VERSION 5.7 ;
  NOWIREEXTENSIONATPIN ON ;
  DIVIDERCHAR "/" ;
  BUSBITCHARS "[]" ;
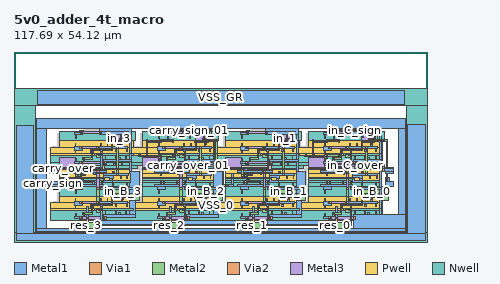
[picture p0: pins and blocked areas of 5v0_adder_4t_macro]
MACRO 5v0_adder_4t_macro
  CLASS BLOCK ;
  FOREIGN 5v0_adder_4t_macro ;
  ORIGIN 97.720 28.280 ;
  SIZE 117.690 BY 54.120 ;
  PIN VDD_1V65
    DIRECTION INOUT ;
    USE SIGNAL ;
    ANTENNADIFFAREA 2.102100 ;
    PORT
      LAYER Metal1 ;
        RECT -73.025 -18.050 -72.490 -17.485 ;
        RECT -49.350 -18.050 -48.815 -17.485 ;
        RECT -25.675 -18.050 -25.140 -17.485 ;
        RECT -2.000 -18.050 -1.465 -17.485 ;
        RECT -72.950 -18.850 -72.565 -18.050 ;
        RECT -49.275 -18.850 -48.890 -18.050 ;
        RECT -25.600 -18.850 -25.215 -18.050 ;
        RECT -1.925 -18.850 -1.540 -18.050 ;
        RECT -73.515 -19.340 -72.565 -18.850 ;
        RECT -49.840 -19.340 -48.890 -18.850 ;
        RECT -26.165 -19.340 -25.215 -18.850 ;
        RECT -2.490 -19.340 -1.540 -18.850 ;
        RECT -72.950 -22.125 -72.565 -19.340 ;
        RECT -49.275 -22.125 -48.890 -19.340 ;
        RECT -25.600 -22.125 -25.215 -19.340 ;
        RECT -72.950 -23.240 -57.735 -22.125 ;
        RECT -49.275 -23.240 -34.060 -22.125 ;
        RECT -25.600 -23.240 -10.385 -22.125 ;
        RECT -1.925 -23.240 -1.540 -19.340 ;
        RECT -77.040 -23.660 -1.535 -23.240 ;
      LAYER Via1 ;
        RECT -73.360 -19.300 -72.695 -18.925 ;
        RECT -49.685 -19.300 -49.020 -18.925 ;
        RECT -26.010 -19.300 -25.345 -18.925 ;
        RECT -2.335 -19.300 -1.670 -18.925 ;
      LAYER Metal2 ;
        RECT -74.225 -19.935 -72.635 -18.900 ;
        RECT -50.550 -19.935 -48.960 -18.900 ;
        RECT -26.875 -19.935 -25.285 -18.900 ;
        RECT -3.200 -19.935 -1.610 -18.900 ;
    END
  END VDD_1V65
  PIN res_0
    DIRECTION INOUT ;
    USE SIGNAL ;
    ANTENNADIFFAREA 1.060800 ;
    PORT
      LAYER Metal1 ;
        RECT -6.015 -22.680 -5.585 -18.035 ;
      LAYER Via1 ;
        RECT -6.015 -22.620 -5.585 -21.490 ;
      LAYER Metal2 ;
        RECT -6.025 -22.680 -5.575 -21.430 ;
        RECT -9.800 -24.360 -2.520 -22.680 ;
    END
  END res_0
  PIN res_1
    DIRECTION INOUT ;
    USE SIGNAL ;
    ANTENNADIFFAREA 1.060800 ;
    PORT
      LAYER Metal1 ;
        RECT -29.690 -22.680 -29.260 -18.035 ;
      LAYER Via1 ;
        RECT -29.690 -22.620 -29.260 -21.490 ;
      LAYER Metal2 ;
        RECT -29.700 -22.680 -29.250 -21.430 ;
        RECT -33.475 -24.360 -26.195 -22.680 ;
    END
  END res_1
  PIN res_2
    DIRECTION INOUT ;
    USE SIGNAL ;
    ANTENNADIFFAREA 1.060800 ;
    PORT
      LAYER Metal1 ;
        RECT -53.365 -22.680 -52.935 -18.035 ;
      LAYER Via1 ;
        RECT -53.365 -22.620 -52.935 -21.490 ;
      LAYER Metal2 ;
        RECT -53.375 -22.680 -52.925 -21.430 ;
        RECT -57.150 -24.360 -49.870 -22.680 ;
    END
  END res_2
  PIN res_3
    DIRECTION INOUT ;
    USE SIGNAL ;
    ANTENNADIFFAREA 1.060800 ;
    PORT
      LAYER Metal1 ;
        RECT -77.040 -22.680 -76.610 -18.035 ;
      LAYER Via1 ;
        RECT -77.040 -22.620 -76.610 -21.490 ;
      LAYER Metal2 ;
        RECT -77.050 -22.680 -76.600 -21.430 ;
        RECT -80.825 -24.360 -73.545 -22.680 ;
    END
  END res_3
  PIN carry_over
    DIRECTION OUTPUT ;
    USE SIGNAL ;
    ANTENNADIFFAREA 1.456350 ;
    PORT
      LAYER Metal1 ;
        RECT -87.640 -7.005 -85.395 -7.000 ;
        RECT -87.640 -7.560 -79.835 -7.005 ;
        RECT -87.640 -8.680 -85.395 -7.560 ;
        RECT -78.815 -9.410 -77.215 -9.180 ;
        RECT -78.815 -10.170 -78.525 -9.410 ;
        RECT -78.815 -10.405 -77.980 -10.170 ;
        RECT -78.255 -11.135 -77.980 -10.405 ;
        RECT -78.255 -11.405 -75.540 -11.135 ;
      LAYER Via1 ;
        RECT -80.385 -7.525 -79.900 -7.235 ;
        RECT -78.815 -9.760 -78.525 -9.275 ;
      LAYER Metal2 ;
        RECT -80.445 -7.540 -79.835 -7.215 ;
        RECT -80.210 -9.180 -79.835 -7.540 ;
        RECT -78.815 -9.180 -78.525 -9.175 ;
        RECT -80.210 -9.510 -78.515 -9.180 ;
        RECT -78.825 -9.820 -78.515 -9.510 ;
    END
  END carry_over
  PIN carry_sign
    DIRECTION OUTPUT ;
    USE SIGNAL ;
    ANTENNADIFFAREA 1.060800 ;
    PORT
      LAYER Metal1 ;
        RECT -87.640 -12.030 -85.395 -10.920 ;
        RECT -83.040 -12.030 -82.610 -8.810 ;
        RECT -87.640 -12.525 -82.610 -12.030 ;
        RECT -87.640 -12.600 -85.395 -12.525 ;
    END
  END carry_sign
  PIN in_C_sign
    DIRECTION INPUT ;
    USE SIGNAL ;
    ANTENNAGATEAREA 4.408000 ;
    PORT
      LAYER Metal1 ;
        RECT -12.600 -4.025 -12.275 0.935 ;
        RECT -8.800 -0.065 -8.475 0.935 ;
        RECT -5.355 -0.065 -5.030 0.935 ;
        RECT 8.120 -10.920 9.240 -10.025 ;
        RECT 8.120 -12.600 10.360 -10.920 ;
      LAYER Via1 ;
        RECT -12.600 0.040 -12.275 0.695 ;
        RECT -8.775 0.015 -8.505 0.860 ;
        RECT -5.320 0.330 -5.055 0.870 ;
        RECT -12.600 -3.785 -12.275 -3.130 ;
        RECT 8.265 -10.825 8.685 -10.085 ;
      LAYER Metal2 ;
        RECT -6.780 3.375 5.760 3.795 ;
        RECT -6.780 0.935 -6.360 3.375 ;
        RECT -12.610 0.350 -12.265 0.755 ;
        RECT -8.800 0.430 -5.025 0.935 ;
        RECT -8.800 0.350 -8.475 0.430 ;
        RECT -12.610 0.015 -8.475 0.350 ;
        RECT -5.360 0.265 -5.025 0.430 ;
        RECT 5.340 0.845 5.760 3.375 ;
        RECT 5.340 0.425 8.685 0.845 ;
        RECT -12.610 -0.020 -12.265 0.015 ;
        RECT -8.800 -0.065 -8.475 0.015 ;
        RECT -12.610 -3.845 -12.265 -3.070 ;
        RECT 8.265 -10.075 8.685 0.425 ;
        RECT 8.180 -10.840 8.770 -10.075 ;
    END
  END in_C_sign
  PIN in_C_over
    DIRECTION INPUT ;
    USE SIGNAL ;
    ANTENNAGATEAREA 2.814000 ;
    PORT
      LAYER Metal1 ;
        RECT -8.800 -3.225 -8.475 -3.025 ;
        RECT -14.775 -4.010 -14.475 -3.485 ;
        RECT -9.175 -4.025 -8.475 -3.225 ;
        RECT -5.355 -4.025 -5.030 -3.025 ;
        RECT 7.365 -7.380 7.785 -7.320 ;
        RECT 8.120 -7.380 10.360 -7.000 ;
        RECT 7.365 -8.120 10.360 -7.380 ;
        RECT 7.365 -8.180 7.785 -8.120 ;
        RECT 8.120 -8.680 10.360 -8.120 ;
      LAYER Via1 ;
        RECT -14.775 -3.935 -14.475 -3.565 ;
        RECT -8.760 -3.955 -8.490 -3.150 ;
        RECT -5.320 -3.960 -5.055 -3.420 ;
      LAYER Metal2 ;
        RECT -8.800 -3.360 -8.470 -3.090 ;
        RECT -7.635 -3.360 -6.540 -3.025 ;
        RECT -5.360 -3.360 -5.025 -3.355 ;
        RECT -14.785 -4.010 -14.465 -3.505 ;
        RECT -8.800 -4.025 -5.025 -3.360 ;
        RECT 7.355 -8.180 7.795 -7.320 ;
      LAYER Via2 ;
        RECT -14.775 -3.935 -14.475 -3.565 ;
        RECT -8.760 -3.955 -8.475 -3.150 ;
        RECT 7.365 -8.120 7.785 -7.380 ;
      LAYER Metal3 ;
        RECT -14.825 -3.630 -14.425 -3.565 ;
        RECT -8.810 -3.630 -8.425 -3.150 ;
        RECT -14.975 -3.955 -8.425 -3.630 ;
        RECT -8.725 -6.330 -8.425 -3.955 ;
        RECT -8.725 -6.655 7.785 -6.330 ;
        RECT 7.365 -8.180 7.785 -6.655 ;
    END
  END in_C_over
  PIN VSS_0
    DIRECTION INOUT ;
    USE GROUND ;
    PORT
      LAYER Pwell ;
        RECT -84.765 0.490 -74.915 0.495 ;
        RECT -61.090 0.490 -51.240 0.495 ;
        RECT -37.415 0.490 -27.565 0.495 ;
        RECT -13.740 0.490 -3.890 0.495 ;
        RECT -84.765 -1.395 -63.715 0.490 ;
        RECT -61.090 -1.395 -40.040 0.490 ;
        RECT -37.415 -1.395 -16.365 0.490 ;
        RECT -13.740 -1.395 7.310 0.490 ;
        RECT -87.450 -3.030 7.310 -1.395 ;
        RECT -87.450 -3.585 -74.915 -3.030 ;
        RECT -63.775 -3.585 -51.240 -3.030 ;
        RECT -40.100 -3.585 -27.565 -3.030 ;
        RECT -16.425 -3.585 -3.890 -3.030 ;
        RECT -71.805 -7.760 -64.660 -7.350 ;
        RECT -48.130 -7.760 -40.985 -7.350 ;
        RECT -24.455 -7.760 -17.310 -7.350 ;
        RECT -0.780 -7.760 6.365 -7.350 ;
        RECT -84.735 -8.680 -64.660 -7.760 ;
        RECT -61.060 -8.680 -40.985 -7.760 ;
        RECT -37.385 -8.680 -17.310 -7.760 ;
        RECT -13.710 -8.680 6.365 -7.760 ;
        RECT -84.735 -8.810 -64.655 -8.680 ;
        RECT -84.735 -9.950 -70.435 -8.810 ;
        RECT -77.965 -10.075 -76.865 -9.950 ;
        RECT -71.805 -10.785 -70.435 -9.950 ;
        RECT -70.370 -10.785 -64.655 -8.810 ;
        RECT -61.060 -8.810 -40.980 -8.680 ;
        RECT -61.060 -9.950 -46.760 -8.810 ;
        RECT -54.290 -10.075 -53.190 -9.950 ;
        RECT -71.805 -10.870 -64.655 -10.785 ;
        RECT -48.130 -10.785 -46.760 -9.950 ;
        RECT -46.695 -10.785 -40.980 -8.810 ;
        RECT -37.385 -8.810 -17.305 -8.680 ;
        RECT -37.385 -9.950 -23.085 -8.810 ;
        RECT -30.615 -10.075 -29.515 -9.950 ;
        RECT -48.130 -10.870 -40.980 -10.785 ;
        RECT -24.455 -10.785 -23.085 -9.950 ;
        RECT -23.020 -10.785 -17.305 -8.810 ;
        RECT -13.710 -8.810 6.370 -8.680 ;
        RECT -13.710 -9.950 0.590 -8.810 ;
        RECT -6.940 -10.075 -5.840 -9.950 ;
        RECT -24.455 -10.870 -17.305 -10.785 ;
        RECT -0.780 -10.785 0.590 -9.950 ;
        RECT 0.655 -10.785 6.370 -8.810 ;
        RECT -0.780 -10.870 6.370 -10.785 ;
        RECT -84.765 -15.190 -74.915 -15.185 ;
        RECT -61.090 -15.190 -51.240 -15.185 ;
        RECT -37.415 -15.190 -27.565 -15.185 ;
        RECT -13.740 -15.190 -3.890 -15.185 ;
        RECT -84.765 -17.075 -63.715 -15.190 ;
        RECT -61.090 -17.075 -40.040 -15.190 ;
        RECT -37.415 -17.075 -16.365 -15.190 ;
        RECT -13.740 -17.075 7.310 -15.190 ;
        RECT -87.450 -18.710 7.310 -17.075 ;
        RECT -87.450 -19.265 -74.915 -18.710 ;
        RECT -63.775 -19.265 -51.240 -18.710 ;
        RECT -40.100 -19.265 -27.565 -18.710 ;
        RECT -16.425 -19.265 -3.890 -18.710 ;
      LAYER Metal1 ;
        RECT -80.290 -0.965 -80.060 -0.105 ;
        RECT -80.535 -2.125 -78.295 -0.965 ;
        RECT -73.040 -0.970 -72.810 -0.215 ;
        RECT -71.200 -0.970 -70.970 -0.110 ;
        RECT -67.125 -0.540 -66.665 -0.310 ;
        RECT -67.070 -0.970 -66.720 -0.540 ;
        RECT -56.615 -0.965 -56.385 -0.105 ;
        RECT -66.410 -0.970 -65.835 -0.965 ;
        RECT -74.225 -1.570 -65.265 -0.970 ;
        RECT -68.790 -1.800 -68.495 -1.570 ;
        RECT -68.065 -1.645 -67.505 -1.570 ;
        RECT -80.290 -2.985 -80.060 -2.125 ;
        RECT -68.845 -2.370 -68.440 -1.800 ;
        RECT -65.740 -2.430 -65.510 -1.570 ;
        RECT -56.860 -2.125 -54.620 -0.965 ;
        RECT -49.365 -0.970 -49.135 -0.215 ;
        RECT -47.525 -0.970 -47.295 -0.110 ;
        RECT -43.450 -0.540 -42.990 -0.310 ;
        RECT -43.395 -0.970 -43.045 -0.540 ;
        RECT -32.940 -0.965 -32.710 -0.105 ;
        RECT -42.735 -0.970 -42.160 -0.965 ;
        RECT -50.550 -1.570 -41.590 -0.970 ;
        RECT -45.115 -1.800 -44.820 -1.570 ;
        RECT -44.390 -1.645 -43.830 -1.570 ;
        RECT -56.615 -2.985 -56.385 -2.125 ;
        RECT -45.170 -2.370 -44.765 -1.800 ;
        RECT -42.065 -2.430 -41.835 -1.570 ;
        RECT -33.185 -2.125 -30.945 -0.965 ;
        RECT -25.690 -0.970 -25.460 -0.215 ;
        RECT -23.850 -0.970 -23.620 -0.110 ;
        RECT -19.775 -0.540 -19.315 -0.310 ;
        RECT -19.720 -0.970 -19.370 -0.540 ;
        RECT -9.265 -0.965 -9.035 -0.105 ;
        RECT -19.060 -0.970 -18.485 -0.965 ;
        RECT -26.875 -1.570 -17.915 -0.970 ;
        RECT -21.440 -1.800 -21.145 -1.570 ;
        RECT -20.715 -1.645 -20.155 -1.570 ;
        RECT -32.940 -2.985 -32.710 -2.125 ;
        RECT -21.495 -2.370 -21.090 -1.800 ;
        RECT -18.390 -2.430 -18.160 -1.570 ;
        RECT -9.510 -2.125 -7.270 -0.965 ;
        RECT -2.015 -0.970 -1.785 -0.215 ;
        RECT -0.175 -0.970 0.055 -0.110 ;
        RECT 3.900 -0.540 4.360 -0.310 ;
        RECT 3.955 -0.970 4.305 -0.540 ;
        RECT 4.615 -0.970 5.190 -0.965 ;
        RECT -3.200 -1.570 5.760 -0.970 ;
        RECT 2.235 -1.800 2.530 -1.570 ;
        RECT 2.960 -1.645 3.520 -1.570 ;
        RECT -9.265 -2.985 -9.035 -2.125 ;
        RECT 2.180 -2.370 2.585 -1.800 ;
        RECT 5.285 -2.430 5.515 -1.570 ;
        RECT -79.545 -7.890 -78.655 -7.400 ;
        RECT -55.870 -7.890 -54.980 -7.400 ;
        RECT -32.195 -7.890 -31.305 -7.400 ;
        RECT -8.520 -7.890 -7.630 -7.400 ;
        RECT -81.355 -8.490 -71.425 -7.890 ;
        RECT -69.645 -8.380 -69.185 -8.150 ;
        RECT -79.590 -9.350 -79.360 -8.490 ;
        RECT -74.945 -8.950 -74.605 -8.490 ;
        RECT -72.330 -8.805 -71.425 -8.490 ;
        RECT -69.590 -8.805 -69.240 -8.380 ;
        RECT -57.680 -8.490 -47.750 -7.890 ;
        RECT -45.970 -8.380 -45.510 -8.150 ;
        RECT -72.330 -8.810 -69.240 -8.805 ;
        RECT -72.330 -9.410 -65.085 -8.810 ;
        RECT -55.915 -9.350 -55.685 -8.490 ;
        RECT -51.270 -8.950 -50.930 -8.490 ;
        RECT -48.655 -8.805 -47.750 -8.490 ;
        RECT -45.915 -8.805 -45.565 -8.380 ;
        RECT -34.005 -8.490 -24.075 -7.890 ;
        RECT -22.295 -8.380 -21.835 -8.150 ;
        RECT -48.655 -8.810 -45.565 -8.805 ;
        RECT -48.655 -9.410 -41.410 -8.810 ;
        RECT -32.240 -9.350 -32.010 -8.490 ;
        RECT -27.595 -8.950 -27.255 -8.490 ;
        RECT -24.980 -8.805 -24.075 -8.490 ;
        RECT -22.240 -8.805 -21.890 -8.380 ;
        RECT -10.330 -8.490 -0.400 -7.890 ;
        RECT 1.380 -8.380 1.840 -8.150 ;
        RECT -24.980 -8.810 -21.890 -8.805 ;
        RECT -24.980 -9.410 -17.735 -8.810 ;
        RECT -8.565 -9.350 -8.335 -8.490 ;
        RECT -3.920 -8.950 -3.580 -8.490 ;
        RECT -0.960 -8.805 -0.400 -8.490 ;
        RECT 1.435 -8.805 1.785 -8.380 ;
        RECT -1.305 -8.810 1.785 -8.805 ;
        RECT -1.305 -9.410 5.940 -8.810 ;
        RECT -72.330 -10.055 -69.465 -9.410 ;
        RECT -72.330 -11.385 -69.600 -10.055 ;
        RECT -67.455 -10.200 -67.225 -9.410 ;
        RECT -65.560 -10.270 -65.330 -9.410 ;
        RECT -48.655 -10.055 -45.790 -9.410 ;
        RECT -48.655 -11.385 -45.925 -10.055 ;
        RECT -43.780 -10.200 -43.550 -9.410 ;
        RECT -41.885 -10.270 -41.655 -9.410 ;
        RECT -24.980 -10.055 -22.115 -9.410 ;
        RECT -24.980 -11.385 -22.250 -10.055 ;
        RECT -20.105 -10.200 -19.875 -9.410 ;
        RECT -18.210 -10.270 -17.980 -9.410 ;
        RECT -1.305 -10.055 1.560 -9.410 ;
        RECT -1.305 -11.385 1.425 -10.055 ;
        RECT 3.570 -10.200 3.800 -9.410 ;
        RECT 5.465 -10.270 5.695 -9.410 ;
        RECT -80.290 -16.645 -80.060 -15.785 ;
        RECT -80.535 -17.805 -78.295 -16.645 ;
        RECT -73.040 -16.650 -72.810 -15.895 ;
        RECT -71.200 -16.650 -70.970 -15.790 ;
        RECT -67.125 -16.220 -66.665 -15.990 ;
        RECT -67.070 -16.650 -66.720 -16.220 ;
        RECT -56.615 -16.645 -56.385 -15.785 ;
        RECT -66.410 -16.650 -65.835 -16.645 ;
        RECT -74.225 -17.250 -65.265 -16.650 ;
        RECT -68.790 -17.480 -68.495 -17.250 ;
        RECT -68.065 -17.325 -67.505 -17.250 ;
        RECT -80.290 -18.665 -80.060 -17.805 ;
        RECT -68.845 -18.050 -68.440 -17.480 ;
        RECT -65.740 -18.110 -65.510 -17.250 ;
        RECT -56.860 -17.805 -54.620 -16.645 ;
        RECT -49.365 -16.650 -49.135 -15.895 ;
        RECT -47.525 -16.650 -47.295 -15.790 ;
        RECT -43.450 -16.220 -42.990 -15.990 ;
        RECT -43.395 -16.650 -43.045 -16.220 ;
        RECT -32.940 -16.645 -32.710 -15.785 ;
        RECT -42.735 -16.650 -42.160 -16.645 ;
        RECT -50.550 -17.250 -41.590 -16.650 ;
        RECT -45.115 -17.480 -44.820 -17.250 ;
        RECT -44.390 -17.325 -43.830 -17.250 ;
        RECT -56.615 -18.665 -56.385 -17.805 ;
        RECT -45.170 -18.050 -44.765 -17.480 ;
        RECT -42.065 -18.110 -41.835 -17.250 ;
        RECT -33.185 -17.805 -30.945 -16.645 ;
        RECT -25.690 -16.650 -25.460 -15.895 ;
        RECT -23.850 -16.650 -23.620 -15.790 ;
        RECT -19.775 -16.220 -19.315 -15.990 ;
        RECT -19.720 -16.650 -19.370 -16.220 ;
        RECT -9.265 -16.645 -9.035 -15.785 ;
        RECT -19.060 -16.650 -18.485 -16.645 ;
        RECT -26.875 -17.250 -17.915 -16.650 ;
        RECT -21.440 -17.480 -21.145 -17.250 ;
        RECT -20.715 -17.325 -20.155 -17.250 ;
        RECT -32.940 -18.665 -32.710 -17.805 ;
        RECT -21.495 -18.050 -21.090 -17.480 ;
        RECT -18.390 -18.110 -18.160 -17.250 ;
        RECT -9.510 -17.805 -7.270 -16.645 ;
        RECT -2.015 -16.650 -1.785 -15.895 ;
        RECT -0.175 -16.650 0.055 -15.790 ;
        RECT 3.900 -16.220 4.360 -15.990 ;
        RECT 3.955 -16.650 4.305 -16.220 ;
        RECT 4.615 -16.650 5.190 -16.645 ;
        RECT -3.200 -17.250 5.760 -16.650 ;
        RECT 2.235 -17.480 2.530 -17.250 ;
        RECT 2.960 -17.325 3.520 -17.250 ;
        RECT -9.265 -18.665 -9.035 -17.805 ;
        RECT 2.180 -18.050 2.585 -17.480 ;
        RECT 5.285 -18.110 5.515 -17.250 ;
      LAYER Via1 ;
        RECT -78.985 -1.570 -78.425 -0.970 ;
        RECT -74.140 -1.570 -73.580 -0.970 ;
        RECT -68.540 -1.570 -68.015 -1.095 ;
        RECT -55.310 -1.570 -54.750 -0.970 ;
        RECT -50.465 -1.570 -49.905 -0.970 ;
        RECT -44.865 -1.570 -44.340 -1.095 ;
        RECT -31.635 -1.570 -31.075 -0.970 ;
        RECT -26.790 -1.570 -26.230 -0.970 ;
        RECT -21.190 -1.570 -20.665 -1.095 ;
        RECT -7.960 -1.570 -7.400 -0.970 ;
        RECT -3.115 -1.570 -2.555 -0.970 ;
        RECT 2.485 -1.570 3.010 -1.095 ;
        RECT -74.140 -8.435 -73.500 -7.940 ;
        RECT -50.465 -8.435 -49.825 -7.940 ;
        RECT -68.540 -9.345 -68.015 -8.870 ;
        RECT -26.790 -8.435 -26.150 -7.940 ;
        RECT -44.865 -9.345 -44.340 -8.870 ;
        RECT -3.115 -8.435 -2.475 -7.940 ;
        RECT -21.190 -9.345 -20.665 -8.870 ;
        RECT 2.485 -9.345 3.010 -8.870 ;
        RECT -78.985 -17.250 -78.425 -16.650 ;
        RECT -74.140 -17.250 -73.580 -16.650 ;
        RECT -55.310 -17.250 -54.750 -16.650 ;
        RECT -50.465 -17.250 -49.905 -16.650 ;
        RECT -31.635 -17.250 -31.075 -16.650 ;
        RECT -26.790 -17.250 -26.230 -16.650 ;
        RECT -7.960 -17.250 -7.400 -16.650 ;
        RECT -3.115 -17.250 -2.555 -16.650 ;
      LAYER Metal2 ;
        RECT -79.045 -1.580 -78.365 -0.960 ;
        RECT -74.225 -1.585 -73.500 -0.960 ;
        RECT -68.560 -1.570 -67.995 -1.030 ;
        RECT -74.190 -8.490 -73.450 -7.890 ;
        RECT -68.555 -9.410 -67.995 -1.570 ;
        RECT -55.370 -1.580 -54.690 -0.960 ;
        RECT -50.550 -1.585 -49.825 -0.960 ;
        RECT -44.885 -1.570 -44.320 -1.030 ;
        RECT -50.515 -8.490 -49.775 -7.890 ;
        RECT -44.880 -9.410 -44.320 -1.570 ;
        RECT -31.695 -1.580 -31.015 -0.960 ;
        RECT -26.875 -1.585 -26.150 -0.960 ;
        RECT -21.210 -1.570 -20.645 -1.030 ;
        RECT -26.840 -8.490 -26.100 -7.890 ;
        RECT -21.205 -9.410 -20.645 -1.570 ;
        RECT -8.020 -1.580 -7.340 -0.960 ;
        RECT -3.200 -1.585 -2.475 -0.960 ;
        RECT 2.465 -1.570 3.030 -1.030 ;
        RECT -3.165 -8.490 -2.425 -7.890 ;
        RECT 2.470 -9.410 3.030 -1.570 ;
        RECT -74.140 -16.640 -73.500 -12.745 ;
        RECT -50.465 -16.640 -49.825 -12.745 ;
        RECT -26.790 -16.640 -26.150 -12.745 ;
        RECT -3.115 -16.640 -2.475 -12.745 ;
        RECT -79.045 -17.260 -78.365 -16.640 ;
        RECT -74.225 -17.265 -73.500 -16.640 ;
        RECT -55.370 -17.260 -54.690 -16.640 ;
        RECT -50.550 -17.265 -49.825 -16.640 ;
        RECT -31.695 -17.260 -31.015 -16.640 ;
        RECT -26.875 -17.265 -26.150 -16.640 ;
        RECT -8.020 -17.260 -7.340 -16.640 ;
        RECT -3.200 -17.265 -2.475 -16.640 ;
      LAYER Via2 ;
        RECT -78.985 -1.570 -78.425 -0.970 ;
        RECT -74.140 -1.570 -73.580 -0.970 ;
        RECT -74.140 -8.435 -73.500 -7.940 ;
        RECT -55.310 -1.570 -54.750 -0.970 ;
        RECT -50.465 -1.570 -49.905 -0.970 ;
        RECT -50.465 -8.435 -49.825 -7.940 ;
        RECT -31.635 -1.570 -31.075 -0.970 ;
        RECT -26.790 -1.570 -26.230 -0.970 ;
        RECT -26.790 -8.435 -26.150 -7.940 ;
        RECT -7.960 -1.570 -7.400 -0.970 ;
        RECT -3.115 -1.570 -2.555 -0.970 ;
        RECT -3.115 -8.435 -2.475 -7.940 ;
        RECT -74.140 -13.290 -73.500 -12.810 ;
        RECT -50.465 -13.290 -49.825 -12.810 ;
        RECT -26.790 -13.290 -26.150 -12.810 ;
        RECT -3.115 -13.290 -2.475 -12.810 ;
        RECT -78.985 -17.250 -78.425 -16.650 ;
        RECT -74.140 -17.250 -73.580 -16.650 ;
        RECT -55.310 -17.250 -54.750 -16.650 ;
        RECT -50.465 -17.250 -49.905 -16.650 ;
        RECT -31.635 -17.250 -31.075 -16.650 ;
        RECT -26.790 -17.250 -26.230 -16.650 ;
        RECT -7.960 -17.250 -7.400 -16.650 ;
        RECT -3.115 -17.250 -2.555 -16.650 ;
      LAYER Metal3 ;
        RECT -79.035 -1.570 -73.500 -0.970 ;
        RECT -55.360 -1.570 -49.825 -0.970 ;
        RECT -31.685 -1.570 -26.150 -0.970 ;
        RECT -8.010 -1.570 -2.475 -0.970 ;
        RECT -74.140 -13.340 -73.500 -7.890 ;
        RECT -50.465 -13.340 -49.825 -7.890 ;
        RECT -26.790 -13.340 -26.150 -7.890 ;
        RECT -3.115 -13.340 -2.475 -7.890 ;
        RECT -79.035 -17.250 -73.500 -16.650 ;
        RECT -55.360 -17.250 -49.825 -16.650 ;
        RECT -31.685 -17.250 -26.150 -16.650 ;
        RECT -8.010 -17.250 -2.475 -16.650 ;
    END
  END VSS_0
  PIN VDD_1V65_4
    DIRECTION INOUT ;
    USE SIGNAL ;
    ANTENNADIFFAREA 0.525525 ;
    PORT
      LAYER Metal1 ;
        RECT -73.025 -2.370 -72.490 -1.805 ;
        RECT -72.950 -3.170 -72.565 -2.370 ;
        RECT -73.515 -3.660 -72.565 -3.170 ;
        RECT -72.950 -7.035 -72.565 -3.660 ;
        RECT -78.275 -7.435 -72.565 -7.035 ;
      LAYER Via1 ;
        RECT -73.360 -3.620 -72.695 -3.245 ;
        RECT -78.215 -7.435 -77.625 -7.035 ;
      LAYER Metal2 ;
        RECT -74.225 -4.255 -72.635 -3.220 ;
        RECT -78.290 -7.445 -77.565 -7.020 ;
      LAYER Via2 ;
        RECT -78.215 -7.435 -77.625 -7.035 ;
      LAYER Metal3 ;
        RECT -84.770 -6.940 -80.275 -4.250 ;
        RECT -84.770 -7.435 -77.565 -6.940 ;
    END
  END VDD_1V65_4
  PIN VDD_1V65_3
    DIRECTION INOUT ;
    USE SIGNAL ;
    ANTENNADIFFAREA 0.525525 ;
    PORT
      LAYER Metal1 ;
        RECT -49.350 -2.370 -48.815 -1.805 ;
        RECT -49.275 -3.170 -48.890 -2.370 ;
        RECT -49.840 -3.660 -48.890 -3.170 ;
        RECT -49.275 -7.035 -48.890 -3.660 ;
        RECT -54.600 -7.435 -48.890 -7.035 ;
      LAYER Via1 ;
        RECT -49.685 -3.620 -49.020 -3.245 ;
        RECT -54.540 -7.435 -53.950 -7.035 ;
      LAYER Metal2 ;
        RECT -50.550 -4.255 -48.960 -3.220 ;
        RECT -54.615 -7.445 -53.890 -7.020 ;
      LAYER Via2 ;
        RECT -54.540 -7.435 -53.950 -7.035 ;
      LAYER Metal3 ;
        RECT -61.095 -6.940 -56.600 -4.250 ;
        RECT -61.095 -7.435 -53.890 -6.940 ;
    END
  END VDD_1V65_3
  PIN VDD_1V65_2
    DIRECTION INOUT ;
    USE SIGNAL ;
    ANTENNADIFFAREA 0.525525 ;
    PORT
      LAYER Metal1 ;
        RECT -25.675 -2.370 -25.140 -1.805 ;
        RECT -25.600 -3.170 -25.215 -2.370 ;
        RECT -26.165 -3.660 -25.215 -3.170 ;
        RECT -25.600 -7.035 -25.215 -3.660 ;
        RECT -30.925 -7.435 -25.215 -7.035 ;
      LAYER Via1 ;
        RECT -26.010 -3.620 -25.345 -3.245 ;
        RECT -30.865 -7.435 -30.275 -7.035 ;
      LAYER Metal2 ;
        RECT -26.875 -4.255 -25.285 -3.220 ;
        RECT -30.940 -7.445 -30.215 -7.020 ;
      LAYER Via2 ;
        RECT -30.865 -7.435 -30.275 -7.035 ;
      LAYER Metal3 ;
        RECT -37.420 -6.940 -32.925 -4.250 ;
        RECT -37.420 -7.435 -30.215 -6.940 ;
    END
  END VDD_1V65_2
  PIN VDD_1V65_1
    DIRECTION INOUT ;
    USE SIGNAL ;
    ANTENNADIFFAREA 0.525525 ;
    PORT
      LAYER Metal1 ;
        RECT -2.000 -2.370 -1.465 -1.805 ;
        RECT -1.925 -3.170 -1.540 -2.370 ;
        RECT -2.490 -3.660 -1.540 -3.170 ;
        RECT -1.925 -7.035 -1.540 -3.660 ;
        RECT -7.250 -7.435 -1.540 -7.035 ;
      LAYER Via1 ;
        RECT -2.335 -3.620 -1.670 -3.245 ;
        RECT -7.190 -7.435 -6.600 -7.035 ;
      LAYER Metal2 ;
        RECT -3.200 -4.255 -1.610 -3.220 ;
        RECT -7.265 -7.445 -6.540 -7.020 ;
      LAYER Via2 ;
        RECT -7.190 -7.435 -6.600 -7.035 ;
      LAYER Metal3 ;
        RECT -13.745 -6.940 -9.250 -4.250 ;
        RECT -13.745 -7.435 -6.540 -6.940 ;
    END
  END VDD_1V65_1
  PIN in_3
    DIRECTION INOUT ;
    USE SIGNAL ;
    ANTENNAGATEAREA 3.611400 ;
    ANTENNADIFFAREA 0.897600 ;
    PORT
      LAYER Metal1 ;
        RECT -66.575 1.090 -66.065 1.240 ;
        RECT -67.785 0.390 -66.065 1.090 ;
        RECT -69.855 0.190 -66.065 0.390 ;
        RECT -69.855 -0.070 -67.455 0.190 ;
        RECT -75.760 -2.125 -75.495 -2.015 ;
        RECT -75.820 -2.985 -75.495 -2.125 ;
        RECT -75.760 -3.075 -75.495 -2.985 ;
        RECT -78.065 -5.445 -77.585 -4.310 ;
      LAYER Via1 ;
        RECT -67.380 0.435 -66.140 0.980 ;
        RECT -68.590 -0.060 -67.755 0.380 ;
        RECT -75.760 -3.015 -75.495 -2.075 ;
        RECT -78.030 -5.330 -77.625 -4.395 ;
      LAYER Metal2 ;
        RECT -68.650 -0.070 -67.695 0.390 ;
        RECT -67.390 0.375 -66.130 1.040 ;
        RECT -75.770 -3.075 -75.160 -2.015 ;
        RECT -75.770 -4.310 -75.435 -3.075 ;
        RECT -78.070 -4.770 -75.435 -4.310 ;
        RECT -78.065 -5.445 -77.585 -4.770 ;
      LAYER Via2 ;
        RECT -67.380 0.435 -66.140 0.980 ;
        RECT -68.590 -0.070 -67.760 0.390 ;
        RECT -75.770 -2.905 -75.160 -2.125 ;
      LAYER Metal3 ;
        RECT -69.835 -0.070 -65.975 2.355 ;
        RECT -69.835 -2.015 -69.530 -0.070 ;
        RECT -75.820 -2.320 -69.530 -2.015 ;
        RECT -75.820 -2.905 -75.110 -2.320 ;
    END
  END in_3
  PIN in_2
    DIRECTION INOUT ;
    USE SIGNAL ;
    ANTENNAGATEAREA 3.611400 ;
    ANTENNADIFFAREA 0.897600 ;
    PORT
      LAYER Metal1 ;
        RECT -42.900 1.090 -42.390 1.240 ;
        RECT -44.110 0.390 -42.390 1.090 ;
        RECT -46.180 0.190 -42.390 0.390 ;
        RECT -46.180 -0.070 -43.780 0.190 ;
        RECT -52.085 -2.125 -51.820 -2.015 ;
        RECT -52.145 -2.985 -51.820 -2.125 ;
        RECT -52.085 -3.075 -51.820 -2.985 ;
        RECT -54.390 -5.445 -53.910 -4.310 ;
      LAYER Via1 ;
        RECT -43.705 0.435 -42.465 0.980 ;
        RECT -44.915 -0.060 -44.080 0.380 ;
        RECT -52.085 -3.015 -51.820 -2.075 ;
        RECT -54.355 -5.330 -53.950 -4.395 ;
      LAYER Metal2 ;
        RECT -44.975 -0.070 -44.020 0.390 ;
        RECT -43.715 0.375 -42.455 1.040 ;
        RECT -52.095 -3.075 -51.485 -2.015 ;
        RECT -52.095 -4.310 -51.760 -3.075 ;
        RECT -54.395 -4.770 -51.760 -4.310 ;
        RECT -54.390 -5.445 -53.910 -4.770 ;
      LAYER Via2 ;
        RECT -43.705 0.435 -42.465 0.980 ;
        RECT -44.915 -0.070 -44.085 0.390 ;
        RECT -52.095 -2.905 -51.485 -2.125 ;
      LAYER Metal3 ;
        RECT -46.160 -0.070 -42.300 2.350 ;
        RECT -46.160 -2.015 -45.855 -0.070 ;
        RECT -52.145 -2.320 -45.855 -2.015 ;
        RECT -52.145 -2.905 -51.435 -2.320 ;
    END
  END in_2
  PIN in_1
    DIRECTION INOUT ;
    USE SIGNAL ;
    ANTENNAGATEAREA 3.611400 ;
    ANTENNADIFFAREA 0.897600 ;
    PORT
      LAYER Metal1 ;
        RECT -19.225 1.090 -18.715 1.240 ;
        RECT -20.435 0.390 -18.715 1.090 ;
        RECT -22.505 0.190 -18.715 0.390 ;
        RECT -22.505 -0.070 -20.105 0.190 ;
        RECT -28.410 -2.125 -28.145 -2.015 ;
        RECT -28.470 -2.985 -28.145 -2.125 ;
        RECT -28.410 -3.075 -28.145 -2.985 ;
        RECT -30.715 -5.445 -30.235 -4.310 ;
      LAYER Via1 ;
        RECT -20.030 0.435 -18.790 0.980 ;
        RECT -21.240 -0.060 -20.405 0.380 ;
        RECT -28.410 -3.015 -28.145 -2.075 ;
        RECT -30.680 -5.330 -30.275 -4.395 ;
      LAYER Metal2 ;
        RECT -21.300 -0.070 -20.345 0.390 ;
        RECT -20.040 0.375 -18.780 1.040 ;
        RECT -28.420 -3.075 -27.810 -2.015 ;
        RECT -28.420 -4.310 -28.085 -3.075 ;
        RECT -30.720 -4.770 -28.085 -4.310 ;
        RECT -30.715 -5.445 -30.235 -4.770 ;
      LAYER Via2 ;
        RECT -20.030 0.435 -18.790 0.980 ;
        RECT -21.240 -0.070 -20.410 0.390 ;
        RECT -28.420 -2.905 -27.810 -2.125 ;
      LAYER Metal3 ;
        RECT -22.485 -0.070 -18.625 2.350 ;
        RECT -22.485 -2.015 -22.180 -0.070 ;
        RECT -28.470 -2.320 -22.180 -2.015 ;
        RECT -28.470 -2.905 -27.760 -2.320 ;
    END
  END in_1
  PIN in_0
    DIRECTION INOUT ;
    USE SIGNAL ;
    ANTENNAGATEAREA 3.611400 ;
    ANTENNADIFFAREA 0.897600 ;
    PORT
      LAYER Metal1 ;
        RECT 4.450 1.090 4.960 1.240 ;
        RECT 3.240 0.390 4.960 1.090 ;
        RECT 1.170 0.190 4.960 0.390 ;
        RECT 1.170 -0.070 3.570 0.190 ;
        RECT -4.735 -2.125 -4.470 -2.015 ;
        RECT -4.795 -2.985 -4.470 -2.125 ;
        RECT -4.735 -3.075 -4.470 -2.985 ;
        RECT -7.040 -5.445 -6.560 -4.310 ;
      LAYER Via1 ;
        RECT 3.645 0.435 4.885 0.980 ;
        RECT 2.435 -0.060 3.270 0.380 ;
        RECT -4.735 -3.015 -4.470 -2.075 ;
        RECT -7.005 -5.330 -6.600 -4.395 ;
      LAYER Metal2 ;
        RECT 2.375 -0.070 3.330 0.390 ;
        RECT 3.635 0.375 4.895 1.040 ;
        RECT -4.745 -3.075 -4.135 -2.015 ;
        RECT -4.745 -4.310 -4.410 -3.075 ;
        RECT -7.045 -4.770 -4.410 -4.310 ;
        RECT -7.040 -5.445 -6.560 -4.770 ;
      LAYER Via2 ;
        RECT 3.645 0.435 4.885 0.980 ;
        RECT 2.435 -0.070 3.265 0.390 ;
        RECT -4.745 -2.905 -4.135 -2.125 ;
      LAYER Metal3 ;
        RECT 1.190 -0.070 5.050 2.350 ;
        RECT 1.190 -2.015 1.495 -0.070 ;
        RECT -4.795 -2.320 1.495 -2.015 ;
        RECT -4.795 -2.905 -4.085 -2.320 ;
    END
  END in_0
  PIN in_B_0
    DIRECTION INOUT ;
    USE SIGNAL ;
    ANTENNAGATEAREA 3.611400 ;
    ANTENNADIFFAREA 0.897600 ;
    PORT
      LAYER Metal1 ;
        RECT 4.450 -14.590 4.960 -14.440 ;
        RECT 3.240 -15.290 4.960 -14.590 ;
        RECT 1.170 -15.490 4.960 -15.290 ;
        RECT 1.170 -15.750 3.570 -15.490 ;
        RECT -4.735 -17.805 -4.470 -17.695 ;
        RECT -4.795 -18.665 -4.470 -17.805 ;
        RECT -4.735 -18.755 -4.470 -18.665 ;
        RECT -7.040 -21.125 -6.560 -19.990 ;
      LAYER Via1 ;
        RECT 2.435 -15.740 3.270 -15.300 ;
        RECT -4.735 -18.695 -4.470 -17.755 ;
        RECT -7.005 -21.010 -6.600 -20.075 ;
      LAYER Metal2 ;
        RECT -0.425 -14.595 8.930 -13.160 ;
        RECT 2.435 -15.290 3.340 -14.595 ;
        RECT 2.375 -15.750 3.340 -15.290 ;
        RECT 6.320 -16.520 8.930 -14.595 ;
        RECT -4.745 -18.755 -4.135 -17.695 ;
        RECT -4.745 -19.990 -4.410 -18.755 ;
        RECT -7.045 -20.450 -4.410 -19.990 ;
        RECT -7.040 -21.125 -6.560 -20.450 ;
      LAYER Via2 ;
        RECT 2.435 -15.750 3.265 -15.290 ;
        RECT -4.745 -18.585 -4.135 -17.805 ;
      LAYER Metal3 ;
        RECT 2.385 -15.445 3.315 -15.290 ;
        RECT 1.190 -15.750 3.315 -15.445 ;
        RECT 1.190 -17.695 1.495 -15.750 ;
        RECT -4.795 -18.000 1.495 -17.695 ;
        RECT -4.795 -18.585 -4.085 -18.000 ;
    END
  END in_B_0
  PIN in_B_1
    DIRECTION INOUT ;
    USE SIGNAL ;
    ANTENNAGATEAREA 3.611400 ;
    ANTENNADIFFAREA 0.897600 ;
    PORT
      LAYER Metal1 ;
        RECT -19.225 -14.590 -18.715 -14.440 ;
        RECT -20.435 -15.290 -18.715 -14.590 ;
        RECT -22.505 -15.490 -18.715 -15.290 ;
        RECT -22.505 -15.750 -20.105 -15.490 ;
        RECT -28.410 -17.805 -28.145 -17.695 ;
        RECT -28.470 -18.665 -28.145 -17.805 ;
        RECT -28.410 -18.755 -28.145 -18.665 ;
        RECT -30.715 -21.125 -30.235 -19.990 ;
      LAYER Via1 ;
        RECT -21.240 -15.740 -20.405 -15.300 ;
        RECT -28.410 -18.695 -28.145 -17.755 ;
        RECT -30.680 -21.010 -30.275 -20.075 ;
      LAYER Metal2 ;
        RECT -24.100 -14.595 -14.745 -13.160 ;
        RECT -21.240 -15.290 -20.335 -14.595 ;
        RECT -21.300 -15.750 -20.335 -15.290 ;
        RECT -17.355 -16.520 -14.745 -14.595 ;
        RECT -28.420 -18.755 -27.810 -17.695 ;
        RECT -28.420 -19.990 -28.085 -18.755 ;
        RECT -30.720 -20.450 -28.085 -19.990 ;
        RECT -30.715 -21.125 -30.235 -20.450 ;
      LAYER Via2 ;
        RECT -21.240 -15.750 -20.410 -15.290 ;
        RECT -28.420 -18.585 -27.810 -17.805 ;
      LAYER Metal3 ;
        RECT -21.290 -15.445 -20.360 -15.290 ;
        RECT -22.485 -15.750 -20.360 -15.445 ;
        RECT -22.485 -17.695 -22.180 -15.750 ;
        RECT -28.470 -18.000 -22.180 -17.695 ;
        RECT -28.470 -18.585 -27.760 -18.000 ;
    END
  END in_B_1
  PIN in_B_2
    DIRECTION INOUT ;
    USE SIGNAL ;
    ANTENNAGATEAREA 3.611400 ;
    ANTENNADIFFAREA 0.897600 ;
    PORT
      LAYER Metal1 ;
        RECT -42.900 -14.590 -42.390 -14.440 ;
        RECT -44.110 -15.290 -42.390 -14.590 ;
        RECT -46.180 -15.490 -42.390 -15.290 ;
        RECT -46.180 -15.750 -43.780 -15.490 ;
        RECT -52.085 -17.805 -51.820 -17.695 ;
        RECT -52.145 -18.665 -51.820 -17.805 ;
        RECT -52.085 -18.755 -51.820 -18.665 ;
        RECT -54.390 -21.125 -53.910 -19.990 ;
      LAYER Via1 ;
        RECT -44.915 -15.740 -44.080 -15.300 ;
        RECT -52.085 -18.695 -51.820 -17.755 ;
        RECT -54.355 -21.010 -53.950 -20.075 ;
      LAYER Metal2 ;
        RECT -47.775 -14.595 -38.420 -13.160 ;
        RECT -44.915 -15.290 -44.010 -14.595 ;
        RECT -44.975 -15.750 -44.010 -15.290 ;
        RECT -41.030 -16.520 -38.420 -14.595 ;
        RECT -52.095 -18.755 -51.485 -17.695 ;
        RECT -52.095 -19.990 -51.760 -18.755 ;
        RECT -54.395 -20.450 -51.760 -19.990 ;
        RECT -54.390 -21.125 -53.910 -20.450 ;
      LAYER Via2 ;
        RECT -44.915 -15.750 -44.085 -15.290 ;
        RECT -52.095 -18.585 -51.485 -17.805 ;
      LAYER Metal3 ;
        RECT -44.965 -15.445 -44.035 -15.290 ;
        RECT -46.160 -15.750 -44.035 -15.445 ;
        RECT -46.160 -17.695 -45.855 -15.750 ;
        RECT -52.145 -18.000 -45.855 -17.695 ;
        RECT -52.145 -18.585 -51.435 -18.000 ;
    END
  END in_B_2
  PIN in_B_3
    DIRECTION INOUT ;
    USE SIGNAL ;
    ANTENNAGATEAREA 3.611400 ;
    ANTENNADIFFAREA 0.897600 ;
    PORT
      LAYER Metal1 ;
        RECT -66.575 -14.590 -66.065 -14.440 ;
        RECT -67.785 -15.290 -66.065 -14.590 ;
        RECT -69.855 -15.490 -66.065 -15.290 ;
        RECT -69.855 -15.750 -67.455 -15.490 ;
        RECT -75.760 -17.805 -75.495 -17.695 ;
        RECT -75.820 -18.665 -75.495 -17.805 ;
        RECT -75.760 -18.755 -75.495 -18.665 ;
        RECT -78.065 -21.125 -77.585 -19.990 ;
      LAYER Via1 ;
        RECT -68.590 -15.740 -67.755 -15.300 ;
        RECT -75.760 -18.695 -75.495 -17.755 ;
        RECT -78.030 -21.010 -77.625 -20.075 ;
      LAYER Metal2 ;
        RECT -71.450 -14.595 -62.095 -13.160 ;
        RECT -68.590 -15.290 -67.685 -14.595 ;
        RECT -68.650 -15.750 -67.685 -15.290 ;
        RECT -64.705 -16.520 -62.095 -14.595 ;
        RECT -75.770 -18.755 -75.160 -17.695 ;
        RECT -75.770 -19.990 -75.435 -18.755 ;
        RECT -78.070 -20.450 -75.435 -19.990 ;
        RECT -78.065 -21.125 -77.585 -20.450 ;
      LAYER Via2 ;
        RECT -68.590 -15.750 -67.760 -15.290 ;
        RECT -75.770 -18.585 -75.160 -17.805 ;
      LAYER Metal3 ;
        RECT -68.640 -15.445 -67.710 -15.290 ;
        RECT -69.835 -15.750 -67.710 -15.445 ;
        RECT -69.835 -17.695 -69.530 -15.750 ;
        RECT -75.820 -18.000 -69.530 -17.695 ;
        RECT -75.820 -18.585 -75.110 -18.000 ;
    END
  END in_B_3
  PIN VDD_3V3_3
    DIRECTION INOUT ;
    USE POWER ;
    PORT
      LAYER Nwell ;
        RECT -78.955 3.495 -78.015 3.500 ;
        RECT -55.280 3.495 -54.340 3.500 ;
        RECT -31.605 3.495 -30.665 3.500 ;
        RECT -7.930 3.495 -6.990 3.500 ;
        RECT -78.955 3.085 -77.995 3.495 ;
        RECT -55.280 3.085 -54.320 3.495 ;
        RECT -31.605 3.085 -30.645 3.495 ;
        RECT -7.930 3.085 -6.970 3.495 ;
        RECT -84.765 3.080 -64.970 3.085 ;
        RECT -61.090 3.080 -41.295 3.085 ;
        RECT -37.415 3.080 -17.620 3.085 ;
        RECT -13.740 3.080 6.055 3.085 ;
        RECT -84.765 0.495 -63.215 3.080 ;
        RECT -61.090 0.495 -39.540 3.080 ;
        RECT -37.415 0.495 -15.865 3.080 ;
        RECT -13.740 0.495 7.810 3.080 ;
        RECT -74.915 0.490 -63.215 0.495 ;
        RECT -51.240 0.490 -39.540 0.495 ;
        RECT -27.565 0.490 -15.865 0.495 ;
        RECT -3.890 0.490 7.810 0.495 ;
        RECT -67.935 -3.035 -63.775 -3.030 ;
        RECT -44.260 -3.035 -40.100 -3.030 ;
        RECT -20.585 -3.035 -16.425 -3.030 ;
        RECT 3.090 -3.035 7.250 -3.030 ;
        RECT -74.915 -3.585 -63.775 -3.035 ;
        RECT -51.240 -3.585 -40.100 -3.035 ;
        RECT -27.565 -3.585 -16.425 -3.035 ;
        RECT -3.890 -3.585 7.250 -3.035 ;
        RECT -87.450 -5.620 7.250 -3.585 ;
        RECT -87.450 -6.605 6.365 -5.620 ;
        RECT -71.805 -7.350 -62.635 -6.605 ;
        RECT -48.130 -7.350 -38.960 -6.605 ;
        RECT -24.455 -7.350 -15.285 -6.605 ;
        RECT -0.780 -7.350 6.365 -6.605 ;
        RECT -84.735 -10.075 -77.965 -9.950 ;
        RECT -76.865 -10.075 -71.805 -9.950 ;
        RECT -84.735 -10.870 -71.805 -10.075 ;
        RECT -61.060 -10.075 -54.290 -9.950 ;
        RECT -53.190 -10.075 -48.130 -9.950 ;
        RECT -61.060 -10.870 -48.130 -10.075 ;
        RECT -37.385 -10.075 -30.615 -9.950 ;
        RECT -29.515 -10.075 -24.455 -9.950 ;
        RECT -37.385 -10.870 -24.455 -10.075 ;
        RECT -13.710 -10.075 -6.940 -9.950 ;
        RECT -5.840 -10.075 -0.780 -9.950 ;
        RECT -13.710 -10.870 -0.780 -10.075 ;
        RECT -84.735 -11.320 -64.655 -10.870 ;
        RECT -61.060 -11.320 -40.980 -10.870 ;
        RECT -37.385 -11.320 -17.305 -10.870 ;
        RECT -13.710 -11.320 6.370 -10.870 ;
        RECT -84.765 -12.600 -64.655 -11.320 ;
        RECT -61.090 -12.600 -40.980 -11.320 ;
        RECT -37.415 -12.600 -17.305 -11.320 ;
        RECT -13.740 -12.600 6.370 -11.320 ;
        RECT -84.765 -15.185 -63.215 -12.600 ;
        RECT -61.090 -15.185 -39.540 -12.600 ;
        RECT -37.415 -15.185 -15.865 -12.600 ;
        RECT -13.740 -15.185 7.810 -12.600 ;
        RECT -74.915 -15.190 -63.215 -15.185 ;
        RECT -51.240 -15.190 -39.540 -15.185 ;
        RECT -27.565 -15.190 -15.865 -15.185 ;
        RECT -3.890 -15.190 7.810 -15.185 ;
        RECT -67.935 -18.715 -63.775 -18.710 ;
        RECT -44.260 -18.715 -40.100 -18.710 ;
        RECT -20.585 -18.715 -16.425 -18.710 ;
        RECT 3.090 -18.715 7.250 -18.710 ;
        RECT -74.915 -19.265 -63.775 -18.715 ;
        RECT -51.240 -19.265 -40.100 -18.715 ;
        RECT -27.565 -19.265 -16.425 -18.715 ;
        RECT -3.890 -19.265 7.250 -18.715 ;
        RECT -87.450 -22.270 7.250 -19.265 ;
      LAYER Metal1 ;
        RECT -91.360 3.980 13.790 6.770 ;
        RECT -91.360 -24.340 -88.520 3.980 ;
        RECT -78.750 2.975 -78.295 3.215 ;
        RECT -79.135 2.955 -78.295 2.975 ;
        RECT -80.535 2.355 -78.295 2.955 ;
        RECT -80.190 1.265 -79.960 2.355 ;
        RECT -73.440 2.350 -64.145 3.980 ;
        RECT -55.075 2.975 -54.620 3.215 ;
        RECT -55.460 2.955 -54.620 2.975 ;
        RECT -56.860 2.355 -54.620 2.955 ;
        RECT -71.300 1.260 -71.070 2.350 ;
        RECT -69.365 1.925 -69.135 2.350 ;
        RECT -67.320 2.055 -67.090 2.350 ;
        RECT -69.420 1.355 -69.080 1.925 ;
        RECT -67.375 1.355 -67.035 2.055 ;
        RECT -80.190 -5.445 -79.960 -4.355 ;
        RECT -71.755 -4.890 -71.525 -3.810 ;
        RECT -68.790 -4.890 -68.560 -3.810 ;
        RECT -68.015 -4.890 -67.455 -4.330 ;
        RECT -65.840 -4.890 -65.610 -3.800 ;
        RECT -64.705 -4.890 -64.145 2.350 ;
        RECT -56.515 1.265 -56.285 2.355 ;
        RECT -49.765 2.350 -40.470 3.980 ;
        RECT -31.400 2.975 -30.945 3.215 ;
        RECT -31.785 2.955 -30.945 2.975 ;
        RECT -33.185 2.355 -30.945 2.955 ;
        RECT -47.625 1.260 -47.395 2.350 ;
        RECT -45.690 1.925 -45.460 2.350 ;
        RECT -43.645 2.055 -43.415 2.350 ;
        RECT -45.745 1.355 -45.405 1.925 ;
        RECT -43.700 1.355 -43.360 2.055 ;
        RECT -80.535 -6.045 -78.295 -5.445 ;
        RECT -79.135 -6.065 -78.295 -6.045 ;
        RECT -72.155 -5.490 -64.145 -4.890 ;
        RECT -56.515 -5.445 -56.285 -4.355 ;
        RECT -48.080 -4.890 -47.850 -3.810 ;
        RECT -45.115 -4.890 -44.885 -3.810 ;
        RECT -44.340 -4.890 -43.780 -4.330 ;
        RECT -42.165 -4.890 -41.935 -3.800 ;
        RECT -41.030 -4.890 -40.470 2.350 ;
        RECT -32.840 1.265 -32.610 2.355 ;
        RECT -26.090 2.350 -16.795 3.980 ;
        RECT -7.725 2.975 -7.270 3.215 ;
        RECT -8.110 2.955 -7.270 2.975 ;
        RECT -9.510 2.355 -7.270 2.955 ;
        RECT -23.950 1.260 -23.720 2.350 ;
        RECT -22.015 1.925 -21.785 2.350 ;
        RECT -19.970 2.055 -19.740 2.350 ;
        RECT -22.070 1.355 -21.730 1.925 ;
        RECT -20.025 1.355 -19.685 2.055 ;
        RECT -72.155 -6.065 -71.425 -5.490 ;
        RECT -69.220 -5.785 -68.990 -5.490 ;
        RECT -78.725 -6.305 -78.295 -6.065 ;
        RECT -69.275 -6.485 -68.935 -5.785 ;
        RECT -67.175 -5.915 -66.945 -5.490 ;
        RECT -67.230 -6.485 -66.890 -5.915 ;
        RECT -64.705 -8.120 -64.145 -5.490 ;
        RECT -56.860 -6.045 -54.620 -5.445 ;
        RECT -55.460 -6.065 -54.620 -6.045 ;
        RECT -48.480 -5.490 -40.470 -4.890 ;
        RECT -32.840 -5.445 -32.610 -4.355 ;
        RECT -24.405 -4.890 -24.175 -3.810 ;
        RECT -21.440 -4.890 -21.210 -3.810 ;
        RECT -20.665 -4.890 -20.105 -4.330 ;
        RECT -18.490 -4.890 -18.260 -3.800 ;
        RECT -17.355 -4.890 -16.795 2.350 ;
        RECT -9.165 1.265 -8.935 2.355 ;
        RECT -2.415 2.350 6.880 3.980 ;
        RECT -0.275 1.260 -0.045 2.350 ;
        RECT 1.660 1.925 1.890 2.350 ;
        RECT 3.705 2.055 3.935 2.350 ;
        RECT 1.605 1.355 1.945 1.925 ;
        RECT 3.650 1.355 3.990 2.055 ;
        RECT -48.480 -6.065 -47.750 -5.490 ;
        RECT -45.545 -5.785 -45.315 -5.490 ;
        RECT -55.050 -6.305 -54.620 -6.065 ;
        RECT -45.600 -6.485 -45.260 -5.785 ;
        RECT -43.500 -5.915 -43.270 -5.490 ;
        RECT -43.555 -6.485 -43.215 -5.915 ;
        RECT -41.030 -8.120 -40.470 -5.490 ;
        RECT -33.185 -6.045 -30.945 -5.445 ;
        RECT -31.785 -6.065 -30.945 -6.045 ;
        RECT -24.805 -5.490 -16.795 -4.890 ;
        RECT -9.165 -5.445 -8.935 -4.355 ;
        RECT -0.730 -4.890 -0.500 -3.810 ;
        RECT 2.235 -4.890 2.465 -3.810 ;
        RECT 3.010 -4.890 3.570 -4.330 ;
        RECT 5.185 -4.890 5.415 -3.800 ;
        RECT 6.320 -4.890 6.880 2.350 ;
        RECT -24.805 -6.065 -24.075 -5.490 ;
        RECT -21.870 -5.785 -21.640 -5.490 ;
        RECT -31.375 -6.305 -30.945 -6.065 ;
        RECT -21.925 -6.485 -21.585 -5.785 ;
        RECT -19.825 -5.915 -19.595 -5.490 ;
        RECT -19.880 -6.485 -19.540 -5.915 ;
        RECT -17.355 -8.120 -16.795 -5.490 ;
        RECT -9.510 -6.045 -7.270 -5.445 ;
        RECT -8.110 -6.065 -7.270 -6.045 ;
        RECT -1.130 -5.490 6.880 -4.890 ;
        RECT -1.130 -6.065 -0.400 -5.490 ;
        RECT 1.805 -5.785 2.035 -5.490 ;
        RECT -7.700 -6.305 -7.270 -6.065 ;
        RECT 1.750 -6.485 2.090 -5.785 ;
        RECT 3.850 -5.915 4.080 -5.490 ;
        RECT 3.795 -6.485 4.135 -5.915 ;
        RECT -79.690 -11.810 -79.460 -10.720 ;
        RECT -78.770 -11.810 -78.540 -10.880 ;
        RECT -75.225 -11.810 -74.885 -11.120 ;
        RECT -72.850 -11.810 -72.620 -10.910 ;
        RECT -81.355 -12.410 -72.235 -11.810 ;
        RECT -80.535 -13.325 -78.295 -12.410 ;
        RECT -72.965 -12.730 -72.235 -12.410 ;
        RECT -69.695 -12.730 -69.465 -11.640 ;
        RECT -65.660 -12.730 -65.430 -11.640 ;
        RECT -64.705 -12.730 -62.095 -8.120 ;
        RECT -56.015 -11.810 -55.785 -10.720 ;
        RECT -55.095 -11.810 -54.865 -10.880 ;
        RECT -51.550 -11.810 -51.210 -11.120 ;
        RECT -49.175 -11.810 -48.945 -10.910 ;
        RECT -57.680 -12.410 -48.560 -11.810 ;
        RECT -80.190 -14.415 -79.960 -13.325 ;
        RECT -72.965 -13.330 -62.095 -12.730 ;
        RECT -56.860 -13.325 -54.620 -12.410 ;
        RECT -49.290 -12.730 -48.560 -12.410 ;
        RECT -46.020 -12.730 -45.790 -11.640 ;
        RECT -41.985 -12.730 -41.755 -11.640 ;
        RECT -41.030 -12.730 -38.420 -8.120 ;
        RECT -32.340 -11.810 -32.110 -10.720 ;
        RECT -31.420 -11.810 -31.190 -10.880 ;
        RECT -27.875 -11.810 -27.535 -11.120 ;
        RECT -25.500 -11.810 -25.270 -10.910 ;
        RECT -34.005 -12.410 -24.885 -11.810 ;
        RECT -71.300 -14.420 -71.070 -13.330 ;
        RECT -69.365 -13.755 -69.135 -13.330 ;
        RECT -67.320 -13.625 -67.090 -13.330 ;
        RECT -69.420 -14.325 -69.080 -13.755 ;
        RECT -67.375 -14.325 -67.035 -13.625 ;
        RECT -64.705 -16.520 -62.095 -13.330 ;
        RECT -56.515 -14.415 -56.285 -13.325 ;
        RECT -49.290 -13.330 -38.420 -12.730 ;
        RECT -33.185 -13.325 -30.945 -12.410 ;
        RECT -25.615 -12.730 -24.885 -12.410 ;
        RECT -22.345 -12.730 -22.115 -11.640 ;
        RECT -18.310 -12.730 -18.080 -11.640 ;
        RECT -17.355 -12.730 -14.745 -8.120 ;
        RECT -8.665 -11.810 -8.435 -10.720 ;
        RECT -7.745 -11.810 -7.515 -10.880 ;
        RECT -4.200 -11.810 -3.860 -11.120 ;
        RECT -1.825 -11.810 -1.595 -10.910 ;
        RECT -10.330 -12.410 -1.210 -11.810 ;
        RECT -47.625 -14.420 -47.395 -13.330 ;
        RECT -45.690 -13.755 -45.460 -13.330 ;
        RECT -43.645 -13.625 -43.415 -13.330 ;
        RECT -45.745 -14.325 -45.405 -13.755 ;
        RECT -43.700 -14.325 -43.360 -13.625 ;
        RECT -41.030 -16.520 -38.420 -13.330 ;
        RECT -32.840 -14.415 -32.610 -13.325 ;
        RECT -25.615 -13.330 -14.745 -12.730 ;
        RECT -9.510 -13.325 -7.270 -12.410 ;
        RECT -1.940 -12.730 -1.210 -12.410 ;
        RECT 1.330 -12.730 1.560 -11.640 ;
        RECT 5.365 -12.730 5.595 -11.640 ;
        RECT 6.320 -12.730 6.880 -5.490 ;
        RECT -23.950 -14.420 -23.720 -13.330 ;
        RECT -22.015 -13.755 -21.785 -13.330 ;
        RECT -19.970 -13.625 -19.740 -13.330 ;
        RECT -22.070 -14.325 -21.730 -13.755 ;
        RECT -20.025 -14.325 -19.685 -13.625 ;
        RECT -17.355 -16.520 -14.745 -13.330 ;
        RECT -9.165 -14.415 -8.935 -13.325 ;
        RECT -1.940 -13.330 6.880 -12.730 ;
        RECT -0.275 -14.420 -0.045 -13.330 ;
        RECT 1.660 -13.755 1.890 -13.330 ;
        RECT 3.705 -13.625 3.935 -13.330 ;
        RECT 1.605 -14.325 1.945 -13.755 ;
        RECT 3.650 -14.325 3.990 -13.625 ;
        RECT -80.190 -21.125 -79.960 -20.035 ;
        RECT -71.755 -20.570 -71.525 -19.490 ;
        RECT -68.790 -20.570 -68.560 -19.490 ;
        RECT -68.015 -20.570 -67.455 -20.010 ;
        RECT -65.840 -20.570 -65.610 -19.480 ;
        RECT -64.705 -20.570 -63.155 -16.520 ;
        RECT -80.535 -21.725 -78.295 -21.125 ;
        RECT -79.135 -21.745 -78.295 -21.725 ;
        RECT -72.155 -21.170 -63.155 -20.570 ;
        RECT -56.515 -21.125 -56.285 -20.035 ;
        RECT -48.080 -20.570 -47.850 -19.490 ;
        RECT -45.115 -20.570 -44.885 -19.490 ;
        RECT -44.340 -20.570 -43.780 -20.010 ;
        RECT -42.165 -20.570 -41.935 -19.480 ;
        RECT -41.030 -20.570 -39.480 -16.520 ;
        RECT -72.155 -21.745 -71.425 -21.170 ;
        RECT -56.860 -21.725 -54.620 -21.125 ;
        RECT -55.460 -21.745 -54.620 -21.725 ;
        RECT -48.480 -21.170 -39.480 -20.570 ;
        RECT -32.840 -21.125 -32.610 -20.035 ;
        RECT -24.405 -20.570 -24.175 -19.490 ;
        RECT -21.440 -20.570 -21.210 -19.490 ;
        RECT -20.665 -20.570 -20.105 -20.010 ;
        RECT -18.490 -20.570 -18.260 -19.480 ;
        RECT -17.355 -20.570 -15.805 -16.520 ;
        RECT -48.480 -21.745 -47.750 -21.170 ;
        RECT -33.185 -21.725 -30.945 -21.125 ;
        RECT -31.785 -21.745 -30.945 -21.725 ;
        RECT -24.805 -21.170 -15.805 -20.570 ;
        RECT -9.165 -21.125 -8.935 -20.035 ;
        RECT -0.730 -20.570 -0.500 -19.490 ;
        RECT 2.235 -20.570 2.465 -19.490 ;
        RECT 3.010 -20.570 3.570 -20.010 ;
        RECT 5.185 -20.570 5.415 -19.480 ;
        RECT 6.320 -20.570 6.880 -13.330 ;
        RECT 11.850 -20.570 13.790 3.980 ;
        RECT -24.805 -21.745 -24.075 -21.170 ;
        RECT -9.510 -21.725 -7.270 -21.125 ;
        RECT -8.110 -21.745 -7.270 -21.725 ;
        RECT -78.725 -21.985 -78.295 -21.745 ;
        RECT -55.050 -21.985 -54.620 -21.745 ;
        RECT -31.375 -21.985 -30.945 -21.745 ;
        RECT -7.700 -21.985 -7.270 -21.745 ;
        RECT -1.130 -24.340 13.790 -20.570 ;
        RECT -91.360 -25.150 13.790 -24.340 ;
      LAYER Via1 ;
        RECT -78.750 2.460 -78.295 3.060 ;
        RECT -73.375 2.350 -72.920 2.950 ;
        RECT -55.075 2.460 -54.620 3.060 ;
        RECT -49.700 2.350 -49.245 2.950 ;
        RECT -31.400 2.460 -30.945 3.060 ;
        RECT -79.050 -6.050 -78.490 -5.450 ;
        RECT -26.025 2.350 -25.570 2.950 ;
        RECT -7.725 2.460 -7.270 3.060 ;
        RECT -72.070 -6.050 -71.510 -5.450 ;
        RECT -55.375 -6.050 -54.815 -5.450 ;
        RECT -2.350 2.350 -1.895 2.950 ;
        RECT -48.395 -6.050 -47.835 -5.450 ;
        RECT -31.700 -6.050 -31.140 -5.450 ;
        RECT -24.720 -6.050 -24.160 -5.450 ;
        RECT -8.025 -6.050 -7.465 -5.450 ;
        RECT -1.045 -6.050 -0.485 -5.450 ;
        RECT -79.050 -21.730 -78.490 -21.130 ;
        RECT -72.070 -21.730 -71.510 -21.130 ;
        RECT -55.375 -21.730 -54.815 -21.130 ;
        RECT -48.395 -21.730 -47.835 -21.130 ;
        RECT -31.700 -21.730 -31.140 -21.130 ;
        RECT -24.720 -21.730 -24.160 -21.130 ;
        RECT -8.025 -21.730 -7.465 -21.130 ;
        RECT -1.045 -21.730 -0.485 -21.130 ;
      LAYER Metal2 ;
        RECT -78.825 2.450 -78.215 3.075 ;
        RECT -73.440 2.340 -72.845 3.075 ;
        RECT -55.150 2.450 -54.540 3.075 ;
        RECT -49.765 2.340 -49.170 3.075 ;
        RECT -31.475 2.450 -30.865 3.075 ;
        RECT -26.090 2.340 -25.495 3.075 ;
        RECT -7.800 2.450 -7.190 3.075 ;
        RECT -2.415 2.340 -1.820 3.075 ;
        RECT -79.130 -6.065 -78.405 -5.440 ;
        RECT -72.155 -6.065 -71.430 -5.440 ;
        RECT -55.455 -6.065 -54.730 -5.440 ;
        RECT -48.480 -6.065 -47.755 -5.440 ;
        RECT -31.780 -6.065 -31.055 -5.440 ;
        RECT -24.805 -6.065 -24.080 -5.440 ;
        RECT -8.105 -6.065 -7.380 -5.440 ;
        RECT -1.130 -6.065 -0.405 -5.440 ;
        RECT -79.130 -21.745 -78.405 -21.120 ;
        RECT -72.155 -21.745 -71.430 -21.120 ;
        RECT -55.455 -21.745 -54.730 -21.120 ;
        RECT -48.480 -21.745 -47.755 -21.120 ;
        RECT -31.780 -21.745 -31.055 -21.120 ;
        RECT -24.805 -21.745 -24.080 -21.120 ;
        RECT -8.105 -21.745 -7.380 -21.120 ;
        RECT -1.130 -21.745 -0.405 -21.120 ;
      LAYER Via2 ;
        RECT -78.750 2.460 -78.295 3.060 ;
        RECT -73.375 2.350 -72.920 2.950 ;
        RECT -55.075 2.460 -54.620 3.060 ;
        RECT -49.700 2.350 -49.245 2.950 ;
        RECT -31.400 2.460 -30.945 3.060 ;
        RECT -26.025 2.350 -25.570 2.950 ;
        RECT -7.725 2.460 -7.270 3.060 ;
        RECT -2.350 2.350 -1.895 2.950 ;
        RECT -79.050 -6.050 -78.490 -5.450 ;
        RECT -72.070 -6.050 -71.510 -5.450 ;
        RECT -55.375 -6.050 -54.815 -5.450 ;
        RECT -48.395 -6.050 -47.835 -5.450 ;
        RECT -31.700 -6.050 -31.140 -5.450 ;
        RECT -24.720 -6.050 -24.160 -5.450 ;
        RECT -8.025 -6.050 -7.465 -5.450 ;
        RECT -1.045 -6.050 -0.485 -5.450 ;
        RECT -79.050 -21.730 -78.490 -21.130 ;
        RECT -72.070 -21.730 -71.510 -21.130 ;
        RECT -55.375 -21.730 -54.815 -21.130 ;
        RECT -48.395 -21.730 -47.835 -21.130 ;
        RECT -31.700 -21.730 -31.140 -21.130 ;
        RECT -24.720 -21.730 -24.160 -21.130 ;
        RECT -8.025 -21.730 -7.465 -21.130 ;
        RECT -1.045 -21.730 -0.485 -21.130 ;
      LAYER Metal3 ;
        RECT -78.295 3.060 -72.870 3.075 ;
        RECT -54.620 3.060 -49.195 3.075 ;
        RECT -30.945 3.060 -25.520 3.075 ;
        RECT -7.270 3.060 -1.845 3.075 ;
        RECT -78.800 2.640 -72.870 3.060 ;
        RECT -78.800 2.460 -78.245 2.640 ;
        RECT -73.440 2.350 -72.870 2.640 ;
        RECT -55.125 2.640 -49.195 3.060 ;
        RECT -55.125 2.460 -54.570 2.640 ;
        RECT -49.765 2.350 -49.195 2.640 ;
        RECT -31.450 2.640 -25.520 3.060 ;
        RECT -31.450 2.460 -30.895 2.640 ;
        RECT -26.090 2.350 -25.520 2.640 ;
        RECT -7.775 2.640 -1.845 3.060 ;
        RECT -7.775 2.460 -7.220 2.640 ;
        RECT -2.415 2.350 -1.845 2.640 ;
        RECT -79.130 -6.050 -71.430 -5.450 ;
        RECT -55.455 -6.050 -47.755 -5.450 ;
        RECT -31.780 -6.050 -24.080 -5.450 ;
        RECT -8.105 -6.050 -0.405 -5.450 ;
        RECT -79.130 -21.730 -71.430 -21.130 ;
        RECT -55.455 -21.730 -47.755 -21.130 ;
        RECT -31.780 -21.730 -24.080 -21.130 ;
        RECT -8.105 -21.730 -0.405 -21.130 ;
    END
  END VDD_3V3_3
  PIN carry_sign_01
    DIRECTION INOUT ;
    USE SIGNAL ;
    ANTENNAGATEAREA 4.408000 ;
    ANTENNADIFFAREA 1.060800 ;
    PORT
      LAYER Metal1 ;
        RECT -59.950 -4.025 -59.625 0.935 ;
        RECT -56.150 -0.065 -55.825 0.935 ;
        RECT -52.705 -0.065 -52.380 0.935 ;
        RECT -35.690 -12.030 -35.260 -8.810 ;
        RECT -37.475 -12.525 -35.260 -12.030 ;
      LAYER Via1 ;
        RECT -59.950 0.040 -59.625 0.695 ;
        RECT -56.125 0.015 -55.855 0.860 ;
        RECT -52.670 0.330 -52.405 0.870 ;
        RECT -59.950 -3.785 -59.625 -3.130 ;
        RECT -37.415 -12.505 -36.810 -12.050 ;
      LAYER Metal2 ;
        RECT -54.130 3.375 -41.590 3.795 ;
        RECT -54.130 0.935 -53.710 3.375 ;
        RECT -59.960 0.350 -59.615 0.755 ;
        RECT -56.150 0.430 -52.375 0.935 ;
        RECT -56.150 0.350 -55.825 0.430 ;
        RECT -59.960 0.015 -55.825 0.350 ;
        RECT -52.710 0.265 -52.375 0.430 ;
        RECT -42.010 0.845 -41.590 3.375 ;
        RECT -42.010 0.425 -39.790 0.845 ;
        RECT -59.960 -0.020 -59.615 0.015 ;
        RECT -56.150 -0.065 -55.825 0.015 ;
        RECT -59.960 -3.845 -59.615 -3.070 ;
        RECT -40.230 -6.325 -39.790 0.425 ;
        RECT -40.230 -6.655 -37.960 -6.325 ;
        RECT -38.240 -12.030 -37.960 -6.655 ;
        RECT -38.240 -12.525 -36.750 -12.030 ;
    END
  END carry_sign_01
  PIN carry_over_01
    DIRECTION INOUT ;
    USE SIGNAL ;
    ANTENNAGATEAREA 2.814000 ;
    ANTENNADIFFAREA 1.456350 ;
    PORT
      LAYER Metal1 ;
        RECT -56.150 -3.225 -55.825 -3.025 ;
        RECT -62.125 -4.010 -61.825 -3.485 ;
        RECT -56.525 -4.025 -55.825 -3.225 ;
        RECT -52.705 -4.025 -52.380 -3.025 ;
        RECT -39.835 -7.525 -32.485 -7.235 ;
        RECT -31.465 -9.410 -29.865 -9.180 ;
        RECT -31.465 -10.170 -31.175 -9.410 ;
        RECT -31.465 -10.405 -30.630 -10.170 ;
        RECT -30.905 -11.135 -30.630 -10.405 ;
        RECT -30.905 -11.405 -28.190 -11.135 ;
      LAYER Via1 ;
        RECT -62.125 -3.935 -61.825 -3.565 ;
        RECT -56.110 -3.955 -55.840 -3.150 ;
        RECT -52.670 -3.960 -52.405 -3.420 ;
        RECT -39.775 -7.525 -39.265 -7.235 ;
        RECT -33.035 -7.525 -32.550 -7.235 ;
        RECT -31.465 -9.760 -31.175 -9.275 ;
      LAYER Metal2 ;
        RECT -56.150 -3.360 -55.820 -3.090 ;
        RECT -54.985 -3.360 -53.890 -3.025 ;
        RECT -52.710 -3.360 -52.375 -3.355 ;
        RECT -62.135 -4.010 -61.815 -3.505 ;
        RECT -56.150 -4.025 -52.375 -3.360 ;
        RECT -39.835 -7.535 -39.205 -7.225 ;
        RECT -33.095 -7.540 -32.485 -7.215 ;
        RECT -32.860 -9.180 -32.485 -7.540 ;
        RECT -31.465 -9.180 -31.175 -9.175 ;
        RECT -32.860 -9.510 -31.165 -9.180 ;
        RECT -31.475 -9.820 -31.165 -9.510 ;
      LAYER Via2 ;
        RECT -62.125 -3.935 -61.825 -3.565 ;
        RECT -56.110 -3.955 -55.825 -3.150 ;
        RECT -39.775 -7.525 -39.265 -7.235 ;
      LAYER Metal3 ;
        RECT -62.175 -3.630 -61.775 -3.565 ;
        RECT -56.160 -3.630 -55.775 -3.150 ;
        RECT -62.325 -3.955 -55.775 -3.630 ;
        RECT -56.075 -6.330 -55.775 -3.955 ;
        RECT -56.075 -6.655 -40.230 -6.330 ;
        RECT -40.550 -7.235 -40.230 -6.655 ;
        RECT -40.550 -7.525 -39.215 -7.235 ;
    END
  END carry_over_01
  PIN VSS_GR
    DIRECTION INOUT ;
    USE GROUND ;
    PORT
      LAYER Nwell ;
        RECT -97.720 10.495 19.970 15.415 ;
        RECT -97.720 -25.440 -91.575 10.495 ;
        RECT 14.005 -25.440 19.970 10.495 ;
        RECT -97.720 -28.280 19.970 -25.440 ;
      LAYER Metal1 ;
        RECT -90.935 10.965 13.545 14.945 ;
        RECT -97.065 -25.905 -92.045 4.950 ;
        RECT 14.475 -25.905 19.495 5.060 ;
        RECT -97.065 -27.810 19.500 -25.905 ;
    END
  END VSS_GR
  OBS
      LAYER Metal1 ;
        RECT -77.960 2.640 -74.935 3.030 ;
        RECT -85.340 2.610 -85.100 2.615 ;
        RECT -83.070 2.610 -82.740 2.615 ;
        RECT -85.340 2.380 -82.740 2.610 ;
        RECT -85.340 -1.170 -85.100 2.380 ;
        RECT -83.990 1.615 -83.760 2.145 ;
        RECT -86.870 -1.405 -85.100 -1.170 ;
        RECT -84.755 1.265 -83.760 1.615 ;
        RECT -83.070 2.125 -82.740 2.380 ;
        RECT -86.870 -6.165 -86.610 -1.405 ;
        RECT -85.980 -1.945 -85.420 -1.675 ;
        RECT -86.375 -5.215 -86.045 -2.355 ;
        RECT -85.255 -2.780 -85.025 -2.125 ;
        RECT -85.255 -2.985 -84.985 -2.780 ;
        RECT -85.800 -4.010 -85.500 -3.485 ;
        RECT -85.220 -4.355 -84.985 -2.985 ;
        RECT -85.355 -4.590 -84.985 -4.355 ;
        RECT -84.755 -4.355 -84.495 1.265 ;
        RECT -84.260 -0.590 -83.860 -0.105 ;
        RECT -84.260 -2.985 -83.860 -2.500 ;
        RECT -83.625 -4.025 -83.300 0.935 ;
        RECT -83.070 -0.535 -82.640 2.125 ;
        RECT -82.055 1.255 -81.720 2.180 ;
        RECT -79.270 1.820 -78.940 2.125 ;
        RECT -79.595 1.300 -78.940 1.820 ;
        RECT -81.115 0.935 -80.400 1.160 ;
        RECT -82.410 0.640 -80.400 0.935 ;
        RECT -85.355 -5.580 -85.125 -4.590 ;
        RECT -84.755 -4.705 -83.760 -4.355 ;
        RECT -83.990 -5.235 -83.760 -4.705 ;
        RECT -83.070 -5.580 -82.640 -2.555 ;
        RECT -82.410 -4.025 -82.085 0.640 ;
        RECT -79.825 -0.065 -79.500 0.935 ;
        RECT -79.270 0.640 -78.940 1.300 ;
        RECT -77.960 1.265 -77.730 2.640 ;
        RECT -77.595 0.640 -77.270 0.935 ;
        RECT -79.270 0.190 -77.270 0.640 ;
        RECT -81.850 -2.840 -81.510 -0.250 ;
        RECT -79.270 -0.735 -78.940 0.190 ;
        RECT -77.595 -0.065 -77.270 0.190 ;
        RECT -78.060 -0.305 -77.830 -0.105 ;
        RECT -78.060 -0.965 -77.675 -0.305 ;
        RECT -78.025 -1.100 -77.675 -0.965 ;
        RECT -77.040 -0.735 -76.610 2.125 ;
        RECT -75.920 1.160 -75.495 2.360 ;
        RECT -76.380 -0.065 -76.055 0.935 ;
        RECT -75.240 0.340 -74.935 2.640 ;
        RECT -54.285 2.640 -51.260 3.030 ;
        RECT -61.665 2.610 -61.425 2.615 ;
        RECT -59.395 2.610 -59.065 2.615 ;
        RECT -61.665 2.380 -59.065 2.610 ;
        RECT -72.545 1.205 -71.990 2.120 ;
        RECT -72.320 0.585 -71.990 1.205 ;
        RECT -70.405 1.095 -70.160 2.120 ;
        RECT -68.340 1.095 -68.015 2.120 ;
        RECT -65.870 1.575 -65.540 1.945 ;
        RECT -65.870 1.470 -65.370 1.575 ;
        RECT -75.245 -0.105 -74.935 0.340 ;
        RECT -73.765 0.055 -71.990 0.585 ;
        RECT -75.820 -0.185 -74.935 -0.105 ;
        RECT -77.040 -1.470 -76.615 -0.735 ;
        RECT -75.820 -0.740 -73.830 -0.185 ;
        RECT -72.320 -0.740 -71.990 0.055 ;
        RECT -71.760 0.445 -71.435 0.930 ;
        RECT -70.405 0.640 -68.015 1.095 ;
        RECT -70.405 0.445 -70.150 0.640 ;
        RECT -71.760 0.130 -70.150 0.445 ;
        RECT -71.760 -0.070 -71.435 0.130 ;
        RECT -70.480 -0.740 -70.150 0.130 ;
        RECT -65.835 -0.735 -65.370 1.470 ;
        RECT -75.820 -0.965 -74.935 -0.740 ;
        RECT -78.060 -1.785 -74.935 -1.470 ;
        RECT -78.060 -2.165 -77.825 -1.785 ;
        RECT -79.825 -3.225 -79.500 -3.025 ;
        RECT -80.765 -4.105 -80.475 -3.360 ;
        RECT -80.200 -4.025 -79.500 -3.225 ;
        RECT -79.270 -3.240 -78.940 -2.355 ;
        RECT -78.060 -2.985 -77.830 -2.165 ;
        RECT -77.595 -3.240 -77.270 -3.025 ;
        RECT -79.270 -3.940 -77.270 -3.240 ;
        RECT -82.055 -5.270 -81.720 -4.345 ;
        RECT -81.265 -5.215 -80.880 -4.450 ;
        RECT -79.270 -4.650 -78.940 -3.940 ;
        RECT -77.595 -4.025 -77.270 -3.940 ;
        RECT -79.685 -5.080 -78.940 -4.650 ;
        RECT -79.270 -5.215 -78.940 -5.080 ;
        RECT -85.355 -5.870 -82.640 -5.580 ;
        RECT -81.485 -5.870 -81.020 -5.215 ;
        RECT -86.870 -6.405 -84.290 -6.165 ;
        RECT -77.040 -6.180 -76.610 -2.355 ;
        RECT -76.380 -4.025 -76.055 -3.025 ;
        RECT -75.240 -4.350 -74.935 -1.785 ;
        RECT -74.705 -1.815 -74.455 -0.740 ;
        RECT -61.665 -1.170 -61.425 2.380 ;
        RECT -60.315 1.615 -60.085 2.145 ;
        RECT -63.195 -1.405 -61.425 -1.170 ;
        RECT -61.080 1.265 -60.085 1.615 ;
        RECT -59.395 2.125 -59.065 2.380 ;
        RECT -74.705 -2.045 -73.805 -1.815 ;
        RECT -74.230 -2.370 -73.805 -2.045 ;
        RECT -71.095 -2.370 -70.465 -1.800 ;
        RECT -74.230 -3.895 -73.880 -2.370 ;
        RECT -73.650 -2.935 -73.180 -2.540 ;
        RECT -72.335 -3.530 -71.970 -2.780 ;
        RECT -71.550 -2.835 -70.990 -2.600 ;
        RECT -71.495 -3.245 -71.045 -2.835 ;
        RECT -70.290 -2.935 -69.840 -2.540 ;
        RECT -69.435 -3.245 -68.935 -2.830 ;
        RECT -66.860 -3.245 -66.530 -1.800 ;
        RECT -71.495 -3.575 -66.530 -3.245 ;
        RECT -66.300 -3.470 -65.975 -2.465 ;
        RECT -74.230 -4.320 -73.230 -3.895 ;
        RECT -75.920 -5.465 -74.935 -4.350 ;
        RECT -73.570 -4.595 -73.230 -4.320 ;
        RECT -69.865 -4.660 -69.480 -3.830 ;
        RECT -66.860 -4.660 -66.530 -3.575 ;
        RECT -77.040 -6.400 -76.615 -6.180 ;
        RECT -70.770 -6.265 -70.440 -5.895 ;
        RECT -70.900 -6.370 -70.440 -6.265 ;
        RECT -85.005 -6.430 -84.290 -6.405 ;
        RECT -84.530 -6.440 -84.290 -6.430 ;
        RECT -70.900 -7.750 -70.475 -6.370 ;
        RECT -70.245 -6.750 -69.735 -6.600 ;
        RECT -68.295 -6.745 -67.970 -5.720 ;
        RECT -66.150 -6.745 -65.905 -5.720 ;
        RECT -63.195 -6.165 -62.935 -1.405 ;
        RECT -62.305 -1.945 -61.745 -1.675 ;
        RECT -62.700 -5.215 -62.370 -2.355 ;
        RECT -61.580 -2.780 -61.350 -2.125 ;
        RECT -61.580 -2.985 -61.310 -2.780 ;
        RECT -61.545 -4.355 -61.310 -2.985 ;
        RECT -61.680 -4.590 -61.310 -4.355 ;
        RECT -61.080 -4.355 -60.820 1.265 ;
        RECT -60.585 -0.590 -60.185 -0.105 ;
        RECT -59.395 -0.535 -58.965 2.125 ;
        RECT -58.380 1.255 -58.045 2.180 ;
        RECT -55.595 1.820 -55.265 2.125 ;
        RECT -55.920 1.300 -55.265 1.820 ;
        RECT -57.440 0.935 -56.725 1.160 ;
        RECT -58.735 0.640 -56.725 0.935 ;
        RECT -55.595 0.640 -55.265 1.300 ;
        RECT -54.285 1.265 -54.055 2.640 ;
        RECT -53.920 0.640 -53.595 0.935 ;
        RECT -60.585 -2.985 -60.185 -2.500 ;
        RECT -61.680 -5.580 -61.450 -4.590 ;
        RECT -61.080 -4.705 -60.085 -4.355 ;
        RECT -60.315 -5.235 -60.085 -4.705 ;
        RECT -59.395 -5.580 -58.965 -2.555 ;
        RECT -58.735 -4.025 -58.410 0.640 ;
        RECT -55.595 0.190 -53.595 0.640 ;
        RECT -58.175 -2.840 -57.835 -0.250 ;
        RECT -55.595 -0.735 -55.265 0.190 ;
        RECT -53.920 -0.065 -53.595 0.190 ;
        RECT -54.385 -0.305 -54.155 -0.105 ;
        RECT -54.385 -0.965 -54.000 -0.305 ;
        RECT -54.350 -1.100 -54.000 -0.965 ;
        RECT -53.365 -0.735 -52.935 2.125 ;
        RECT -52.245 1.160 -51.820 2.360 ;
        RECT -51.565 0.340 -51.260 2.640 ;
        RECT -30.610 2.640 -27.585 3.030 ;
        RECT -37.990 2.610 -37.750 2.615 ;
        RECT -35.720 2.610 -35.390 2.615 ;
        RECT -37.990 2.380 -35.390 2.610 ;
        RECT -48.870 1.205 -48.315 2.120 ;
        RECT -48.645 0.585 -48.315 1.205 ;
        RECT -46.730 1.095 -46.485 2.120 ;
        RECT -44.665 1.095 -44.340 2.120 ;
        RECT -42.195 1.575 -41.865 1.945 ;
        RECT -42.195 1.470 -41.695 1.575 ;
        RECT -51.570 -0.105 -51.260 0.340 ;
        RECT -50.090 0.055 -48.315 0.585 ;
        RECT -52.145 -0.185 -51.260 -0.105 ;
        RECT -53.365 -1.470 -52.940 -0.735 ;
        RECT -52.145 -0.740 -50.155 -0.185 ;
        RECT -48.645 -0.740 -48.315 0.055 ;
        RECT -48.085 0.445 -47.760 0.930 ;
        RECT -46.730 0.640 -44.340 1.095 ;
        RECT -46.730 0.445 -46.475 0.640 ;
        RECT -48.085 0.130 -46.475 0.445 ;
        RECT -48.085 -0.070 -47.760 0.130 ;
        RECT -46.805 -0.740 -46.475 0.130 ;
        RECT -42.160 -0.735 -41.695 1.470 ;
        RECT -52.145 -0.965 -51.260 -0.740 ;
        RECT -54.385 -1.785 -51.260 -1.470 ;
        RECT -54.385 -2.165 -54.150 -1.785 ;
        RECT -55.595 -3.240 -55.265 -2.355 ;
        RECT -54.385 -2.985 -54.155 -2.165 ;
        RECT -53.920 -3.240 -53.595 -3.025 ;
        RECT -57.090 -4.105 -56.800 -3.360 ;
        RECT -55.595 -3.940 -53.595 -3.240 ;
        RECT -58.380 -5.270 -58.045 -4.345 ;
        RECT -57.590 -5.215 -57.205 -4.450 ;
        RECT -55.595 -4.650 -55.265 -3.940 ;
        RECT -53.920 -4.025 -53.595 -3.940 ;
        RECT -56.010 -5.080 -55.265 -4.650 ;
        RECT -55.595 -5.215 -55.265 -5.080 ;
        RECT -61.680 -5.870 -58.965 -5.580 ;
        RECT -57.810 -5.870 -57.345 -5.215 ;
        RECT -63.195 -6.405 -60.615 -6.165 ;
        RECT -53.365 -6.180 -52.935 -2.355 ;
        RECT -51.565 -4.350 -51.260 -1.785 ;
        RECT -51.030 -1.815 -50.780 -0.740 ;
        RECT -37.990 -1.170 -37.750 2.380 ;
        RECT -36.640 1.615 -36.410 2.145 ;
        RECT -39.520 -1.405 -37.750 -1.170 ;
        RECT -37.405 1.265 -36.410 1.615 ;
        RECT -35.720 2.125 -35.390 2.380 ;
        RECT -51.030 -2.045 -50.130 -1.815 ;
        RECT -50.555 -2.370 -50.130 -2.045 ;
        RECT -47.420 -2.370 -46.790 -1.800 ;
        RECT -50.555 -3.895 -50.205 -2.370 ;
        RECT -49.975 -2.935 -49.505 -2.540 ;
        RECT -48.660 -3.530 -48.295 -2.780 ;
        RECT -47.875 -2.835 -47.315 -2.600 ;
        RECT -47.820 -3.245 -47.370 -2.835 ;
        RECT -46.615 -2.935 -46.165 -2.540 ;
        RECT -45.760 -3.245 -45.260 -2.830 ;
        RECT -43.185 -3.245 -42.855 -1.800 ;
        RECT -47.820 -3.575 -42.855 -3.245 ;
        RECT -42.625 -3.470 -42.300 -2.465 ;
        RECT -50.555 -4.320 -49.555 -3.895 ;
        RECT -52.245 -5.465 -51.260 -4.350 ;
        RECT -49.895 -4.595 -49.555 -4.320 ;
        RECT -46.190 -4.660 -45.805 -3.830 ;
        RECT -43.185 -4.660 -42.855 -3.575 ;
        RECT -53.365 -6.400 -52.940 -6.180 ;
        RECT -47.095 -6.265 -46.765 -5.895 ;
        RECT -47.225 -6.370 -46.765 -6.265 ;
        RECT -61.330 -6.430 -60.615 -6.405 ;
        RECT -60.855 -6.440 -60.615 -6.430 ;
        RECT -70.245 -7.450 -68.525 -6.750 ;
        RECT -68.295 -7.200 -65.905 -6.745 ;
        RECT -70.245 -7.650 -66.455 -7.450 ;
        RECT -70.900 -7.825 -70.455 -7.750 ;
        RECT -84.530 -8.300 -83.945 -8.195 ;
        RECT -84.530 -8.575 -81.590 -8.300 ;
        RECT -70.715 -8.570 -70.455 -7.825 ;
        RECT -68.855 -7.910 -66.455 -7.650 ;
        RECT -66.160 -7.710 -65.905 -7.200 ;
        RECT -63.510 -7.525 -56.160 -7.235 ;
        RECT -84.530 -10.720 -84.290 -8.575 ;
        RECT -84.060 -9.350 -83.760 -8.810 ;
        RECT -81.930 -9.150 -81.590 -8.575 ;
        RECT -66.160 -8.580 -65.830 -7.710 ;
        RECT -47.225 -7.750 -46.800 -6.370 ;
        RECT -46.570 -6.750 -46.060 -6.600 ;
        RECT -44.620 -6.745 -44.295 -5.720 ;
        RECT -42.475 -6.745 -42.230 -5.720 ;
        RECT -39.520 -6.165 -39.260 -1.405 ;
        RECT -38.630 -1.945 -38.070 -1.675 ;
        RECT -39.025 -5.215 -38.695 -2.355 ;
        RECT -37.905 -2.780 -37.675 -2.125 ;
        RECT -37.905 -2.985 -37.635 -2.780 ;
        RECT -38.450 -4.010 -38.150 -3.485 ;
        RECT -37.870 -4.355 -37.635 -2.985 ;
        RECT -38.005 -4.590 -37.635 -4.355 ;
        RECT -37.405 -4.355 -37.145 1.265 ;
        RECT -36.910 -0.590 -36.510 -0.105 ;
        RECT -36.910 -2.985 -36.510 -2.500 ;
        RECT -36.275 -4.025 -35.950 0.935 ;
        RECT -35.720 -0.535 -35.290 2.125 ;
        RECT -34.705 1.255 -34.370 2.180 ;
        RECT -31.920 1.820 -31.590 2.125 ;
        RECT -32.245 1.300 -31.590 1.820 ;
        RECT -33.765 0.935 -33.050 1.160 ;
        RECT -35.060 0.640 -33.050 0.935 ;
        RECT -38.005 -5.580 -37.775 -4.590 ;
        RECT -37.405 -4.705 -36.410 -4.355 ;
        RECT -36.640 -5.235 -36.410 -4.705 ;
        RECT -35.720 -5.580 -35.290 -2.555 ;
        RECT -35.060 -4.025 -34.735 0.640 ;
        RECT -32.475 -0.065 -32.150 0.935 ;
        RECT -31.920 0.640 -31.590 1.300 ;
        RECT -30.610 1.265 -30.380 2.640 ;
        RECT -30.245 0.640 -29.920 0.935 ;
        RECT -31.920 0.190 -29.920 0.640 ;
        RECT -34.500 -2.840 -34.160 -0.250 ;
        RECT -31.920 -0.735 -31.590 0.190 ;
        RECT -30.245 -0.065 -29.920 0.190 ;
        RECT -30.710 -0.305 -30.480 -0.105 ;
        RECT -30.710 -0.965 -30.325 -0.305 ;
        RECT -30.675 -1.100 -30.325 -0.965 ;
        RECT -29.690 -0.735 -29.260 2.125 ;
        RECT -28.570 1.160 -28.145 2.360 ;
        RECT -29.030 -0.065 -28.705 0.935 ;
        RECT -27.890 0.340 -27.585 2.640 ;
        RECT -6.935 2.640 -3.910 3.030 ;
        RECT -14.315 2.610 -14.075 2.615 ;
        RECT -12.045 2.610 -11.715 2.615 ;
        RECT -14.315 2.380 -11.715 2.610 ;
        RECT -25.195 1.205 -24.640 2.120 ;
        RECT -24.970 0.585 -24.640 1.205 ;
        RECT -23.055 1.095 -22.810 2.120 ;
        RECT -20.990 1.095 -20.665 2.120 ;
        RECT -18.520 1.575 -18.190 1.945 ;
        RECT -18.520 1.470 -18.020 1.575 ;
        RECT -27.895 -0.105 -27.585 0.340 ;
        RECT -26.415 0.055 -24.640 0.585 ;
        RECT -28.470 -0.185 -27.585 -0.105 ;
        RECT -29.690 -1.470 -29.265 -0.735 ;
        RECT -28.470 -0.740 -26.480 -0.185 ;
        RECT -24.970 -0.740 -24.640 0.055 ;
        RECT -24.410 0.445 -24.085 0.930 ;
        RECT -23.055 0.640 -20.665 1.095 ;
        RECT -23.055 0.445 -22.800 0.640 ;
        RECT -24.410 0.130 -22.800 0.445 ;
        RECT -24.410 -0.070 -24.085 0.130 ;
        RECT -23.130 -0.740 -22.800 0.130 ;
        RECT -18.485 -0.735 -18.020 1.470 ;
        RECT -28.470 -0.965 -27.585 -0.740 ;
        RECT -30.710 -1.785 -27.585 -1.470 ;
        RECT -30.710 -2.165 -30.475 -1.785 ;
        RECT -32.475 -3.225 -32.150 -3.025 ;
        RECT -33.415 -4.105 -33.125 -3.360 ;
        RECT -32.850 -4.025 -32.150 -3.225 ;
        RECT -31.920 -3.240 -31.590 -2.355 ;
        RECT -30.710 -2.985 -30.480 -2.165 ;
        RECT -30.245 -3.240 -29.920 -3.025 ;
        RECT -31.920 -3.940 -29.920 -3.240 ;
        RECT -34.705 -5.270 -34.370 -4.345 ;
        RECT -33.915 -5.215 -33.530 -4.450 ;
        RECT -31.920 -4.650 -31.590 -3.940 ;
        RECT -30.245 -4.025 -29.920 -3.940 ;
        RECT -32.335 -5.080 -31.590 -4.650 ;
        RECT -31.920 -5.215 -31.590 -5.080 ;
        RECT -38.005 -5.870 -35.290 -5.580 ;
        RECT -34.135 -5.870 -33.670 -5.215 ;
        RECT -39.520 -6.405 -36.940 -6.165 ;
        RECT -29.690 -6.180 -29.260 -2.355 ;
        RECT -29.030 -4.025 -28.705 -3.025 ;
        RECT -27.890 -4.350 -27.585 -1.785 ;
        RECT -27.355 -1.815 -27.105 -0.740 ;
        RECT -14.315 -1.170 -14.075 2.380 ;
        RECT -12.965 1.615 -12.735 2.145 ;
        RECT -15.845 -1.405 -14.075 -1.170 ;
        RECT -13.730 1.265 -12.735 1.615 ;
        RECT -12.045 2.125 -11.715 2.380 ;
        RECT -27.355 -2.045 -26.455 -1.815 ;
        RECT -26.880 -2.370 -26.455 -2.045 ;
        RECT -23.745 -2.370 -23.115 -1.800 ;
        RECT -26.880 -3.895 -26.530 -2.370 ;
        RECT -26.300 -2.935 -25.830 -2.540 ;
        RECT -24.985 -3.530 -24.620 -2.780 ;
        RECT -24.200 -2.835 -23.640 -2.600 ;
        RECT -24.145 -3.245 -23.695 -2.835 ;
        RECT -22.940 -2.935 -22.490 -2.540 ;
        RECT -22.085 -3.245 -21.585 -2.830 ;
        RECT -19.510 -3.245 -19.180 -1.800 ;
        RECT -24.145 -3.575 -19.180 -3.245 ;
        RECT -18.950 -3.470 -18.625 -2.465 ;
        RECT -26.880 -4.320 -25.880 -3.895 ;
        RECT -28.570 -5.465 -27.585 -4.350 ;
        RECT -26.220 -4.595 -25.880 -4.320 ;
        RECT -22.515 -4.660 -22.130 -3.830 ;
        RECT -19.510 -4.660 -19.180 -3.575 ;
        RECT -29.690 -6.400 -29.265 -6.180 ;
        RECT -23.420 -6.265 -23.090 -5.895 ;
        RECT -23.550 -6.370 -23.090 -6.265 ;
        RECT -37.655 -6.430 -36.940 -6.405 ;
        RECT -37.180 -6.440 -36.940 -6.430 ;
        RECT -46.570 -7.450 -44.850 -6.750 ;
        RECT -44.620 -7.200 -42.230 -6.745 ;
        RECT -46.570 -7.650 -42.780 -7.450 ;
        RECT -47.225 -7.825 -46.780 -7.750 ;
        RECT -60.855 -8.300 -60.270 -8.195 ;
        RECT -60.855 -8.575 -57.915 -8.300 ;
        RECT -47.040 -8.570 -46.780 -7.825 ;
        RECT -45.180 -7.910 -42.780 -7.650 ;
        RECT -42.485 -7.710 -42.230 -7.200 ;
        RECT -81.820 -9.350 -81.590 -9.150 ;
        RECT -83.520 -9.605 -83.270 -9.390 ;
        RECT -83.595 -10.390 -83.270 -9.605 ;
        RECT -82.380 -9.950 -82.055 -9.390 ;
        RECT -80.710 -9.950 -80.380 -8.720 ;
        RECT -78.925 -8.950 -75.865 -8.720 ;
        RECT -72.905 -9.180 -72.565 -8.720 ;
        RECT -82.380 -10.390 -80.380 -9.950 ;
        RECT -84.530 -10.970 -83.675 -10.720 ;
        RECT -84.015 -11.515 -83.675 -10.970 ;
        RECT -81.920 -11.335 -81.620 -10.720 ;
        RECT -81.920 -12.900 -81.690 -11.335 ;
        RECT -80.710 -11.580 -80.380 -10.390 ;
        RECT -80.150 -10.405 -79.825 -9.390 ;
        RECT -75.680 -9.410 -72.565 -9.180 ;
        RECT -78.245 -9.930 -77.420 -9.700 ;
        RECT -75.680 -9.755 -75.340 -9.410 ;
        RECT -77.690 -10.575 -77.420 -9.930 ;
        RECT -74.455 -10.015 -74.050 -9.640 ;
        RECT -76.805 -10.285 -74.050 -10.015 ;
        RECT -73.770 -10.045 -73.145 -9.815 ;
        RECT -73.770 -10.575 -73.540 -10.045 ;
        RECT -72.850 -10.370 -72.565 -9.410 ;
        RECT -77.690 -10.845 -73.540 -10.575 ;
        RECT -73.310 -10.605 -72.565 -10.370 ;
        RECT -73.310 -11.135 -73.080 -10.605 ;
        RECT -69.330 -10.720 -68.930 -10.290 ;
        RECT -74.015 -11.405 -73.080 -11.135 ;
        RECT -69.235 -12.430 -68.930 -10.720 ;
        RECT -68.700 -11.470 -68.345 -9.710 ;
        RECT -68.115 -10.900 -67.810 -9.710 ;
        RECT -66.680 -10.900 -66.350 -9.640 ;
        RECT -68.115 -11.240 -66.350 -10.900 ;
        RECT -68.700 -11.790 -67.275 -11.470 ;
        RECT -67.555 -12.490 -67.275 -11.790 ;
        RECT -66.680 -12.500 -66.350 -11.240 ;
        RECT -66.120 -11.310 -65.795 -10.310 ;
        RECT -60.855 -10.720 -60.615 -8.575 ;
        RECT -60.385 -9.350 -60.085 -8.810 ;
        RECT -59.845 -9.605 -59.595 -9.390 ;
        RECT -59.920 -10.390 -59.595 -9.605 ;
        RECT -60.855 -10.970 -60.000 -10.720 ;
        RECT -60.340 -11.515 -60.000 -10.970 ;
        RECT -59.365 -12.030 -58.935 -8.810 ;
        RECT -58.255 -9.150 -57.915 -8.575 ;
        RECT -42.485 -8.580 -42.155 -7.710 ;
        RECT -23.550 -7.750 -23.125 -6.370 ;
        RECT -22.895 -6.750 -22.385 -6.600 ;
        RECT -20.945 -6.745 -20.620 -5.720 ;
        RECT -18.800 -6.745 -18.555 -5.720 ;
        RECT -15.845 -6.165 -15.585 -1.405 ;
        RECT -14.955 -1.945 -14.395 -1.675 ;
        RECT -15.350 -5.215 -15.020 -2.355 ;
        RECT -14.230 -2.780 -14.000 -2.125 ;
        RECT -14.230 -2.985 -13.960 -2.780 ;
        RECT -14.195 -4.355 -13.960 -2.985 ;
        RECT -14.330 -4.590 -13.960 -4.355 ;
        RECT -13.730 -4.355 -13.470 1.265 ;
        RECT -13.235 -0.590 -12.835 -0.105 ;
        RECT -12.045 -0.535 -11.615 2.125 ;
        RECT -11.030 1.255 -10.695 2.180 ;
        RECT -8.245 1.820 -7.915 2.125 ;
        RECT -8.570 1.300 -7.915 1.820 ;
        RECT -10.090 0.935 -9.375 1.160 ;
        RECT -11.385 0.640 -9.375 0.935 ;
        RECT -8.245 0.640 -7.915 1.300 ;
        RECT -6.935 1.265 -6.705 2.640 ;
        RECT -6.570 0.640 -6.245 0.935 ;
        RECT -13.235 -2.985 -12.835 -2.500 ;
        RECT -14.330 -5.580 -14.100 -4.590 ;
        RECT -13.730 -4.705 -12.735 -4.355 ;
        RECT -12.965 -5.235 -12.735 -4.705 ;
        RECT -12.045 -5.580 -11.615 -2.555 ;
        RECT -11.385 -4.025 -11.060 0.640 ;
        RECT -8.245 0.190 -6.245 0.640 ;
        RECT -10.825 -2.840 -10.485 -0.250 ;
        RECT -8.245 -0.735 -7.915 0.190 ;
        RECT -6.570 -0.065 -6.245 0.190 ;
        RECT -7.035 -0.305 -6.805 -0.105 ;
        RECT -7.035 -0.965 -6.650 -0.305 ;
        RECT -7.000 -1.100 -6.650 -0.965 ;
        RECT -6.015 -0.735 -5.585 2.125 ;
        RECT -4.895 1.160 -4.470 2.360 ;
        RECT -4.215 0.340 -3.910 2.640 ;
        RECT -1.520 1.205 -0.965 2.120 ;
        RECT -1.295 0.585 -0.965 1.205 ;
        RECT 0.620 1.095 0.865 2.120 ;
        RECT 2.685 1.095 3.010 2.120 ;
        RECT 5.155 1.575 5.485 1.945 ;
        RECT 5.155 1.470 5.655 1.575 ;
        RECT -4.220 -0.105 -3.910 0.340 ;
        RECT -2.740 0.055 -0.965 0.585 ;
        RECT -4.795 -0.185 -3.910 -0.105 ;
        RECT -6.015 -1.470 -5.590 -0.735 ;
        RECT -4.795 -0.740 -2.805 -0.185 ;
        RECT -1.295 -0.740 -0.965 0.055 ;
        RECT -0.735 0.445 -0.410 0.930 ;
        RECT 0.620 0.640 3.010 1.095 ;
        RECT 0.620 0.445 0.875 0.640 ;
        RECT -0.735 0.130 0.875 0.445 ;
        RECT -0.735 -0.070 -0.410 0.130 ;
        RECT 0.545 -0.740 0.875 0.130 ;
        RECT 5.190 -0.735 5.655 1.470 ;
        RECT -4.795 -0.965 -3.910 -0.740 ;
        RECT -7.035 -1.785 -3.910 -1.470 ;
        RECT -7.035 -2.165 -6.800 -1.785 ;
        RECT -8.245 -3.240 -7.915 -2.355 ;
        RECT -7.035 -2.985 -6.805 -2.165 ;
        RECT -6.570 -3.240 -6.245 -3.025 ;
        RECT -9.740 -4.105 -9.450 -3.360 ;
        RECT -8.245 -3.940 -6.245 -3.240 ;
        RECT -11.030 -5.270 -10.695 -4.345 ;
        RECT -10.240 -5.215 -9.855 -4.450 ;
        RECT -8.245 -4.650 -7.915 -3.940 ;
        RECT -6.570 -4.025 -6.245 -3.940 ;
        RECT -8.660 -5.080 -7.915 -4.650 ;
        RECT -8.245 -5.215 -7.915 -5.080 ;
        RECT -14.330 -5.870 -11.615 -5.580 ;
        RECT -10.460 -5.870 -9.995 -5.215 ;
        RECT -15.845 -6.405 -13.265 -6.165 ;
        RECT -6.015 -6.180 -5.585 -2.355 ;
        RECT -4.215 -4.350 -3.910 -1.785 ;
        RECT -3.680 -1.815 -3.430 -0.740 ;
        RECT -3.680 -2.045 -2.780 -1.815 ;
        RECT -3.205 -2.370 -2.780 -2.045 ;
        RECT -0.070 -2.370 0.560 -1.800 ;
        RECT -3.205 -3.895 -2.855 -2.370 ;
        RECT -2.625 -2.935 -2.155 -2.540 ;
        RECT -1.310 -3.530 -0.945 -2.780 ;
        RECT -0.525 -2.835 0.035 -2.600 ;
        RECT -0.470 -3.245 -0.020 -2.835 ;
        RECT 0.735 -2.935 1.185 -2.540 ;
        RECT 1.590 -3.245 2.090 -2.830 ;
        RECT 4.165 -3.245 4.495 -1.800 ;
        RECT -0.470 -3.575 4.495 -3.245 ;
        RECT 4.725 -3.470 5.050 -2.465 ;
        RECT -3.205 -4.320 -2.205 -3.895 ;
        RECT -4.895 -5.465 -3.910 -4.350 ;
        RECT -2.545 -4.595 -2.205 -4.320 ;
        RECT 1.160 -4.660 1.545 -3.830 ;
        RECT 4.165 -4.660 4.495 -3.575 ;
        RECT -6.015 -6.400 -5.590 -6.180 ;
        RECT 0.255 -6.265 0.585 -5.895 ;
        RECT 0.125 -6.370 0.585 -6.265 ;
        RECT -13.980 -6.430 -13.265 -6.405 ;
        RECT -13.505 -6.440 -13.265 -6.430 ;
        RECT -22.895 -7.450 -21.175 -6.750 ;
        RECT -20.945 -7.200 -18.555 -6.745 ;
        RECT -22.895 -7.650 -19.105 -7.450 ;
        RECT -23.550 -7.825 -23.105 -7.750 ;
        RECT -37.180 -8.300 -36.595 -8.195 ;
        RECT -37.180 -8.575 -34.240 -8.300 ;
        RECT -23.365 -8.570 -23.105 -7.825 ;
        RECT -21.505 -7.910 -19.105 -7.650 ;
        RECT -18.810 -7.710 -18.555 -7.200 ;
        RECT -16.160 -7.525 -8.810 -7.235 ;
        RECT -58.145 -9.350 -57.915 -9.150 ;
        RECT -58.705 -9.950 -58.380 -9.390 ;
        RECT -57.035 -9.950 -56.705 -8.720 ;
        RECT -55.250 -8.950 -52.190 -8.720 ;
        RECT -49.230 -9.180 -48.890 -8.720 ;
        RECT -58.705 -10.390 -56.705 -9.950 ;
        RECT -61.150 -12.525 -58.935 -12.030 ;
        RECT -58.245 -11.335 -57.945 -10.720 ;
        RECT -85.250 -13.290 -84.640 -12.910 ;
        RECT -82.870 -13.130 -81.690 -12.900 ;
        RECT -77.960 -13.040 -74.935 -12.650 ;
        RECT -58.245 -12.900 -58.015 -11.335 ;
        RECT -57.035 -11.580 -56.705 -10.390 ;
        RECT -56.475 -10.405 -56.150 -9.390 ;
        RECT -55.140 -9.410 -53.540 -9.180 ;
        RECT -52.005 -9.410 -48.890 -9.180 ;
        RECT -55.140 -10.170 -54.850 -9.410 ;
        RECT -54.570 -9.930 -53.745 -9.700 ;
        RECT -52.005 -9.755 -51.665 -9.410 ;
        RECT -55.140 -10.405 -54.305 -10.170 ;
        RECT -54.580 -11.135 -54.305 -10.405 ;
        RECT -54.015 -10.575 -53.745 -9.930 ;
        RECT -50.780 -10.015 -50.375 -9.640 ;
        RECT -53.130 -10.285 -50.375 -10.015 ;
        RECT -50.095 -10.045 -49.470 -9.815 ;
        RECT -50.095 -10.575 -49.865 -10.045 ;
        RECT -49.175 -10.370 -48.890 -9.410 ;
        RECT -54.015 -10.845 -49.865 -10.575 ;
        RECT -49.635 -10.605 -48.890 -10.370 ;
        RECT -49.635 -11.135 -49.405 -10.605 ;
        RECT -45.655 -10.720 -45.255 -10.290 ;
        RECT -54.580 -11.405 -51.865 -11.135 ;
        RECT -50.340 -11.405 -49.405 -11.135 ;
        RECT -45.560 -12.430 -45.255 -10.720 ;
        RECT -45.025 -11.470 -44.670 -9.710 ;
        RECT -44.440 -10.900 -44.135 -9.710 ;
        RECT -43.005 -10.900 -42.675 -9.640 ;
        RECT -44.440 -11.240 -42.675 -10.900 ;
        RECT -45.025 -11.790 -43.600 -11.470 ;
        RECT -43.880 -12.490 -43.600 -11.790 ;
        RECT -43.005 -12.500 -42.675 -11.240 ;
        RECT -42.445 -11.310 -42.120 -10.310 ;
        RECT -37.180 -10.720 -36.940 -8.575 ;
        RECT -36.710 -9.350 -36.410 -8.810 ;
        RECT -34.580 -9.150 -34.240 -8.575 ;
        RECT -18.810 -8.580 -18.480 -7.710 ;
        RECT 0.125 -7.750 0.550 -6.370 ;
        RECT 0.780 -6.750 1.290 -6.600 ;
        RECT 2.730 -6.745 3.055 -5.720 ;
        RECT 4.875 -6.745 5.120 -5.720 ;
        RECT 0.780 -7.450 2.500 -6.750 ;
        RECT 2.730 -7.200 5.120 -6.745 ;
        RECT 0.780 -7.650 4.570 -7.450 ;
        RECT 0.125 -7.825 0.570 -7.750 ;
        RECT -13.505 -8.300 -12.920 -8.195 ;
        RECT -13.505 -8.575 -10.565 -8.300 ;
        RECT 0.310 -8.570 0.570 -7.825 ;
        RECT 2.170 -7.910 4.570 -7.650 ;
        RECT 4.865 -7.710 5.120 -7.200 ;
        RECT -34.470 -9.350 -34.240 -9.150 ;
        RECT -36.170 -9.605 -35.920 -9.390 ;
        RECT -36.245 -10.390 -35.920 -9.605 ;
        RECT -35.030 -9.950 -34.705 -9.390 ;
        RECT -33.360 -9.950 -33.030 -8.720 ;
        RECT -31.575 -8.950 -28.515 -8.720 ;
        RECT -25.555 -9.180 -25.215 -8.720 ;
        RECT -35.030 -10.390 -33.030 -9.950 ;
        RECT -37.180 -10.970 -36.325 -10.720 ;
        RECT -36.665 -11.515 -36.325 -10.970 ;
        RECT -34.570 -11.335 -34.270 -10.720 ;
        RECT -85.250 -16.865 -84.990 -13.290 ;
        RECT -83.990 -14.065 -83.760 -13.535 ;
        RECT -82.870 -13.555 -82.640 -13.130 ;
        RECT -86.445 -17.105 -84.990 -16.865 ;
        RECT -84.755 -14.415 -83.760 -14.065 ;
        RECT -86.445 -18.035 -86.215 -17.105 ;
        RECT -85.980 -17.625 -85.420 -17.355 ;
        RECT -86.445 -18.235 -86.045 -18.035 ;
        RECT -86.375 -20.895 -86.045 -18.235 ;
        RECT -85.255 -18.460 -85.025 -17.805 ;
        RECT -85.255 -18.665 -84.985 -18.460 ;
        RECT -85.800 -19.690 -85.500 -19.165 ;
        RECT -85.220 -20.035 -84.985 -18.665 ;
        RECT -85.355 -20.270 -84.985 -20.035 ;
        RECT -84.755 -20.035 -84.495 -14.415 ;
        RECT -84.260 -16.270 -83.860 -15.785 ;
        RECT -84.260 -18.665 -83.860 -18.180 ;
        RECT -83.625 -19.705 -83.300 -14.745 ;
        RECT -83.070 -16.215 -82.640 -13.555 ;
        RECT -82.055 -14.425 -81.720 -13.500 ;
        RECT -79.270 -13.860 -78.940 -13.555 ;
        RECT -79.595 -14.380 -78.940 -13.860 ;
        RECT -81.115 -14.745 -80.400 -14.520 ;
        RECT -82.410 -15.040 -80.400 -14.745 ;
        RECT -85.355 -21.260 -85.125 -20.270 ;
        RECT -84.755 -20.385 -83.760 -20.035 ;
        RECT -83.990 -20.915 -83.760 -20.385 ;
        RECT -83.070 -21.260 -82.640 -18.235 ;
        RECT -82.410 -19.705 -82.085 -15.040 ;
        RECT -79.825 -15.745 -79.500 -14.745 ;
        RECT -79.270 -15.040 -78.940 -14.380 ;
        RECT -77.960 -14.415 -77.730 -13.040 ;
        RECT -77.595 -15.040 -77.270 -14.745 ;
        RECT -79.270 -15.490 -77.270 -15.040 ;
        RECT -81.850 -18.520 -81.510 -15.930 ;
        RECT -79.270 -16.415 -78.940 -15.490 ;
        RECT -77.595 -15.745 -77.270 -15.490 ;
        RECT -78.060 -15.985 -77.830 -15.785 ;
        RECT -78.060 -16.645 -77.675 -15.985 ;
        RECT -78.025 -16.780 -77.675 -16.645 ;
        RECT -77.040 -16.415 -76.610 -13.555 ;
        RECT -75.920 -14.520 -75.495 -13.320 ;
        RECT -76.380 -15.745 -76.055 -14.745 ;
        RECT -75.240 -15.340 -74.935 -13.040 ;
        RECT -61.575 -13.290 -60.965 -12.910 ;
        RECT -59.195 -13.130 -58.015 -12.900 ;
        RECT -54.285 -13.040 -51.260 -12.650 ;
        RECT -34.570 -12.900 -34.340 -11.335 ;
        RECT -33.360 -11.580 -33.030 -10.390 ;
        RECT -32.800 -10.405 -32.475 -9.390 ;
        RECT -28.330 -9.410 -25.215 -9.180 ;
        RECT -30.895 -9.930 -30.070 -9.700 ;
        RECT -28.330 -9.755 -27.990 -9.410 ;
        RECT -30.340 -10.575 -30.070 -9.930 ;
        RECT -27.105 -10.015 -26.700 -9.640 ;
        RECT -29.455 -10.285 -26.700 -10.015 ;
        RECT -26.420 -10.045 -25.795 -9.815 ;
        RECT -26.420 -10.575 -26.190 -10.045 ;
        RECT -25.500 -10.370 -25.215 -9.410 ;
        RECT -30.340 -10.845 -26.190 -10.575 ;
        RECT -25.960 -10.605 -25.215 -10.370 ;
        RECT -25.960 -11.135 -25.730 -10.605 ;
        RECT -21.980 -10.720 -21.580 -10.290 ;
        RECT -26.665 -11.405 -25.730 -11.135 ;
        RECT -21.885 -12.430 -21.580 -10.720 ;
        RECT -21.350 -11.470 -20.995 -9.710 ;
        RECT -20.765 -10.900 -20.460 -9.710 ;
        RECT -19.330 -10.900 -19.000 -9.640 ;
        RECT -20.765 -11.240 -19.000 -10.900 ;
        RECT -21.350 -11.790 -19.925 -11.470 ;
        RECT -20.205 -12.490 -19.925 -11.790 ;
        RECT -19.330 -12.500 -19.000 -11.240 ;
        RECT -18.770 -11.310 -18.445 -10.310 ;
        RECT -13.505 -10.720 -13.265 -8.575 ;
        RECT -13.035 -9.350 -12.735 -8.810 ;
        RECT -12.495 -9.605 -12.245 -9.390 ;
        RECT -12.570 -10.390 -12.245 -9.605 ;
        RECT -13.505 -10.970 -12.650 -10.720 ;
        RECT -12.990 -11.515 -12.650 -10.970 ;
        RECT -12.015 -12.030 -11.585 -8.810 ;
        RECT -10.905 -9.150 -10.565 -8.575 ;
        RECT 4.865 -8.580 5.195 -7.710 ;
        RECT -10.795 -9.350 -10.565 -9.150 ;
        RECT -11.355 -9.950 -11.030 -9.390 ;
        RECT -9.685 -9.950 -9.355 -8.720 ;
        RECT -7.900 -8.950 -4.840 -8.720 ;
        RECT -1.880 -9.180 -1.540 -8.720 ;
        RECT -11.355 -10.390 -9.355 -9.950 ;
        RECT -13.800 -12.525 -11.585 -12.030 ;
        RECT -10.895 -11.335 -10.595 -10.720 ;
        RECT -72.545 -14.475 -71.990 -13.560 ;
        RECT -72.320 -15.095 -71.990 -14.475 ;
        RECT -70.405 -14.585 -70.160 -13.560 ;
        RECT -68.340 -14.585 -68.015 -13.560 ;
        RECT -65.870 -14.105 -65.540 -13.735 ;
        RECT -65.870 -14.210 -65.370 -14.105 ;
        RECT -75.245 -15.785 -74.935 -15.340 ;
        RECT -73.765 -15.625 -71.990 -15.095 ;
        RECT -75.820 -15.865 -74.935 -15.785 ;
        RECT -77.040 -17.150 -76.615 -16.415 ;
        RECT -75.820 -16.420 -73.830 -15.865 ;
        RECT -72.320 -16.420 -71.990 -15.625 ;
        RECT -71.760 -15.235 -71.435 -14.750 ;
        RECT -70.405 -15.040 -68.015 -14.585 ;
        RECT -70.405 -15.235 -70.150 -15.040 ;
        RECT -71.760 -15.550 -70.150 -15.235 ;
        RECT -71.760 -15.750 -71.435 -15.550 ;
        RECT -70.480 -16.420 -70.150 -15.550 ;
        RECT -65.835 -16.415 -65.370 -14.210 ;
        RECT -75.820 -16.645 -74.935 -16.420 ;
        RECT -78.060 -17.465 -74.935 -17.150 ;
        RECT -78.060 -17.845 -77.825 -17.465 ;
        RECT -79.825 -18.905 -79.500 -18.705 ;
        RECT -80.765 -19.785 -80.475 -19.040 ;
        RECT -80.200 -19.705 -79.500 -18.905 ;
        RECT -79.270 -18.920 -78.940 -18.035 ;
        RECT -78.060 -18.665 -77.830 -17.845 ;
        RECT -77.595 -18.920 -77.270 -18.705 ;
        RECT -79.270 -19.620 -77.270 -18.920 ;
        RECT -82.055 -20.950 -81.720 -20.025 ;
        RECT -81.265 -20.895 -80.880 -20.130 ;
        RECT -79.270 -20.330 -78.940 -19.620 ;
        RECT -77.595 -19.705 -77.270 -19.620 ;
        RECT -76.380 -19.705 -76.055 -18.705 ;
        RECT -75.240 -20.030 -74.935 -17.465 ;
        RECT -74.705 -17.495 -74.455 -16.420 ;
        RECT -61.575 -16.865 -61.315 -13.290 ;
        RECT -60.315 -14.065 -60.085 -13.535 ;
        RECT -59.195 -13.555 -58.965 -13.130 ;
        RECT -62.770 -17.105 -61.315 -16.865 ;
        RECT -61.080 -14.415 -60.085 -14.065 ;
        RECT -74.705 -17.725 -73.805 -17.495 ;
        RECT -74.230 -18.050 -73.805 -17.725 ;
        RECT -71.095 -18.050 -70.465 -17.480 ;
        RECT -74.230 -19.575 -73.880 -18.050 ;
        RECT -73.650 -18.615 -73.180 -18.220 ;
        RECT -72.335 -19.210 -71.970 -18.460 ;
        RECT -71.550 -18.515 -70.990 -18.280 ;
        RECT -71.495 -18.925 -71.045 -18.515 ;
        RECT -70.290 -18.615 -69.840 -18.220 ;
        RECT -69.435 -18.925 -68.935 -18.510 ;
        RECT -66.860 -18.925 -66.530 -17.480 ;
        RECT -62.770 -18.035 -62.540 -17.105 ;
        RECT -62.305 -17.625 -61.745 -17.355 ;
        RECT -71.495 -19.255 -66.530 -18.925 ;
        RECT -66.300 -19.150 -65.975 -18.145 ;
        RECT -62.770 -18.235 -62.370 -18.035 ;
        RECT -74.230 -20.000 -73.230 -19.575 ;
        RECT -79.685 -20.760 -78.940 -20.330 ;
        RECT -79.270 -20.895 -78.940 -20.760 ;
        RECT -85.355 -21.550 -82.640 -21.260 ;
        RECT -81.485 -21.550 -81.020 -20.895 ;
        RECT -75.920 -21.145 -74.935 -20.030 ;
        RECT -73.570 -20.275 -73.230 -20.000 ;
        RECT -69.865 -20.340 -69.480 -19.510 ;
        RECT -66.860 -20.340 -66.530 -19.255 ;
        RECT -62.700 -20.895 -62.370 -18.235 ;
        RECT -61.580 -18.460 -61.350 -17.805 ;
        RECT -61.580 -18.665 -61.310 -18.460 ;
        RECT -62.125 -19.690 -61.825 -19.165 ;
        RECT -61.545 -20.035 -61.310 -18.665 ;
        RECT -61.680 -20.270 -61.310 -20.035 ;
        RECT -61.080 -20.035 -60.820 -14.415 ;
        RECT -60.585 -16.270 -60.185 -15.785 ;
        RECT -60.585 -18.665 -60.185 -18.180 ;
        RECT -59.950 -19.705 -59.625 -14.745 ;
        RECT -59.395 -16.215 -58.965 -13.555 ;
        RECT -58.380 -14.425 -58.045 -13.500 ;
        RECT -55.595 -13.860 -55.265 -13.555 ;
        RECT -55.920 -14.380 -55.265 -13.860 ;
        RECT -57.440 -14.745 -56.725 -14.520 ;
        RECT -58.735 -15.040 -56.725 -14.745 ;
        RECT -61.680 -21.260 -61.450 -20.270 ;
        RECT -61.080 -20.385 -60.085 -20.035 ;
        RECT -60.315 -20.915 -60.085 -20.385 ;
        RECT -59.395 -21.260 -58.965 -18.235 ;
        RECT -58.735 -19.705 -58.410 -15.040 ;
        RECT -56.150 -15.745 -55.825 -14.745 ;
        RECT -55.595 -15.040 -55.265 -14.380 ;
        RECT -54.285 -14.415 -54.055 -13.040 ;
        RECT -53.920 -15.040 -53.595 -14.745 ;
        RECT -55.595 -15.490 -53.595 -15.040 ;
        RECT -58.175 -18.520 -57.835 -15.930 ;
        RECT -55.595 -16.415 -55.265 -15.490 ;
        RECT -53.920 -15.745 -53.595 -15.490 ;
        RECT -54.385 -15.985 -54.155 -15.785 ;
        RECT -54.385 -16.645 -54.000 -15.985 ;
        RECT -54.350 -16.780 -54.000 -16.645 ;
        RECT -53.365 -16.415 -52.935 -13.555 ;
        RECT -52.245 -14.520 -51.820 -13.320 ;
        RECT -52.705 -15.745 -52.380 -14.745 ;
        RECT -51.565 -15.340 -51.260 -13.040 ;
        RECT -37.900 -13.290 -37.290 -12.910 ;
        RECT -35.520 -13.130 -34.340 -12.900 ;
        RECT -30.610 -13.040 -27.585 -12.650 ;
        RECT -10.895 -12.900 -10.665 -11.335 ;
        RECT -9.685 -11.580 -9.355 -10.390 ;
        RECT -9.125 -10.405 -8.800 -9.390 ;
        RECT -7.790 -9.410 -6.190 -9.180 ;
        RECT -4.655 -9.410 -1.540 -9.180 ;
        RECT -7.790 -10.170 -7.500 -9.410 ;
        RECT -7.220 -9.930 -6.395 -9.700 ;
        RECT -4.655 -9.755 -4.315 -9.410 ;
        RECT -7.790 -10.405 -6.955 -10.170 ;
        RECT -7.230 -11.135 -6.955 -10.405 ;
        RECT -6.665 -10.575 -6.395 -9.930 ;
        RECT -3.430 -10.015 -3.025 -9.640 ;
        RECT -5.780 -10.285 -3.025 -10.015 ;
        RECT -2.745 -10.045 -2.120 -9.815 ;
        RECT -2.745 -10.575 -2.515 -10.045 ;
        RECT -1.825 -10.370 -1.540 -9.410 ;
        RECT -6.665 -10.845 -2.515 -10.575 ;
        RECT -2.285 -10.605 -1.540 -10.370 ;
        RECT -2.285 -11.135 -2.055 -10.605 ;
        RECT 1.695 -10.720 2.095 -10.290 ;
        RECT -7.230 -11.405 -4.515 -11.135 ;
        RECT -2.990 -11.405 -2.055 -11.135 ;
        RECT 1.790 -12.430 2.095 -10.720 ;
        RECT 2.325 -11.470 2.680 -9.710 ;
        RECT 2.910 -10.900 3.215 -9.710 ;
        RECT 4.345 -10.900 4.675 -9.640 ;
        RECT 2.910 -11.240 4.675 -10.900 ;
        RECT 2.325 -11.790 3.750 -11.470 ;
        RECT 3.470 -12.490 3.750 -11.790 ;
        RECT 4.345 -12.500 4.675 -11.240 ;
        RECT 4.905 -11.310 5.230 -10.310 ;
        RECT -48.870 -14.475 -48.315 -13.560 ;
        RECT -48.645 -15.095 -48.315 -14.475 ;
        RECT -46.730 -14.585 -46.485 -13.560 ;
        RECT -44.665 -14.585 -44.340 -13.560 ;
        RECT -42.195 -14.105 -41.865 -13.735 ;
        RECT -42.195 -14.210 -41.695 -14.105 ;
        RECT -51.570 -15.785 -51.260 -15.340 ;
        RECT -50.090 -15.625 -48.315 -15.095 ;
        RECT -52.145 -15.865 -51.260 -15.785 ;
        RECT -53.365 -17.150 -52.940 -16.415 ;
        RECT -52.145 -16.420 -50.155 -15.865 ;
        RECT -48.645 -16.420 -48.315 -15.625 ;
        RECT -48.085 -15.235 -47.760 -14.750 ;
        RECT -46.730 -15.040 -44.340 -14.585 ;
        RECT -46.730 -15.235 -46.475 -15.040 ;
        RECT -48.085 -15.550 -46.475 -15.235 ;
        RECT -48.085 -15.750 -47.760 -15.550 ;
        RECT -46.805 -16.420 -46.475 -15.550 ;
        RECT -42.160 -16.415 -41.695 -14.210 ;
        RECT -52.145 -16.645 -51.260 -16.420 ;
        RECT -54.385 -17.465 -51.260 -17.150 ;
        RECT -54.385 -17.845 -54.150 -17.465 ;
        RECT -56.150 -18.905 -55.825 -18.705 ;
        RECT -57.090 -19.785 -56.800 -19.040 ;
        RECT -56.525 -19.705 -55.825 -18.905 ;
        RECT -55.595 -18.920 -55.265 -18.035 ;
        RECT -54.385 -18.665 -54.155 -17.845 ;
        RECT -53.920 -18.920 -53.595 -18.705 ;
        RECT -55.595 -19.620 -53.595 -18.920 ;
        RECT -58.380 -20.950 -58.045 -20.025 ;
        RECT -57.590 -20.895 -57.205 -20.130 ;
        RECT -55.595 -20.330 -55.265 -19.620 ;
        RECT -53.920 -19.705 -53.595 -19.620 ;
        RECT -52.705 -19.705 -52.380 -18.705 ;
        RECT -51.565 -20.030 -51.260 -17.465 ;
        RECT -51.030 -17.495 -50.780 -16.420 ;
        RECT -37.900 -16.865 -37.640 -13.290 ;
        RECT -36.640 -14.065 -36.410 -13.535 ;
        RECT -35.520 -13.555 -35.290 -13.130 ;
        RECT -39.095 -17.105 -37.640 -16.865 ;
        RECT -37.405 -14.415 -36.410 -14.065 ;
        RECT -51.030 -17.725 -50.130 -17.495 ;
        RECT -50.555 -18.050 -50.130 -17.725 ;
        RECT -47.420 -18.050 -46.790 -17.480 ;
        RECT -50.555 -19.575 -50.205 -18.050 ;
        RECT -49.975 -18.615 -49.505 -18.220 ;
        RECT -48.660 -19.210 -48.295 -18.460 ;
        RECT -47.875 -18.515 -47.315 -18.280 ;
        RECT -47.820 -18.925 -47.370 -18.515 ;
        RECT -46.615 -18.615 -46.165 -18.220 ;
        RECT -45.760 -18.925 -45.260 -18.510 ;
        RECT -43.185 -18.925 -42.855 -17.480 ;
        RECT -39.095 -18.035 -38.865 -17.105 ;
        RECT -38.630 -17.625 -38.070 -17.355 ;
        RECT -47.820 -19.255 -42.855 -18.925 ;
        RECT -42.625 -19.150 -42.300 -18.145 ;
        RECT -39.095 -18.235 -38.695 -18.035 ;
        RECT -50.555 -20.000 -49.555 -19.575 ;
        RECT -56.010 -20.760 -55.265 -20.330 ;
        RECT -55.595 -20.895 -55.265 -20.760 ;
        RECT -61.680 -21.550 -58.965 -21.260 ;
        RECT -57.810 -21.550 -57.345 -20.895 ;
        RECT -52.245 -21.145 -51.260 -20.030 ;
        RECT -49.895 -20.275 -49.555 -20.000 ;
        RECT -46.190 -20.340 -45.805 -19.510 ;
        RECT -43.185 -20.340 -42.855 -19.255 ;
        RECT -39.025 -20.895 -38.695 -18.235 ;
        RECT -37.905 -18.460 -37.675 -17.805 ;
        RECT -37.905 -18.665 -37.635 -18.460 ;
        RECT -38.450 -19.690 -38.150 -19.165 ;
        RECT -37.870 -20.035 -37.635 -18.665 ;
        RECT -38.005 -20.270 -37.635 -20.035 ;
        RECT -37.405 -20.035 -37.145 -14.415 ;
        RECT -36.910 -16.270 -36.510 -15.785 ;
        RECT -36.910 -18.665 -36.510 -18.180 ;
        RECT -36.275 -19.705 -35.950 -14.745 ;
        RECT -35.720 -16.215 -35.290 -13.555 ;
        RECT -34.705 -14.425 -34.370 -13.500 ;
        RECT -31.920 -13.860 -31.590 -13.555 ;
        RECT -32.245 -14.380 -31.590 -13.860 ;
        RECT -33.765 -14.745 -33.050 -14.520 ;
        RECT -35.060 -15.040 -33.050 -14.745 ;
        RECT -38.005 -21.260 -37.775 -20.270 ;
        RECT -37.405 -20.385 -36.410 -20.035 ;
        RECT -36.640 -20.915 -36.410 -20.385 ;
        RECT -35.720 -21.260 -35.290 -18.235 ;
        RECT -35.060 -19.705 -34.735 -15.040 ;
        RECT -32.475 -15.745 -32.150 -14.745 ;
        RECT -31.920 -15.040 -31.590 -14.380 ;
        RECT -30.610 -14.415 -30.380 -13.040 ;
        RECT -30.245 -15.040 -29.920 -14.745 ;
        RECT -31.920 -15.490 -29.920 -15.040 ;
        RECT -34.500 -18.520 -34.160 -15.930 ;
        RECT -31.920 -16.415 -31.590 -15.490 ;
        RECT -30.245 -15.745 -29.920 -15.490 ;
        RECT -30.710 -15.985 -30.480 -15.785 ;
        RECT -30.710 -16.645 -30.325 -15.985 ;
        RECT -30.675 -16.780 -30.325 -16.645 ;
        RECT -29.690 -16.415 -29.260 -13.555 ;
        RECT -28.570 -14.520 -28.145 -13.320 ;
        RECT -29.030 -15.745 -28.705 -14.745 ;
        RECT -27.890 -15.340 -27.585 -13.040 ;
        RECT -14.225 -13.290 -13.615 -12.910 ;
        RECT -11.845 -13.130 -10.665 -12.900 ;
        RECT -6.935 -13.040 -3.910 -12.650 ;
        RECT -25.195 -14.475 -24.640 -13.560 ;
        RECT -24.970 -15.095 -24.640 -14.475 ;
        RECT -23.055 -14.585 -22.810 -13.560 ;
        RECT -20.990 -14.585 -20.665 -13.560 ;
        RECT -18.520 -14.105 -18.190 -13.735 ;
        RECT -18.520 -14.210 -18.020 -14.105 ;
        RECT -27.895 -15.785 -27.585 -15.340 ;
        RECT -26.415 -15.625 -24.640 -15.095 ;
        RECT -28.470 -15.865 -27.585 -15.785 ;
        RECT -29.690 -17.150 -29.265 -16.415 ;
        RECT -28.470 -16.420 -26.480 -15.865 ;
        RECT -24.970 -16.420 -24.640 -15.625 ;
        RECT -24.410 -15.235 -24.085 -14.750 ;
        RECT -23.055 -15.040 -20.665 -14.585 ;
        RECT -23.055 -15.235 -22.800 -15.040 ;
        RECT -24.410 -15.550 -22.800 -15.235 ;
        RECT -24.410 -15.750 -24.085 -15.550 ;
        RECT -23.130 -16.420 -22.800 -15.550 ;
        RECT -18.485 -16.415 -18.020 -14.210 ;
        RECT -28.470 -16.645 -27.585 -16.420 ;
        RECT -30.710 -17.465 -27.585 -17.150 ;
        RECT -30.710 -17.845 -30.475 -17.465 ;
        RECT -32.475 -18.905 -32.150 -18.705 ;
        RECT -33.415 -19.785 -33.125 -19.040 ;
        RECT -32.850 -19.705 -32.150 -18.905 ;
        RECT -31.920 -18.920 -31.590 -18.035 ;
        RECT -30.710 -18.665 -30.480 -17.845 ;
        RECT -30.245 -18.920 -29.920 -18.705 ;
        RECT -31.920 -19.620 -29.920 -18.920 ;
        RECT -34.705 -20.950 -34.370 -20.025 ;
        RECT -33.915 -20.895 -33.530 -20.130 ;
        RECT -31.920 -20.330 -31.590 -19.620 ;
        RECT -30.245 -19.705 -29.920 -19.620 ;
        RECT -29.030 -19.705 -28.705 -18.705 ;
        RECT -27.890 -20.030 -27.585 -17.465 ;
        RECT -27.355 -17.495 -27.105 -16.420 ;
        RECT -14.225 -16.865 -13.965 -13.290 ;
        RECT -12.965 -14.065 -12.735 -13.535 ;
        RECT -11.845 -13.555 -11.615 -13.130 ;
        RECT -15.420 -17.105 -13.965 -16.865 ;
        RECT -13.730 -14.415 -12.735 -14.065 ;
        RECT -27.355 -17.725 -26.455 -17.495 ;
        RECT -26.880 -18.050 -26.455 -17.725 ;
        RECT -23.745 -18.050 -23.115 -17.480 ;
        RECT -26.880 -19.575 -26.530 -18.050 ;
        RECT -26.300 -18.615 -25.830 -18.220 ;
        RECT -24.985 -19.210 -24.620 -18.460 ;
        RECT -24.200 -18.515 -23.640 -18.280 ;
        RECT -24.145 -18.925 -23.695 -18.515 ;
        RECT -22.940 -18.615 -22.490 -18.220 ;
        RECT -22.085 -18.925 -21.585 -18.510 ;
        RECT -19.510 -18.925 -19.180 -17.480 ;
        RECT -15.420 -18.035 -15.190 -17.105 ;
        RECT -14.955 -17.625 -14.395 -17.355 ;
        RECT -24.145 -19.255 -19.180 -18.925 ;
        RECT -18.950 -19.150 -18.625 -18.145 ;
        RECT -15.420 -18.235 -15.020 -18.035 ;
        RECT -26.880 -20.000 -25.880 -19.575 ;
        RECT -32.335 -20.760 -31.590 -20.330 ;
        RECT -31.920 -20.895 -31.590 -20.760 ;
        RECT -38.005 -21.550 -35.290 -21.260 ;
        RECT -34.135 -21.550 -33.670 -20.895 ;
        RECT -28.570 -21.145 -27.585 -20.030 ;
        RECT -26.220 -20.275 -25.880 -20.000 ;
        RECT -22.515 -20.340 -22.130 -19.510 ;
        RECT -19.510 -20.340 -19.180 -19.255 ;
        RECT -15.350 -20.895 -15.020 -18.235 ;
        RECT -14.230 -18.460 -14.000 -17.805 ;
        RECT -14.230 -18.665 -13.960 -18.460 ;
        RECT -14.775 -19.690 -14.475 -19.165 ;
        RECT -14.195 -20.035 -13.960 -18.665 ;
        RECT -14.330 -20.270 -13.960 -20.035 ;
        RECT -13.730 -20.035 -13.470 -14.415 ;
        RECT -13.235 -16.270 -12.835 -15.785 ;
        RECT -13.235 -18.665 -12.835 -18.180 ;
        RECT -12.600 -19.705 -12.275 -14.745 ;
        RECT -12.045 -16.215 -11.615 -13.555 ;
        RECT -11.030 -14.425 -10.695 -13.500 ;
        RECT -8.245 -13.860 -7.915 -13.555 ;
        RECT -8.570 -14.380 -7.915 -13.860 ;
        RECT -10.090 -14.745 -9.375 -14.520 ;
        RECT -11.385 -15.040 -9.375 -14.745 ;
        RECT -14.330 -21.260 -14.100 -20.270 ;
        RECT -13.730 -20.385 -12.735 -20.035 ;
        RECT -12.965 -20.915 -12.735 -20.385 ;
        RECT -12.045 -21.260 -11.615 -18.235 ;
        RECT -11.385 -19.705 -11.060 -15.040 ;
        RECT -8.800 -15.745 -8.475 -14.745 ;
        RECT -8.245 -15.040 -7.915 -14.380 ;
        RECT -6.935 -14.415 -6.705 -13.040 ;
        RECT -6.570 -15.040 -6.245 -14.745 ;
        RECT -8.245 -15.490 -6.245 -15.040 ;
        RECT -10.825 -18.520 -10.485 -15.930 ;
        RECT -8.245 -16.415 -7.915 -15.490 ;
        RECT -6.570 -15.745 -6.245 -15.490 ;
        RECT -7.035 -15.985 -6.805 -15.785 ;
        RECT -7.035 -16.645 -6.650 -15.985 ;
        RECT -7.000 -16.780 -6.650 -16.645 ;
        RECT -6.015 -16.415 -5.585 -13.555 ;
        RECT -4.895 -14.520 -4.470 -13.320 ;
        RECT -5.355 -15.745 -5.030 -14.745 ;
        RECT -4.215 -15.340 -3.910 -13.040 ;
        RECT -1.520 -14.475 -0.965 -13.560 ;
        RECT -1.295 -15.095 -0.965 -14.475 ;
        RECT 0.620 -14.585 0.865 -13.560 ;
        RECT 2.685 -14.585 3.010 -13.560 ;
        RECT 5.155 -14.105 5.485 -13.735 ;
        RECT 5.155 -14.210 5.655 -14.105 ;
        RECT -4.220 -15.785 -3.910 -15.340 ;
        RECT -2.740 -15.625 -0.965 -15.095 ;
        RECT -4.795 -15.865 -3.910 -15.785 ;
        RECT -6.015 -17.150 -5.590 -16.415 ;
        RECT -4.795 -16.420 -2.805 -15.865 ;
        RECT -1.295 -16.420 -0.965 -15.625 ;
        RECT -0.735 -15.235 -0.410 -14.750 ;
        RECT 0.620 -15.040 3.010 -14.585 ;
        RECT 0.620 -15.235 0.875 -15.040 ;
        RECT -0.735 -15.550 0.875 -15.235 ;
        RECT -0.735 -15.750 -0.410 -15.550 ;
        RECT 0.545 -16.420 0.875 -15.550 ;
        RECT 5.190 -16.415 5.655 -14.210 ;
        RECT -4.795 -16.645 -3.910 -16.420 ;
        RECT -7.035 -17.465 -3.910 -17.150 ;
        RECT -7.035 -17.845 -6.800 -17.465 ;
        RECT -8.800 -18.905 -8.475 -18.705 ;
        RECT -9.740 -19.785 -9.450 -19.040 ;
        RECT -9.175 -19.705 -8.475 -18.905 ;
        RECT -8.245 -18.920 -7.915 -18.035 ;
        RECT -7.035 -18.665 -6.805 -17.845 ;
        RECT -6.570 -18.920 -6.245 -18.705 ;
        RECT -8.245 -19.620 -6.245 -18.920 ;
        RECT -11.030 -20.950 -10.695 -20.025 ;
        RECT -10.240 -20.895 -9.855 -20.130 ;
        RECT -8.245 -20.330 -7.915 -19.620 ;
        RECT -6.570 -19.705 -6.245 -19.620 ;
        RECT -5.355 -19.705 -5.030 -18.705 ;
        RECT -4.215 -20.030 -3.910 -17.465 ;
        RECT -3.680 -17.495 -3.430 -16.420 ;
        RECT -3.680 -17.725 -2.780 -17.495 ;
        RECT -3.205 -18.050 -2.780 -17.725 ;
        RECT -0.070 -18.050 0.560 -17.480 ;
        RECT -3.205 -19.575 -2.855 -18.050 ;
        RECT -2.625 -18.615 -2.155 -18.220 ;
        RECT -1.310 -19.210 -0.945 -18.460 ;
        RECT -0.525 -18.515 0.035 -18.280 ;
        RECT -0.470 -18.925 -0.020 -18.515 ;
        RECT 0.735 -18.615 1.185 -18.220 ;
        RECT 1.590 -18.925 2.090 -18.510 ;
        RECT 4.165 -18.925 4.495 -17.480 ;
        RECT -0.470 -19.255 4.495 -18.925 ;
        RECT 4.725 -19.150 5.050 -18.145 ;
        RECT -3.205 -20.000 -2.205 -19.575 ;
        RECT -8.660 -20.760 -7.915 -20.330 ;
        RECT -8.245 -20.895 -7.915 -20.760 ;
        RECT -14.330 -21.550 -11.615 -21.260 ;
        RECT -10.460 -21.550 -9.995 -20.895 ;
        RECT -4.895 -21.145 -3.910 -20.030 ;
        RECT -2.545 -20.275 -2.205 -20.000 ;
        RECT 1.160 -20.340 1.545 -19.510 ;
        RECT 4.165 -20.340 4.495 -19.255 ;
      LAYER Via1 ;
        RECT -83.625 0.040 -83.300 0.695 ;
        RECT -84.195 -0.505 -83.930 -0.135 ;
        RECT -84.755 -1.085 -84.495 -0.775 ;
        RECT -85.920 -1.945 -85.480 -1.675 ;
        RECT -85.800 -3.935 -85.500 -3.565 ;
        RECT -86.355 -5.150 -86.070 -4.450 ;
        RECT -84.195 -2.955 -83.930 -2.585 ;
        RECT -82.055 1.315 -81.720 2.120 ;
        RECT -79.580 1.360 -78.985 1.760 ;
        RECT -81.055 0.760 -80.460 1.160 ;
        RECT -83.625 -3.785 -83.300 -3.130 ;
        RECT -79.800 0.015 -79.530 0.860 ;
        RECT -81.850 -0.780 -81.520 -0.365 ;
        RECT -78.025 -1.040 -77.735 -0.310 ;
        RECT -75.890 1.250 -75.530 2.275 ;
        RECT -76.345 0.330 -76.080 0.870 ;
        RECT -72.545 1.265 -71.990 2.060 ;
        RECT -72.305 -0.650 -72.005 -0.055 ;
        RECT -70.465 -0.670 -70.165 -0.075 ;
        RECT -65.835 -0.675 -65.370 -0.140 ;
        RECT -81.850 -2.725 -81.520 -2.310 ;
        RECT -80.765 -4.015 -80.500 -3.440 ;
        RECT -79.785 -3.955 -79.515 -3.150 ;
        RECT -82.055 -5.210 -81.720 -4.405 ;
        RECT -79.600 -5.065 -79.005 -4.665 ;
        RECT -81.395 -5.795 -81.020 -5.390 ;
        RECT -76.345 -3.960 -76.080 -3.420 ;
        RECT -60.520 -0.505 -60.255 -0.135 ;
        RECT -58.380 1.315 -58.045 2.120 ;
        RECT -55.905 1.360 -55.310 1.760 ;
        RECT -57.380 0.760 -56.785 1.160 ;
        RECT -61.080 -1.085 -60.820 -0.775 ;
        RECT -71.020 -2.350 -70.610 -1.815 ;
        RECT -73.640 -2.875 -73.190 -2.600 ;
        RECT -72.325 -3.470 -71.980 -2.840 ;
        RECT -70.290 -2.875 -69.850 -2.600 ;
        RECT -69.435 -3.510 -68.935 -3.060 ;
        RECT -66.280 -3.390 -66.020 -2.525 ;
        RECT -84.945 -6.425 -84.410 -6.165 ;
        RECT -77.040 -6.335 -76.615 -5.410 ;
        RECT -69.845 -4.595 -69.500 -3.895 ;
        RECT -70.230 -7.295 -69.755 -6.680 ;
        RECT -62.245 -1.945 -61.805 -1.675 ;
        RECT -62.680 -5.150 -62.395 -4.450 ;
        RECT -60.520 -2.955 -60.255 -2.585 ;
        RECT -58.175 -0.780 -57.845 -0.365 ;
        RECT -54.350 -1.040 -54.060 -0.310 ;
        RECT -52.215 1.250 -51.855 2.275 ;
        RECT -48.870 1.265 -48.315 2.060 ;
        RECT -48.630 -0.650 -48.330 -0.055 ;
        RECT -46.790 -0.670 -46.490 -0.075 ;
        RECT -42.160 -0.675 -41.695 -0.140 ;
        RECT -58.175 -2.725 -57.845 -2.310 ;
        RECT -57.090 -4.015 -56.825 -3.440 ;
        RECT -58.380 -5.210 -58.045 -4.405 ;
        RECT -55.925 -5.065 -55.330 -4.665 ;
        RECT -57.720 -5.795 -57.345 -5.390 ;
        RECT -36.275 0.040 -35.950 0.695 ;
        RECT -36.845 -0.505 -36.580 -0.135 ;
        RECT -37.405 -1.085 -37.145 -0.775 ;
        RECT -47.345 -2.350 -46.935 -1.815 ;
        RECT -49.965 -2.875 -49.515 -2.600 ;
        RECT -48.650 -3.470 -48.305 -2.840 ;
        RECT -46.615 -2.875 -46.175 -2.600 ;
        RECT -45.760 -3.510 -45.260 -3.060 ;
        RECT -42.605 -3.390 -42.345 -2.525 ;
        RECT -61.270 -6.425 -60.735 -6.165 ;
        RECT -53.365 -6.335 -52.940 -5.410 ;
        RECT -46.170 -4.595 -45.825 -3.895 ;
        RECT -63.450 -7.525 -62.940 -7.235 ;
        RECT -56.710 -7.525 -56.225 -7.235 ;
        RECT -84.470 -8.455 -84.005 -8.195 ;
        RECT -70.715 -8.510 -70.455 -8.040 ;
        RECT -66.160 -8.490 -65.830 -7.785 ;
        RECT -46.555 -7.295 -46.080 -6.680 ;
        RECT -38.570 -1.945 -38.130 -1.675 ;
        RECT -38.450 -3.935 -38.150 -3.565 ;
        RECT -39.005 -5.150 -38.720 -4.450 ;
        RECT -36.845 -2.955 -36.580 -2.585 ;
        RECT -34.705 1.315 -34.370 2.120 ;
        RECT -32.230 1.360 -31.635 1.760 ;
        RECT -33.705 0.760 -33.110 1.160 ;
        RECT -36.275 -3.785 -35.950 -3.130 ;
        RECT -32.450 0.015 -32.180 0.860 ;
        RECT -34.500 -0.780 -34.170 -0.365 ;
        RECT -30.675 -1.040 -30.385 -0.310 ;
        RECT -28.540 1.250 -28.180 2.275 ;
        RECT -28.995 0.330 -28.730 0.870 ;
        RECT -25.195 1.265 -24.640 2.060 ;
        RECT -24.955 -0.650 -24.655 -0.055 ;
        RECT -23.115 -0.670 -22.815 -0.075 ;
        RECT -18.485 -0.675 -18.020 -0.140 ;
        RECT -34.500 -2.725 -34.170 -2.310 ;
        RECT -33.415 -4.015 -33.150 -3.440 ;
        RECT -32.435 -3.955 -32.165 -3.150 ;
        RECT -34.705 -5.210 -34.370 -4.405 ;
        RECT -32.250 -5.065 -31.655 -4.665 ;
        RECT -34.045 -5.795 -33.670 -5.390 ;
        RECT -28.995 -3.960 -28.730 -3.420 ;
        RECT -13.170 -0.505 -12.905 -0.135 ;
        RECT -11.030 1.315 -10.695 2.120 ;
        RECT -8.555 1.360 -7.960 1.760 ;
        RECT -10.030 0.760 -9.435 1.160 ;
        RECT -13.730 -1.085 -13.470 -0.775 ;
        RECT -23.670 -2.350 -23.260 -1.815 ;
        RECT -26.290 -2.875 -25.840 -2.600 ;
        RECT -24.975 -3.470 -24.630 -2.840 ;
        RECT -22.940 -2.875 -22.500 -2.600 ;
        RECT -22.085 -3.510 -21.585 -3.060 ;
        RECT -18.930 -3.390 -18.670 -2.525 ;
        RECT -37.595 -6.425 -37.060 -6.165 ;
        RECT -29.690 -6.335 -29.265 -5.410 ;
        RECT -22.495 -4.595 -22.150 -3.895 ;
        RECT -84.060 -9.280 -83.760 -8.885 ;
        RECT -60.795 -8.455 -60.330 -8.195 ;
        RECT -47.040 -8.510 -46.780 -8.040 ;
        RECT -42.485 -8.490 -42.155 -7.785 ;
        RECT -22.880 -7.295 -22.405 -6.680 ;
        RECT -14.895 -1.945 -14.455 -1.675 ;
        RECT -15.330 -5.150 -15.045 -4.450 ;
        RECT -13.170 -2.955 -12.905 -2.585 ;
        RECT -10.825 -0.780 -10.495 -0.365 ;
        RECT -7.000 -1.040 -6.710 -0.310 ;
        RECT -4.865 1.250 -4.505 2.275 ;
        RECT -1.520 1.265 -0.965 2.060 ;
        RECT -1.280 -0.650 -0.980 -0.055 ;
        RECT 0.560 -0.670 0.860 -0.075 ;
        RECT 5.190 -0.675 5.655 -0.140 ;
        RECT -10.825 -2.725 -10.495 -2.310 ;
        RECT -9.740 -4.015 -9.475 -3.440 ;
        RECT -11.030 -5.210 -10.695 -4.405 ;
        RECT -8.575 -5.065 -7.980 -4.665 ;
        RECT -10.370 -5.795 -9.995 -5.390 ;
        RECT 0.005 -2.350 0.415 -1.815 ;
        RECT -2.615 -2.875 -2.165 -2.600 ;
        RECT -1.300 -3.470 -0.955 -2.840 ;
        RECT 0.735 -2.875 1.175 -2.600 ;
        RECT 1.590 -3.510 2.090 -3.060 ;
        RECT 4.745 -3.390 5.005 -2.525 ;
        RECT -13.920 -6.425 -13.385 -6.165 ;
        RECT -6.015 -6.335 -5.590 -5.410 ;
        RECT 1.180 -4.595 1.525 -3.895 ;
        RECT -16.100 -7.525 -15.590 -7.235 ;
        RECT -9.360 -7.525 -8.875 -7.235 ;
        RECT -83.570 -10.325 -83.305 -9.785 ;
        RECT -81.920 -11.275 -81.620 -10.880 ;
        RECT -80.130 -10.345 -79.865 -9.805 ;
        RECT -77.690 -10.345 -77.425 -9.805 ;
        RECT -76.725 -10.285 -76.125 -10.015 ;
        RECT -69.330 -10.660 -68.930 -10.355 ;
        RECT -68.115 -11.160 -67.810 -10.495 ;
        RECT -67.555 -12.425 -67.275 -11.725 ;
        RECT -66.120 -11.245 -65.795 -10.535 ;
        RECT -60.385 -9.280 -60.085 -8.885 ;
        RECT -59.895 -10.325 -59.630 -9.785 ;
        RECT -37.120 -8.455 -36.655 -8.195 ;
        RECT -23.365 -8.510 -23.105 -8.040 ;
        RECT -18.810 -8.490 -18.480 -7.785 ;
        RECT 0.795 -7.295 1.270 -6.680 ;
        RECT -61.090 -12.505 -60.485 -12.050 ;
        RECT -58.245 -11.275 -57.945 -10.880 ;
        RECT -85.250 -13.230 -84.640 -12.970 ;
        RECT -56.455 -10.345 -56.190 -9.805 ;
        RECT -55.140 -9.760 -54.850 -9.275 ;
        RECT -54.015 -10.345 -53.750 -9.805 ;
        RECT -53.050 -10.285 -52.450 -10.015 ;
        RECT -45.655 -10.660 -45.255 -10.355 ;
        RECT -44.440 -11.160 -44.135 -10.495 ;
        RECT -43.880 -12.425 -43.600 -11.725 ;
        RECT -42.445 -11.245 -42.120 -10.535 ;
        RECT -36.710 -9.280 -36.410 -8.885 ;
        RECT -13.445 -8.455 -12.980 -8.195 ;
        RECT 0.310 -8.510 0.570 -8.040 ;
        RECT 4.865 -8.490 5.195 -7.785 ;
        RECT -36.220 -10.325 -35.955 -9.785 ;
        RECT -34.570 -11.275 -34.270 -10.880 ;
        RECT -83.625 -15.640 -83.300 -14.985 ;
        RECT -84.195 -16.185 -83.930 -15.815 ;
        RECT -84.755 -16.765 -84.495 -16.455 ;
        RECT -85.920 -17.625 -85.480 -17.355 ;
        RECT -85.800 -19.615 -85.500 -19.245 ;
        RECT -86.355 -20.830 -86.070 -20.130 ;
        RECT -84.195 -18.635 -83.930 -18.265 ;
        RECT -82.055 -14.365 -81.720 -13.560 ;
        RECT -79.580 -14.320 -78.985 -13.920 ;
        RECT -81.055 -14.920 -80.460 -14.520 ;
        RECT -83.625 -19.465 -83.300 -18.810 ;
        RECT -79.800 -15.665 -79.530 -14.820 ;
        RECT -81.850 -16.460 -81.520 -16.045 ;
        RECT -78.025 -16.720 -77.735 -15.990 ;
        RECT -75.890 -14.430 -75.530 -13.405 ;
        RECT -76.345 -15.350 -76.080 -14.810 ;
        RECT -61.575 -13.230 -60.965 -12.970 ;
        RECT -32.780 -10.345 -32.515 -9.805 ;
        RECT -30.340 -10.345 -30.075 -9.805 ;
        RECT -29.375 -10.285 -28.775 -10.015 ;
        RECT -21.980 -10.660 -21.580 -10.355 ;
        RECT -20.765 -11.160 -20.460 -10.495 ;
        RECT -20.205 -12.425 -19.925 -11.725 ;
        RECT -18.770 -11.245 -18.445 -10.535 ;
        RECT -13.035 -9.280 -12.735 -8.885 ;
        RECT -12.545 -10.325 -12.280 -9.785 ;
        RECT -13.740 -12.505 -13.135 -12.050 ;
        RECT -10.895 -11.275 -10.595 -10.880 ;
        RECT -72.545 -14.415 -71.990 -13.620 ;
        RECT -72.305 -16.330 -72.005 -15.735 ;
        RECT -70.465 -16.350 -70.165 -15.755 ;
        RECT -65.835 -16.355 -65.370 -15.820 ;
        RECT -81.850 -18.405 -81.520 -17.990 ;
        RECT -80.765 -19.695 -80.500 -19.120 ;
        RECT -79.785 -19.635 -79.515 -18.830 ;
        RECT -82.055 -20.890 -81.720 -20.085 ;
        RECT -76.345 -19.640 -76.080 -19.100 ;
        RECT -59.950 -15.640 -59.625 -14.985 ;
        RECT -60.520 -16.185 -60.255 -15.815 ;
        RECT -61.080 -16.765 -60.820 -16.455 ;
        RECT -71.020 -18.030 -70.610 -17.495 ;
        RECT -73.640 -18.555 -73.190 -18.280 ;
        RECT -72.325 -19.150 -71.980 -18.520 ;
        RECT -70.290 -18.555 -69.850 -18.280 ;
        RECT -69.435 -19.190 -68.935 -18.740 ;
        RECT -62.245 -17.625 -61.805 -17.355 ;
        RECT -66.280 -19.070 -66.020 -18.205 ;
        RECT -79.600 -20.745 -79.005 -20.345 ;
        RECT -81.395 -21.475 -81.020 -21.070 ;
        RECT -69.845 -20.275 -69.500 -19.575 ;
        RECT -62.125 -19.615 -61.825 -19.245 ;
        RECT -62.680 -20.830 -62.395 -20.130 ;
        RECT -60.520 -18.635 -60.255 -18.265 ;
        RECT -58.380 -14.365 -58.045 -13.560 ;
        RECT -55.905 -14.320 -55.310 -13.920 ;
        RECT -57.380 -14.920 -56.785 -14.520 ;
        RECT -59.950 -19.465 -59.625 -18.810 ;
        RECT -56.125 -15.665 -55.855 -14.820 ;
        RECT -58.175 -16.460 -57.845 -16.045 ;
        RECT -54.350 -16.720 -54.060 -15.990 ;
        RECT -52.215 -14.430 -51.855 -13.405 ;
        RECT -52.670 -15.350 -52.405 -14.810 ;
        RECT -37.900 -13.230 -37.290 -12.970 ;
        RECT -9.105 -10.345 -8.840 -9.805 ;
        RECT -7.790 -9.760 -7.500 -9.275 ;
        RECT -6.665 -10.345 -6.400 -9.805 ;
        RECT -5.700 -10.285 -5.100 -10.015 ;
        RECT 1.695 -10.660 2.095 -10.355 ;
        RECT 2.910 -11.160 3.215 -10.495 ;
        RECT 3.470 -12.425 3.750 -11.725 ;
        RECT 4.905 -11.245 5.230 -10.535 ;
        RECT -48.870 -14.415 -48.315 -13.620 ;
        RECT -48.630 -16.330 -48.330 -15.735 ;
        RECT -46.790 -16.350 -46.490 -15.755 ;
        RECT -42.160 -16.355 -41.695 -15.820 ;
        RECT -58.175 -18.405 -57.845 -17.990 ;
        RECT -57.090 -19.695 -56.825 -19.120 ;
        RECT -56.110 -19.635 -55.840 -18.830 ;
        RECT -58.380 -20.890 -58.045 -20.085 ;
        RECT -52.670 -19.640 -52.405 -19.100 ;
        RECT -36.275 -15.640 -35.950 -14.985 ;
        RECT -36.845 -16.185 -36.580 -15.815 ;
        RECT -37.405 -16.765 -37.145 -16.455 ;
        RECT -47.345 -18.030 -46.935 -17.495 ;
        RECT -49.965 -18.555 -49.515 -18.280 ;
        RECT -48.650 -19.150 -48.305 -18.520 ;
        RECT -46.615 -18.555 -46.175 -18.280 ;
        RECT -45.760 -19.190 -45.260 -18.740 ;
        RECT -38.570 -17.625 -38.130 -17.355 ;
        RECT -42.605 -19.070 -42.345 -18.205 ;
        RECT -55.925 -20.745 -55.330 -20.345 ;
        RECT -57.720 -21.475 -57.345 -21.070 ;
        RECT -46.170 -20.275 -45.825 -19.575 ;
        RECT -38.450 -19.615 -38.150 -19.245 ;
        RECT -39.005 -20.830 -38.720 -20.130 ;
        RECT -36.845 -18.635 -36.580 -18.265 ;
        RECT -34.705 -14.365 -34.370 -13.560 ;
        RECT -32.230 -14.320 -31.635 -13.920 ;
        RECT -33.705 -14.920 -33.110 -14.520 ;
        RECT -36.275 -19.465 -35.950 -18.810 ;
        RECT -32.450 -15.665 -32.180 -14.820 ;
        RECT -34.500 -16.460 -34.170 -16.045 ;
        RECT -30.675 -16.720 -30.385 -15.990 ;
        RECT -28.540 -14.430 -28.180 -13.405 ;
        RECT -28.995 -15.350 -28.730 -14.810 ;
        RECT -14.225 -13.230 -13.615 -12.970 ;
        RECT -25.195 -14.415 -24.640 -13.620 ;
        RECT -24.955 -16.330 -24.655 -15.735 ;
        RECT -23.115 -16.350 -22.815 -15.755 ;
        RECT -18.485 -16.355 -18.020 -15.820 ;
        RECT -34.500 -18.405 -34.170 -17.990 ;
        RECT -33.415 -19.695 -33.150 -19.120 ;
        RECT -32.435 -19.635 -32.165 -18.830 ;
        RECT -34.705 -20.890 -34.370 -20.085 ;
        RECT -28.995 -19.640 -28.730 -19.100 ;
        RECT -12.600 -15.640 -12.275 -14.985 ;
        RECT -13.170 -16.185 -12.905 -15.815 ;
        RECT -13.730 -16.765 -13.470 -16.455 ;
        RECT -23.670 -18.030 -23.260 -17.495 ;
        RECT -26.290 -18.555 -25.840 -18.280 ;
        RECT -24.975 -19.150 -24.630 -18.520 ;
        RECT -22.940 -18.555 -22.500 -18.280 ;
        RECT -22.085 -19.190 -21.585 -18.740 ;
        RECT -14.895 -17.625 -14.455 -17.355 ;
        RECT -18.930 -19.070 -18.670 -18.205 ;
        RECT -32.250 -20.745 -31.655 -20.345 ;
        RECT -34.045 -21.475 -33.670 -21.070 ;
        RECT -22.495 -20.275 -22.150 -19.575 ;
        RECT -14.775 -19.615 -14.475 -19.245 ;
        RECT -15.330 -20.830 -15.045 -20.130 ;
        RECT -13.170 -18.635 -12.905 -18.265 ;
        RECT -11.030 -14.365 -10.695 -13.560 ;
        RECT -8.555 -14.320 -7.960 -13.920 ;
        RECT -10.030 -14.920 -9.435 -14.520 ;
        RECT -12.600 -19.465 -12.275 -18.810 ;
        RECT -8.775 -15.665 -8.505 -14.820 ;
        RECT -10.825 -16.460 -10.495 -16.045 ;
        RECT -7.000 -16.720 -6.710 -15.990 ;
        RECT -4.865 -14.430 -4.505 -13.405 ;
        RECT -5.320 -15.350 -5.055 -14.810 ;
        RECT -1.520 -14.415 -0.965 -13.620 ;
        RECT -1.280 -16.330 -0.980 -15.735 ;
        RECT 0.560 -16.350 0.860 -15.755 ;
        RECT 5.190 -16.355 5.655 -15.820 ;
        RECT -10.825 -18.405 -10.495 -17.990 ;
        RECT -9.740 -19.695 -9.475 -19.120 ;
        RECT -8.760 -19.635 -8.490 -18.830 ;
        RECT -11.030 -20.890 -10.695 -20.085 ;
        RECT -5.320 -19.640 -5.055 -19.100 ;
        RECT 0.005 -18.030 0.415 -17.495 ;
        RECT -2.615 -18.555 -2.165 -18.280 ;
        RECT -1.300 -19.150 -0.955 -18.520 ;
        RECT 0.735 -18.555 1.175 -18.280 ;
        RECT 1.590 -19.190 2.090 -18.740 ;
        RECT 4.745 -19.070 5.005 -18.205 ;
        RECT -8.575 -20.745 -7.980 -20.345 ;
        RECT -10.370 -21.475 -9.995 -21.070 ;
        RECT 1.180 -20.275 1.525 -19.575 ;
      LAYER Metal2 ;
        RECT -77.805 3.375 -65.265 3.795 ;
        RECT -82.065 1.535 -81.710 2.180 ;
        RECT -79.595 1.585 -78.940 1.820 ;
        RECT -84.225 1.255 -81.710 1.535 ;
        RECT -81.080 1.300 -78.940 1.585 ;
        RECT -84.225 -0.075 -83.945 1.255 ;
        RECT -83.635 0.350 -83.290 0.755 ;
        RECT -81.080 0.695 -80.435 1.300 ;
        RECT -77.805 0.935 -77.385 3.375 ;
        RECT -75.950 1.215 -75.430 2.360 ;
        RECT -79.825 0.430 -76.050 0.935 ;
        RECT -79.825 0.350 -79.500 0.430 ;
        RECT -83.635 0.015 -79.500 0.350 ;
        RECT -76.385 0.265 -76.050 0.430 ;
        RECT -83.635 -0.020 -83.290 0.015 ;
        RECT -79.825 -0.065 -79.500 0.015 ;
        RECT -84.225 -0.565 -83.915 -0.075 ;
        RECT -75.765 -0.250 -75.430 1.215 ;
        RECT -72.560 1.205 -71.975 2.120 ;
        RECT -65.685 0.845 -65.265 3.375 ;
        RECT -30.455 3.375 -17.915 3.795 ;
        RECT -58.390 1.535 -58.035 2.180 ;
        RECT -55.920 1.585 -55.265 1.820 ;
        RECT -60.550 1.255 -58.035 1.535 ;
        RECT -57.405 1.300 -55.265 1.585 ;
        RECT -78.060 -0.255 -75.430 -0.250 ;
        RECT -73.215 0.255 -69.185 0.600 ;
        RECT -65.685 0.425 -63.465 0.845 ;
        RECT -81.875 -0.575 -81.510 -0.305 ;
        RECT -84.770 -0.855 -84.480 -0.715 ;
        RECT -83.595 -0.850 -81.510 -0.575 ;
        RECT -78.060 -0.535 -74.575 -0.255 ;
        RECT -83.595 -0.855 -81.555 -0.850 ;
        RECT -84.770 -1.145 -83.300 -0.855 ;
        RECT -78.060 -1.155 -77.580 -0.535 ;
        RECT -76.880 -0.540 -74.575 -0.535 ;
        RECT -86.000 -1.960 -80.470 -1.585 ;
        RECT -84.225 -3.015 -83.915 -2.525 ;
        RECT -81.875 -2.785 -81.510 -2.240 ;
        RECT -85.810 -4.010 -85.490 -3.505 ;
        RECT -84.225 -4.345 -83.945 -3.015 ;
        RECT -83.635 -3.845 -83.290 -3.070 ;
        RECT -86.375 -5.575 -86.045 -4.385 ;
        RECT -84.225 -4.625 -81.710 -4.345 ;
        RECT -82.065 -5.270 -81.710 -4.625 ;
        RECT -80.845 -4.650 -80.470 -1.960 ;
        RECT -79.825 -3.360 -79.495 -3.090 ;
        RECT -78.660 -3.360 -77.565 -3.025 ;
        RECT -76.385 -3.360 -76.050 -3.355 ;
        RECT -79.825 -4.025 -76.050 -3.360 ;
        RECT -74.880 -4.565 -74.575 -0.540 ;
        RECT -73.215 -1.870 -72.915 0.255 ;
        RECT -72.320 -0.055 -71.990 -0.025 ;
        RECT -72.365 -0.740 -71.945 -0.055 ;
        RECT -70.525 -0.680 -69.965 -0.065 ;
        RECT -73.650 -2.215 -72.915 -1.870 ;
        RECT -73.650 -2.540 -73.305 -2.215 ;
        RECT -72.320 -2.540 -71.990 -0.740 ;
        RECT -71.035 -2.410 -70.600 -1.755 ;
        RECT -73.650 -2.935 -73.180 -2.540 ;
        RECT -72.335 -3.530 -71.970 -2.540 ;
        RECT -71.035 -4.565 -70.710 -2.410 ;
        RECT -70.310 -2.540 -69.965 -0.680 ;
        RECT -69.530 -0.390 -69.185 0.255 ;
        RECT -65.845 -0.390 -65.350 -0.080 ;
        RECT -69.530 -0.735 -65.350 -0.390 ;
        RECT -70.310 -2.935 -69.840 -2.540 ;
        RECT -69.495 -3.530 -68.865 -3.035 ;
        RECT -66.310 -3.465 -65.985 -0.735 ;
        RECT -69.865 -4.565 -69.480 -3.830 ;
        RECT -80.845 -5.080 -78.940 -4.650 ;
        RECT -74.880 -4.865 -69.480 -4.565 ;
        RECT -74.625 -4.870 -69.480 -4.865 ;
        RECT -81.410 -5.575 -80.995 -5.330 ;
        RECT -86.375 -5.855 -80.995 -5.575 ;
        RECT -85.005 -6.155 -84.290 -6.150 ;
        RECT -85.005 -6.440 -84.225 -6.155 ;
        RECT -84.530 -8.180 -84.225 -6.440 ;
        RECT -84.530 -8.465 -83.945 -8.180 ;
        RECT -84.160 -9.350 -83.750 -8.810 ;
        RECT -84.160 -10.870 -83.880 -9.350 ;
        RECT -83.425 -9.720 -83.100 -5.855 ;
        RECT -77.050 -6.290 -76.605 -5.350 ;
        RECT -77.055 -7.185 -76.600 -6.290 ;
        RECT -63.905 -6.325 -63.465 0.425 ;
        RECT -60.550 -0.075 -60.270 1.255 ;
        RECT -57.405 0.695 -56.760 1.300 ;
        RECT -52.275 1.215 -51.755 2.360 ;
        RECT -60.550 -0.565 -60.240 -0.075 ;
        RECT -52.090 -0.250 -51.755 1.215 ;
        RECT -48.885 1.205 -48.300 2.120 ;
        RECT -34.715 1.535 -34.360 2.180 ;
        RECT -32.245 1.585 -31.590 1.820 ;
        RECT -36.875 1.255 -34.360 1.535 ;
        RECT -33.730 1.300 -31.590 1.585 ;
        RECT -54.385 -0.255 -51.755 -0.250 ;
        RECT -49.540 0.255 -45.510 0.600 ;
        RECT -58.200 -0.575 -57.835 -0.305 ;
        RECT -61.095 -0.855 -60.805 -0.715 ;
        RECT -59.920 -0.850 -57.835 -0.575 ;
        RECT -54.385 -0.535 -50.900 -0.255 ;
        RECT -59.920 -0.855 -57.880 -0.850 ;
        RECT -61.095 -1.145 -59.625 -0.855 ;
        RECT -54.385 -1.155 -53.905 -0.535 ;
        RECT -53.205 -0.540 -50.900 -0.535 ;
        RECT -62.325 -1.960 -56.795 -1.585 ;
        RECT -60.550 -3.015 -60.240 -2.525 ;
        RECT -58.200 -2.785 -57.835 -2.240 ;
        RECT -60.550 -4.345 -60.270 -3.015 ;
        RECT -62.700 -5.575 -62.370 -4.385 ;
        RECT -60.550 -4.625 -58.035 -4.345 ;
        RECT -58.390 -5.270 -58.035 -4.625 ;
        RECT -57.170 -4.650 -56.795 -1.960 ;
        RECT -51.205 -4.565 -50.900 -0.540 ;
        RECT -49.540 -1.870 -49.240 0.255 ;
        RECT -48.645 -0.055 -48.315 -0.025 ;
        RECT -48.690 -0.740 -48.270 -0.055 ;
        RECT -46.850 -0.680 -46.290 -0.065 ;
        RECT -49.975 -2.215 -49.240 -1.870 ;
        RECT -49.975 -2.540 -49.630 -2.215 ;
        RECT -48.645 -2.540 -48.315 -0.740 ;
        RECT -47.360 -2.410 -46.925 -1.755 ;
        RECT -49.975 -2.935 -49.505 -2.540 ;
        RECT -48.660 -3.530 -48.295 -2.540 ;
        RECT -47.360 -4.565 -47.035 -2.410 ;
        RECT -46.635 -2.540 -46.290 -0.680 ;
        RECT -45.855 -0.390 -45.510 0.255 ;
        RECT -36.875 -0.075 -36.595 1.255 ;
        RECT -36.285 0.350 -35.940 0.755 ;
        RECT -33.730 0.695 -33.085 1.300 ;
        RECT -30.455 0.935 -30.035 3.375 ;
        RECT -28.600 1.215 -28.080 2.360 ;
        RECT -32.475 0.430 -28.700 0.935 ;
        RECT -32.475 0.350 -32.150 0.430 ;
        RECT -36.285 0.015 -32.150 0.350 ;
        RECT -29.035 0.265 -28.700 0.430 ;
        RECT -36.285 -0.020 -35.940 0.015 ;
        RECT -32.475 -0.065 -32.150 0.015 ;
        RECT -42.170 -0.390 -41.675 -0.080 ;
        RECT -45.855 -0.735 -41.675 -0.390 ;
        RECT -36.875 -0.565 -36.565 -0.075 ;
        RECT -28.415 -0.250 -28.080 1.215 ;
        RECT -25.210 1.205 -24.625 2.120 ;
        RECT -18.335 0.845 -17.915 3.375 ;
        RECT -11.040 1.535 -10.685 2.180 ;
        RECT -8.570 1.585 -7.915 1.820 ;
        RECT -13.200 1.255 -10.685 1.535 ;
        RECT -10.055 1.300 -7.915 1.585 ;
        RECT -30.710 -0.255 -28.080 -0.250 ;
        RECT -25.865 0.255 -21.835 0.600 ;
        RECT -18.335 0.425 -16.115 0.845 ;
        RECT -34.525 -0.575 -34.160 -0.305 ;
        RECT -46.635 -2.935 -46.165 -2.540 ;
        RECT -45.820 -3.530 -45.190 -3.035 ;
        RECT -42.635 -3.465 -42.310 -0.735 ;
        RECT -37.420 -0.855 -37.130 -0.715 ;
        RECT -36.245 -0.850 -34.160 -0.575 ;
        RECT -30.710 -0.535 -27.225 -0.255 ;
        RECT -36.245 -0.855 -34.205 -0.850 ;
        RECT -37.420 -1.145 -35.950 -0.855 ;
        RECT -30.710 -1.155 -30.230 -0.535 ;
        RECT -29.530 -0.540 -27.225 -0.535 ;
        RECT -38.650 -1.960 -33.120 -1.585 ;
        RECT -36.875 -3.015 -36.565 -2.525 ;
        RECT -34.525 -2.785 -34.160 -2.240 ;
        RECT -46.190 -4.565 -45.805 -3.830 ;
        RECT -38.460 -4.010 -38.140 -3.505 ;
        RECT -36.875 -4.345 -36.595 -3.015 ;
        RECT -36.285 -3.845 -35.940 -3.070 ;
        RECT -57.170 -5.080 -55.265 -4.650 ;
        RECT -51.205 -4.865 -45.805 -4.565 ;
        RECT -50.950 -4.870 -45.805 -4.865 ;
        RECT -57.735 -5.575 -57.320 -5.330 ;
        RECT -62.700 -5.855 -57.320 -5.575 ;
        RECT -61.330 -6.155 -60.615 -6.150 ;
        RECT -70.245 -7.185 -69.735 -6.620 ;
        RECT -63.905 -6.655 -61.635 -6.325 ;
        RECT -61.330 -6.440 -60.550 -6.155 ;
        RECT -77.055 -7.375 -69.735 -7.185 ;
        RECT -77.055 -7.465 -69.740 -7.375 ;
        RECT -63.510 -7.535 -62.880 -7.225 ;
        RECT -70.775 -8.035 -70.365 -8.030 ;
        RECT -70.775 -8.240 -70.355 -8.035 ;
        RECT -70.775 -8.520 -69.060 -8.240 ;
        RECT -83.600 -9.795 -83.100 -9.720 ;
        RECT -83.600 -10.100 -79.805 -9.795 ;
        RECT -77.750 -10.100 -77.365 -9.795 ;
        RECT -83.600 -10.355 -77.365 -10.100 ;
        RECT -83.600 -10.360 -83.100 -10.355 ;
        RECT -83.600 -10.390 -83.265 -10.360 ;
        RECT -80.150 -10.380 -77.365 -10.355 ;
        RECT -76.740 -10.350 -76.110 -9.955 ;
        RECT -69.340 -10.290 -69.060 -8.520 ;
        RECT -66.175 -8.580 -65.815 -7.710 ;
        RECT -76.740 -10.670 -76.395 -10.350 ;
        RECT -84.160 -11.150 -81.560 -10.870 ;
        RECT -81.980 -11.285 -81.560 -11.150 ;
        RECT -81.280 -10.950 -76.395 -10.670 ;
        RECT -69.340 -10.720 -68.920 -10.290 ;
        RECT -81.280 -12.910 -81.000 -10.950 ;
        RECT -68.130 -11.375 -67.795 -10.420 ;
        RECT -66.110 -10.475 -65.830 -8.580 ;
        RECT -66.130 -11.375 -65.785 -10.475 ;
        RECT -68.130 -12.115 -67.850 -11.375 ;
        RECT -85.260 -13.190 -81.000 -12.910 ;
        RECT -76.540 -12.420 -67.850 -12.115 ;
        RECT -85.260 -13.290 -84.630 -13.190 ;
        RECT -82.065 -14.145 -81.710 -13.500 ;
        RECT -79.595 -14.095 -78.940 -13.860 ;
        RECT -84.225 -14.425 -81.710 -14.145 ;
        RECT -81.080 -14.380 -78.940 -14.095 ;
        RECT -84.225 -15.755 -83.945 -14.425 ;
        RECT -83.635 -15.330 -83.290 -14.925 ;
        RECT -81.080 -14.985 -80.435 -14.380 ;
        RECT -76.540 -14.745 -76.230 -12.420 ;
        RECT -67.565 -12.490 -67.260 -11.665 ;
        RECT -61.915 -12.030 -61.635 -6.655 ;
        RECT -60.855 -8.180 -60.550 -6.440 ;
        RECT -60.855 -8.465 -60.270 -8.180 ;
        RECT -60.485 -9.350 -60.075 -8.810 ;
        RECT -60.485 -10.870 -60.205 -9.350 ;
        RECT -59.750 -9.720 -59.425 -5.855 ;
        RECT -53.375 -6.290 -52.930 -5.350 ;
        RECT -39.025 -5.575 -38.695 -4.385 ;
        RECT -36.875 -4.625 -34.360 -4.345 ;
        RECT -34.715 -5.270 -34.360 -4.625 ;
        RECT -33.495 -4.650 -33.120 -1.960 ;
        RECT -32.475 -3.360 -32.145 -3.090 ;
        RECT -31.310 -3.360 -30.215 -3.025 ;
        RECT -29.035 -3.360 -28.700 -3.355 ;
        RECT -32.475 -4.025 -28.700 -3.360 ;
        RECT -27.530 -4.565 -27.225 -0.540 ;
        RECT -25.865 -1.870 -25.565 0.255 ;
        RECT -24.970 -0.055 -24.640 -0.025 ;
        RECT -25.015 -0.740 -24.595 -0.055 ;
        RECT -23.175 -0.680 -22.615 -0.065 ;
        RECT -26.300 -2.215 -25.565 -1.870 ;
        RECT -26.300 -2.540 -25.955 -2.215 ;
        RECT -24.970 -2.540 -24.640 -0.740 ;
        RECT -23.685 -2.410 -23.250 -1.755 ;
        RECT -26.300 -2.935 -25.830 -2.540 ;
        RECT -24.985 -3.530 -24.620 -2.540 ;
        RECT -23.685 -4.565 -23.360 -2.410 ;
        RECT -22.960 -2.540 -22.615 -0.680 ;
        RECT -22.180 -0.390 -21.835 0.255 ;
        RECT -18.495 -0.390 -18.000 -0.080 ;
        RECT -22.180 -0.735 -18.000 -0.390 ;
        RECT -22.960 -2.935 -22.490 -2.540 ;
        RECT -22.145 -3.530 -21.515 -3.035 ;
        RECT -18.960 -3.465 -18.635 -0.735 ;
        RECT -22.515 -4.565 -22.130 -3.830 ;
        RECT -33.495 -5.080 -31.590 -4.650 ;
        RECT -27.530 -4.865 -22.130 -4.565 ;
        RECT -27.275 -4.870 -22.130 -4.865 ;
        RECT -34.060 -5.575 -33.645 -5.330 ;
        RECT -39.025 -5.855 -33.645 -5.575 ;
        RECT -37.655 -6.155 -36.940 -6.150 ;
        RECT -53.380 -7.185 -52.925 -6.290 ;
        RECT -37.655 -6.440 -36.875 -6.155 ;
        RECT -46.570 -7.185 -46.060 -6.620 ;
        RECT -56.770 -7.540 -56.160 -7.215 ;
        RECT -53.380 -7.375 -46.060 -7.185 ;
        RECT -53.380 -7.465 -46.065 -7.375 ;
        RECT -56.535 -9.180 -56.160 -7.540 ;
        RECT -47.100 -8.035 -46.690 -8.030 ;
        RECT -47.100 -8.240 -46.680 -8.035 ;
        RECT -47.100 -8.520 -45.385 -8.240 ;
        RECT -55.140 -9.180 -54.850 -9.175 ;
        RECT -56.535 -9.510 -54.840 -9.180 ;
        RECT -59.925 -9.795 -59.425 -9.720 ;
        RECT -59.925 -10.100 -56.130 -9.795 ;
        RECT -55.150 -9.820 -54.840 -9.510 ;
        RECT -54.075 -10.100 -53.690 -9.795 ;
        RECT -59.925 -10.355 -53.690 -10.100 ;
        RECT -59.925 -10.360 -59.425 -10.355 ;
        RECT -59.925 -10.390 -59.590 -10.360 ;
        RECT -56.475 -10.380 -53.690 -10.355 ;
        RECT -53.065 -10.350 -52.435 -9.955 ;
        RECT -45.665 -10.290 -45.385 -8.520 ;
        RECT -42.500 -8.580 -42.140 -7.710 ;
        RECT -37.180 -8.180 -36.875 -6.440 ;
        RECT -37.180 -8.465 -36.595 -8.180 ;
        RECT -53.065 -10.670 -52.720 -10.350 ;
        RECT -60.485 -11.150 -57.885 -10.870 ;
        RECT -58.305 -11.285 -57.885 -11.150 ;
        RECT -57.605 -10.950 -52.720 -10.670 ;
        RECT -45.665 -10.720 -45.245 -10.290 ;
        RECT -61.915 -12.525 -60.425 -12.030 ;
        RECT -57.605 -12.910 -57.325 -10.950 ;
        RECT -44.455 -11.375 -44.120 -10.420 ;
        RECT -42.435 -10.475 -42.155 -8.580 ;
        RECT -36.810 -9.350 -36.400 -8.810 ;
        RECT -42.455 -11.375 -42.110 -10.475 ;
        RECT -36.810 -10.870 -36.530 -9.350 ;
        RECT -36.075 -9.720 -35.750 -5.855 ;
        RECT -29.700 -6.290 -29.255 -5.350 ;
        RECT -29.705 -7.185 -29.250 -6.290 ;
        RECT -16.555 -6.325 -16.115 0.425 ;
        RECT -13.200 -0.075 -12.920 1.255 ;
        RECT -10.055 0.695 -9.410 1.300 ;
        RECT -4.925 1.215 -4.405 2.360 ;
        RECT -13.200 -0.565 -12.890 -0.075 ;
        RECT -4.740 -0.250 -4.405 1.215 ;
        RECT -1.535 1.205 -0.950 2.120 ;
        RECT -7.035 -0.255 -4.405 -0.250 ;
        RECT -2.190 0.255 1.840 0.600 ;
        RECT -10.850 -0.575 -10.485 -0.305 ;
        RECT -13.745 -0.855 -13.455 -0.715 ;
        RECT -12.570 -0.850 -10.485 -0.575 ;
        RECT -7.035 -0.535 -3.550 -0.255 ;
        RECT -12.570 -0.855 -10.530 -0.850 ;
        RECT -13.745 -1.145 -12.275 -0.855 ;
        RECT -7.035 -1.155 -6.555 -0.535 ;
        RECT -5.855 -0.540 -3.550 -0.535 ;
        RECT -14.975 -1.960 -9.445 -1.585 ;
        RECT -13.200 -3.015 -12.890 -2.525 ;
        RECT -10.850 -2.785 -10.485 -2.240 ;
        RECT -13.200 -4.345 -12.920 -3.015 ;
        RECT -15.350 -5.575 -15.020 -4.385 ;
        RECT -13.200 -4.625 -10.685 -4.345 ;
        RECT -11.040 -5.270 -10.685 -4.625 ;
        RECT -9.820 -4.650 -9.445 -1.960 ;
        RECT -3.855 -4.565 -3.550 -0.540 ;
        RECT -2.190 -1.870 -1.890 0.255 ;
        RECT -1.295 -0.055 -0.965 -0.025 ;
        RECT -1.340 -0.740 -0.920 -0.055 ;
        RECT 0.500 -0.680 1.060 -0.065 ;
        RECT -2.625 -2.215 -1.890 -1.870 ;
        RECT -2.625 -2.540 -2.280 -2.215 ;
        RECT -1.295 -2.540 -0.965 -0.740 ;
        RECT -0.010 -2.410 0.425 -1.755 ;
        RECT -2.625 -2.935 -2.155 -2.540 ;
        RECT -1.310 -3.530 -0.945 -2.540 ;
        RECT -0.010 -4.565 0.315 -2.410 ;
        RECT 0.715 -2.540 1.060 -0.680 ;
        RECT 1.495 -0.390 1.840 0.255 ;
        RECT 5.180 -0.390 5.675 -0.080 ;
        RECT 1.495 -0.735 5.675 -0.390 ;
        RECT 0.715 -2.935 1.185 -2.540 ;
        RECT 1.530 -3.530 2.160 -3.035 ;
        RECT 4.715 -3.465 5.040 -0.735 ;
        RECT 1.160 -4.565 1.545 -3.830 ;
        RECT -9.820 -5.080 -7.915 -4.650 ;
        RECT -3.855 -4.865 1.545 -4.565 ;
        RECT -3.600 -4.870 1.545 -4.865 ;
        RECT -10.385 -5.575 -9.970 -5.330 ;
        RECT -15.350 -5.855 -9.970 -5.575 ;
        RECT -13.980 -6.155 -13.265 -6.150 ;
        RECT -22.895 -7.185 -22.385 -6.620 ;
        RECT -16.555 -6.655 -14.285 -6.325 ;
        RECT -13.980 -6.440 -13.200 -6.155 ;
        RECT -29.705 -7.375 -22.385 -7.185 ;
        RECT -29.705 -7.465 -22.390 -7.375 ;
        RECT -16.160 -7.535 -15.530 -7.225 ;
        RECT -23.425 -8.035 -23.015 -8.030 ;
        RECT -23.425 -8.240 -23.005 -8.035 ;
        RECT -23.425 -8.520 -21.710 -8.240 ;
        RECT -36.250 -9.795 -35.750 -9.720 ;
        RECT -36.250 -10.100 -32.455 -9.795 ;
        RECT -30.400 -10.100 -30.015 -9.795 ;
        RECT -36.250 -10.355 -30.015 -10.100 ;
        RECT -36.250 -10.360 -35.750 -10.355 ;
        RECT -36.250 -10.390 -35.915 -10.360 ;
        RECT -32.800 -10.380 -30.015 -10.355 ;
        RECT -29.390 -10.350 -28.760 -9.955 ;
        RECT -21.990 -10.290 -21.710 -8.520 ;
        RECT -18.825 -8.580 -18.465 -7.710 ;
        RECT -29.390 -10.670 -29.045 -10.350 ;
        RECT -36.810 -11.150 -34.210 -10.870 ;
        RECT -34.630 -11.285 -34.210 -11.150 ;
        RECT -33.930 -10.950 -29.045 -10.670 ;
        RECT -21.990 -10.720 -21.570 -10.290 ;
        RECT -44.455 -12.115 -44.175 -11.375 ;
        RECT -61.585 -13.190 -57.325 -12.910 ;
        RECT -52.865 -12.420 -44.175 -12.115 ;
        RECT -61.585 -13.290 -60.955 -13.190 ;
        RECT -75.950 -14.465 -75.430 -13.320 ;
        RECT -79.825 -15.250 -76.050 -14.745 ;
        RECT -79.825 -15.330 -79.500 -15.250 ;
        RECT -83.635 -15.665 -79.500 -15.330 ;
        RECT -76.385 -15.415 -76.050 -15.250 ;
        RECT -83.635 -15.700 -83.290 -15.665 ;
        RECT -79.825 -15.745 -79.500 -15.665 ;
        RECT -84.225 -16.245 -83.915 -15.755 ;
        RECT -75.765 -15.930 -75.430 -14.465 ;
        RECT -72.560 -14.475 -71.975 -13.560 ;
        RECT -58.390 -14.145 -58.035 -13.500 ;
        RECT -55.920 -14.095 -55.265 -13.860 ;
        RECT -60.550 -14.425 -58.035 -14.145 ;
        RECT -57.405 -14.380 -55.265 -14.095 ;
        RECT -78.060 -15.935 -75.430 -15.930 ;
        RECT -73.215 -15.425 -69.185 -15.080 ;
        RECT -81.875 -16.255 -81.510 -15.985 ;
        RECT -84.770 -16.535 -84.480 -16.395 ;
        RECT -83.595 -16.530 -81.510 -16.255 ;
        RECT -78.060 -16.215 -74.575 -15.935 ;
        RECT -83.595 -16.535 -81.555 -16.530 ;
        RECT -84.770 -16.825 -83.300 -16.535 ;
        RECT -78.060 -16.835 -77.580 -16.215 ;
        RECT -76.880 -16.220 -74.575 -16.215 ;
        RECT -86.000 -17.640 -80.470 -17.265 ;
        RECT -84.225 -18.695 -83.915 -18.205 ;
        RECT -81.875 -18.465 -81.510 -17.920 ;
        RECT -85.810 -19.690 -85.490 -19.185 ;
        RECT -84.225 -20.025 -83.945 -18.695 ;
        RECT -83.635 -19.525 -83.290 -18.750 ;
        RECT -86.375 -21.255 -86.045 -20.065 ;
        RECT -84.225 -20.305 -81.710 -20.025 ;
        RECT -82.065 -20.950 -81.710 -20.305 ;
        RECT -80.845 -20.330 -80.470 -17.640 ;
        RECT -79.825 -19.040 -79.495 -18.770 ;
        RECT -78.660 -19.040 -77.565 -18.705 ;
        RECT -76.385 -19.040 -76.050 -19.035 ;
        RECT -79.825 -19.705 -76.050 -19.040 ;
        RECT -74.880 -20.245 -74.575 -16.220 ;
        RECT -73.215 -17.550 -72.915 -15.425 ;
        RECT -72.320 -15.735 -71.990 -15.705 ;
        RECT -72.365 -16.420 -71.945 -15.735 ;
        RECT -70.525 -16.360 -69.965 -15.745 ;
        RECT -73.650 -17.895 -72.915 -17.550 ;
        RECT -73.650 -18.220 -73.305 -17.895 ;
        RECT -72.320 -18.220 -71.990 -16.420 ;
        RECT -71.035 -18.090 -70.600 -17.435 ;
        RECT -73.650 -18.615 -73.180 -18.220 ;
        RECT -72.335 -19.210 -71.970 -18.220 ;
        RECT -71.035 -20.245 -70.710 -18.090 ;
        RECT -70.310 -18.220 -69.965 -16.360 ;
        RECT -69.530 -16.070 -69.185 -15.425 ;
        RECT -60.550 -15.755 -60.270 -14.425 ;
        RECT -59.960 -15.330 -59.615 -14.925 ;
        RECT -57.405 -14.985 -56.760 -14.380 ;
        RECT -52.865 -14.745 -52.555 -12.420 ;
        RECT -43.890 -12.490 -43.585 -11.665 ;
        RECT -33.930 -12.910 -33.650 -10.950 ;
        RECT -20.780 -11.375 -20.445 -10.420 ;
        RECT -18.760 -10.475 -18.480 -8.580 ;
        RECT -18.780 -11.375 -18.435 -10.475 ;
        RECT -20.780 -12.115 -20.500 -11.375 ;
        RECT -37.910 -13.190 -33.650 -12.910 ;
        RECT -29.190 -12.420 -20.500 -12.115 ;
        RECT -37.910 -13.290 -37.280 -13.190 ;
        RECT -52.275 -14.465 -51.755 -13.320 ;
        RECT -56.150 -15.250 -52.375 -14.745 ;
        RECT -56.150 -15.330 -55.825 -15.250 ;
        RECT -59.960 -15.665 -55.825 -15.330 ;
        RECT -52.710 -15.415 -52.375 -15.250 ;
        RECT -59.960 -15.700 -59.615 -15.665 ;
        RECT -56.150 -15.745 -55.825 -15.665 ;
        RECT -65.845 -16.070 -65.350 -15.760 ;
        RECT -69.530 -16.415 -65.350 -16.070 ;
        RECT -60.550 -16.245 -60.240 -15.755 ;
        RECT -52.090 -15.930 -51.755 -14.465 ;
        RECT -48.885 -14.475 -48.300 -13.560 ;
        RECT -34.715 -14.145 -34.360 -13.500 ;
        RECT -32.245 -14.095 -31.590 -13.860 ;
        RECT -36.875 -14.425 -34.360 -14.145 ;
        RECT -33.730 -14.380 -31.590 -14.095 ;
        RECT -54.385 -15.935 -51.755 -15.930 ;
        RECT -49.540 -15.425 -45.510 -15.080 ;
        RECT -58.200 -16.255 -57.835 -15.985 ;
        RECT -70.310 -18.615 -69.840 -18.220 ;
        RECT -69.495 -19.210 -68.865 -18.715 ;
        RECT -66.310 -19.145 -65.985 -16.415 ;
        RECT -61.095 -16.535 -60.805 -16.395 ;
        RECT -59.920 -16.530 -57.835 -16.255 ;
        RECT -54.385 -16.215 -50.900 -15.935 ;
        RECT -59.920 -16.535 -57.880 -16.530 ;
        RECT -61.095 -16.825 -59.625 -16.535 ;
        RECT -54.385 -16.835 -53.905 -16.215 ;
        RECT -53.205 -16.220 -50.900 -16.215 ;
        RECT -62.325 -17.640 -56.795 -17.265 ;
        RECT -60.550 -18.695 -60.240 -18.205 ;
        RECT -58.200 -18.465 -57.835 -17.920 ;
        RECT -69.865 -20.245 -69.480 -19.510 ;
        RECT -62.135 -19.690 -61.815 -19.185 ;
        RECT -60.550 -20.025 -60.270 -18.695 ;
        RECT -59.960 -19.525 -59.615 -18.750 ;
        RECT -80.845 -20.760 -78.940 -20.330 ;
        RECT -74.880 -20.545 -69.480 -20.245 ;
        RECT -74.625 -20.550 -69.480 -20.545 ;
        RECT -81.410 -21.255 -80.995 -21.010 ;
        RECT -86.375 -21.535 -80.995 -21.255 ;
        RECT -62.700 -21.255 -62.370 -20.065 ;
        RECT -60.550 -20.305 -58.035 -20.025 ;
        RECT -58.390 -20.950 -58.035 -20.305 ;
        RECT -57.170 -20.330 -56.795 -17.640 ;
        RECT -56.150 -19.040 -55.820 -18.770 ;
        RECT -54.985 -19.040 -53.890 -18.705 ;
        RECT -52.710 -19.040 -52.375 -19.035 ;
        RECT -56.150 -19.705 -52.375 -19.040 ;
        RECT -51.205 -20.245 -50.900 -16.220 ;
        RECT -49.540 -17.550 -49.240 -15.425 ;
        RECT -48.645 -15.735 -48.315 -15.705 ;
        RECT -48.690 -16.420 -48.270 -15.735 ;
        RECT -46.850 -16.360 -46.290 -15.745 ;
        RECT -49.975 -17.895 -49.240 -17.550 ;
        RECT -49.975 -18.220 -49.630 -17.895 ;
        RECT -48.645 -18.220 -48.315 -16.420 ;
        RECT -47.360 -18.090 -46.925 -17.435 ;
        RECT -49.975 -18.615 -49.505 -18.220 ;
        RECT -48.660 -19.210 -48.295 -18.220 ;
        RECT -47.360 -20.245 -47.035 -18.090 ;
        RECT -46.635 -18.220 -46.290 -16.360 ;
        RECT -45.855 -16.070 -45.510 -15.425 ;
        RECT -36.875 -15.755 -36.595 -14.425 ;
        RECT -36.285 -15.330 -35.940 -14.925 ;
        RECT -33.730 -14.985 -33.085 -14.380 ;
        RECT -29.190 -14.745 -28.880 -12.420 ;
        RECT -20.215 -12.490 -19.910 -11.665 ;
        RECT -14.565 -12.030 -14.285 -6.655 ;
        RECT -13.505 -8.180 -13.200 -6.440 ;
        RECT -13.505 -8.465 -12.920 -8.180 ;
        RECT -13.135 -9.350 -12.725 -8.810 ;
        RECT -13.135 -10.870 -12.855 -9.350 ;
        RECT -12.400 -9.720 -12.075 -5.855 ;
        RECT -6.025 -6.290 -5.580 -5.350 ;
        RECT -6.030 -7.185 -5.575 -6.290 ;
        RECT 0.780 -7.185 1.290 -6.620 ;
        RECT -9.420 -7.540 -8.810 -7.215 ;
        RECT -6.030 -7.375 1.290 -7.185 ;
        RECT -6.030 -7.465 1.285 -7.375 ;
        RECT -9.185 -9.180 -8.810 -7.540 ;
        RECT 0.250 -8.035 0.660 -8.030 ;
        RECT 0.250 -8.240 0.670 -8.035 ;
        RECT 0.250 -8.520 1.965 -8.240 ;
        RECT -7.790 -9.180 -7.500 -9.175 ;
        RECT -9.185 -9.510 -7.490 -9.180 ;
        RECT -12.575 -9.795 -12.075 -9.720 ;
        RECT -12.575 -10.100 -8.780 -9.795 ;
        RECT -7.800 -9.820 -7.490 -9.510 ;
        RECT -6.725 -10.100 -6.340 -9.795 ;
        RECT -12.575 -10.355 -6.340 -10.100 ;
        RECT -12.575 -10.360 -12.075 -10.355 ;
        RECT -12.575 -10.390 -12.240 -10.360 ;
        RECT -9.125 -10.380 -6.340 -10.355 ;
        RECT -5.715 -10.350 -5.085 -9.955 ;
        RECT 1.685 -10.290 1.965 -8.520 ;
        RECT 4.850 -8.580 5.210 -7.710 ;
        RECT -5.715 -10.670 -5.370 -10.350 ;
        RECT -13.135 -11.150 -10.535 -10.870 ;
        RECT -10.955 -11.285 -10.535 -11.150 ;
        RECT -10.255 -10.950 -5.370 -10.670 ;
        RECT 1.685 -10.720 2.105 -10.290 ;
        RECT -14.565 -12.525 -13.075 -12.030 ;
        RECT -10.255 -12.910 -9.975 -10.950 ;
        RECT 2.895 -11.375 3.230 -10.420 ;
        RECT 4.915 -10.475 5.195 -8.580 ;
        RECT 4.895 -11.375 5.240 -10.475 ;
        RECT 2.895 -12.115 3.175 -11.375 ;
        RECT -14.235 -13.190 -9.975 -12.910 ;
        RECT -5.515 -12.420 3.175 -12.115 ;
        RECT -14.235 -13.290 -13.605 -13.190 ;
        RECT -28.600 -14.465 -28.080 -13.320 ;
        RECT -32.475 -15.250 -28.700 -14.745 ;
        RECT -32.475 -15.330 -32.150 -15.250 ;
        RECT -36.285 -15.665 -32.150 -15.330 ;
        RECT -29.035 -15.415 -28.700 -15.250 ;
        RECT -36.285 -15.700 -35.940 -15.665 ;
        RECT -32.475 -15.745 -32.150 -15.665 ;
        RECT -42.170 -16.070 -41.675 -15.760 ;
        RECT -45.855 -16.415 -41.675 -16.070 ;
        RECT -36.875 -16.245 -36.565 -15.755 ;
        RECT -28.415 -15.930 -28.080 -14.465 ;
        RECT -25.210 -14.475 -24.625 -13.560 ;
        RECT -11.040 -14.145 -10.685 -13.500 ;
        RECT -8.570 -14.095 -7.915 -13.860 ;
        RECT -13.200 -14.425 -10.685 -14.145 ;
        RECT -10.055 -14.380 -7.915 -14.095 ;
        RECT -30.710 -15.935 -28.080 -15.930 ;
        RECT -25.865 -15.425 -21.835 -15.080 ;
        RECT -34.525 -16.255 -34.160 -15.985 ;
        RECT -46.635 -18.615 -46.165 -18.220 ;
        RECT -45.820 -19.210 -45.190 -18.715 ;
        RECT -42.635 -19.145 -42.310 -16.415 ;
        RECT -37.420 -16.535 -37.130 -16.395 ;
        RECT -36.245 -16.530 -34.160 -16.255 ;
        RECT -30.710 -16.215 -27.225 -15.935 ;
        RECT -36.245 -16.535 -34.205 -16.530 ;
        RECT -37.420 -16.825 -35.950 -16.535 ;
        RECT -30.710 -16.835 -30.230 -16.215 ;
        RECT -29.530 -16.220 -27.225 -16.215 ;
        RECT -38.650 -17.640 -33.120 -17.265 ;
        RECT -36.875 -18.695 -36.565 -18.205 ;
        RECT -34.525 -18.465 -34.160 -17.920 ;
        RECT -46.190 -20.245 -45.805 -19.510 ;
        RECT -38.460 -19.690 -38.140 -19.185 ;
        RECT -36.875 -20.025 -36.595 -18.695 ;
        RECT -36.285 -19.525 -35.940 -18.750 ;
        RECT -57.170 -20.760 -55.265 -20.330 ;
        RECT -51.205 -20.545 -45.805 -20.245 ;
        RECT -50.950 -20.550 -45.805 -20.545 ;
        RECT -57.735 -21.255 -57.320 -21.010 ;
        RECT -62.700 -21.535 -57.320 -21.255 ;
        RECT -39.025 -21.255 -38.695 -20.065 ;
        RECT -36.875 -20.305 -34.360 -20.025 ;
        RECT -34.715 -20.950 -34.360 -20.305 ;
        RECT -33.495 -20.330 -33.120 -17.640 ;
        RECT -32.475 -19.040 -32.145 -18.770 ;
        RECT -31.310 -19.040 -30.215 -18.705 ;
        RECT -29.035 -19.040 -28.700 -19.035 ;
        RECT -32.475 -19.705 -28.700 -19.040 ;
        RECT -27.530 -20.245 -27.225 -16.220 ;
        RECT -25.865 -17.550 -25.565 -15.425 ;
        RECT -24.970 -15.735 -24.640 -15.705 ;
        RECT -25.015 -16.420 -24.595 -15.735 ;
        RECT -23.175 -16.360 -22.615 -15.745 ;
        RECT -26.300 -17.895 -25.565 -17.550 ;
        RECT -26.300 -18.220 -25.955 -17.895 ;
        RECT -24.970 -18.220 -24.640 -16.420 ;
        RECT -23.685 -18.090 -23.250 -17.435 ;
        RECT -26.300 -18.615 -25.830 -18.220 ;
        RECT -24.985 -19.210 -24.620 -18.220 ;
        RECT -23.685 -20.245 -23.360 -18.090 ;
        RECT -22.960 -18.220 -22.615 -16.360 ;
        RECT -22.180 -16.070 -21.835 -15.425 ;
        RECT -13.200 -15.755 -12.920 -14.425 ;
        RECT -12.610 -15.330 -12.265 -14.925 ;
        RECT -10.055 -14.985 -9.410 -14.380 ;
        RECT -5.515 -14.745 -5.205 -12.420 ;
        RECT 3.460 -12.490 3.765 -11.665 ;
        RECT -4.925 -14.465 -4.405 -13.320 ;
        RECT -8.800 -15.250 -5.025 -14.745 ;
        RECT -8.800 -15.330 -8.475 -15.250 ;
        RECT -12.610 -15.665 -8.475 -15.330 ;
        RECT -5.360 -15.415 -5.025 -15.250 ;
        RECT -12.610 -15.700 -12.265 -15.665 ;
        RECT -8.800 -15.745 -8.475 -15.665 ;
        RECT -18.495 -16.070 -18.000 -15.760 ;
        RECT -22.180 -16.415 -18.000 -16.070 ;
        RECT -13.200 -16.245 -12.890 -15.755 ;
        RECT -4.740 -15.930 -4.405 -14.465 ;
        RECT -1.535 -14.475 -0.950 -13.560 ;
        RECT -7.035 -15.935 -4.405 -15.930 ;
        RECT -2.190 -15.425 1.840 -15.080 ;
        RECT -10.850 -16.255 -10.485 -15.985 ;
        RECT -22.960 -18.615 -22.490 -18.220 ;
        RECT -22.145 -19.210 -21.515 -18.715 ;
        RECT -18.960 -19.145 -18.635 -16.415 ;
        RECT -13.745 -16.535 -13.455 -16.395 ;
        RECT -12.570 -16.530 -10.485 -16.255 ;
        RECT -7.035 -16.215 -3.550 -15.935 ;
        RECT -12.570 -16.535 -10.530 -16.530 ;
        RECT -13.745 -16.825 -12.275 -16.535 ;
        RECT -7.035 -16.835 -6.555 -16.215 ;
        RECT -5.855 -16.220 -3.550 -16.215 ;
        RECT -14.975 -17.640 -9.445 -17.265 ;
        RECT -13.200 -18.695 -12.890 -18.205 ;
        RECT -10.850 -18.465 -10.485 -17.920 ;
        RECT -22.515 -20.245 -22.130 -19.510 ;
        RECT -14.785 -19.690 -14.465 -19.185 ;
        RECT -13.200 -20.025 -12.920 -18.695 ;
        RECT -12.610 -19.525 -12.265 -18.750 ;
        RECT -33.495 -20.760 -31.590 -20.330 ;
        RECT -27.530 -20.545 -22.130 -20.245 ;
        RECT -27.275 -20.550 -22.130 -20.545 ;
        RECT -34.060 -21.255 -33.645 -21.010 ;
        RECT -39.025 -21.535 -33.645 -21.255 ;
        RECT -15.350 -21.255 -15.020 -20.065 ;
        RECT -13.200 -20.305 -10.685 -20.025 ;
        RECT -11.040 -20.950 -10.685 -20.305 ;
        RECT -9.820 -20.330 -9.445 -17.640 ;
        RECT -8.800 -19.040 -8.470 -18.770 ;
        RECT -7.635 -19.040 -6.540 -18.705 ;
        RECT -5.360 -19.040 -5.025 -19.035 ;
        RECT -8.800 -19.705 -5.025 -19.040 ;
        RECT -3.855 -20.245 -3.550 -16.220 ;
        RECT -2.190 -17.550 -1.890 -15.425 ;
        RECT -1.295 -15.735 -0.965 -15.705 ;
        RECT -1.340 -16.420 -0.920 -15.735 ;
        RECT 0.500 -16.360 1.060 -15.745 ;
        RECT -2.625 -17.895 -1.890 -17.550 ;
        RECT -2.625 -18.220 -2.280 -17.895 ;
        RECT -1.295 -18.220 -0.965 -16.420 ;
        RECT -0.010 -18.090 0.425 -17.435 ;
        RECT -2.625 -18.615 -2.155 -18.220 ;
        RECT -1.310 -19.210 -0.945 -18.220 ;
        RECT -0.010 -20.245 0.315 -18.090 ;
        RECT 0.715 -18.220 1.060 -16.360 ;
        RECT 1.495 -16.070 1.840 -15.425 ;
        RECT 5.180 -16.070 5.675 -15.760 ;
        RECT 1.495 -16.415 5.675 -16.070 ;
        RECT 0.715 -18.615 1.185 -18.220 ;
        RECT 1.530 -19.210 2.160 -18.715 ;
        RECT 4.715 -19.145 5.040 -16.415 ;
        RECT 1.160 -20.245 1.545 -19.510 ;
        RECT -9.820 -20.760 -7.915 -20.330 ;
        RECT -3.855 -20.545 1.545 -20.245 ;
        RECT -3.600 -20.550 1.545 -20.545 ;
        RECT -10.385 -21.255 -9.970 -21.010 ;
        RECT -15.350 -21.535 -9.970 -21.255 ;
      LAYER Via2 ;
        RECT -82.055 1.315 -81.720 2.120 ;
        RECT -72.545 1.265 -71.990 2.060 ;
        RECT -58.380 1.315 -58.045 2.120 ;
        RECT -84.210 -2.955 -83.930 -2.585 ;
        RECT -81.850 -2.725 -81.520 -2.310 ;
        RECT -85.800 -3.935 -85.500 -3.565 ;
        RECT -79.785 -3.955 -79.500 -3.150 ;
        RECT -70.465 -0.670 -70.165 -0.075 ;
        RECT -69.435 -3.510 -68.935 -3.060 ;
        RECT -48.870 1.265 -48.315 2.060 ;
        RECT -34.705 1.315 -34.370 2.120 ;
        RECT -60.535 -2.955 -60.255 -2.585 ;
        RECT -58.175 -2.725 -57.845 -2.310 ;
        RECT -46.790 -0.670 -46.490 -0.075 ;
        RECT -25.195 1.265 -24.640 2.060 ;
        RECT -11.030 1.315 -10.695 2.120 ;
        RECT -45.760 -3.510 -45.260 -3.060 ;
        RECT -36.860 -2.955 -36.580 -2.585 ;
        RECT -34.500 -2.725 -34.170 -2.310 ;
        RECT -38.450 -3.935 -38.150 -3.565 ;
        RECT -63.450 -7.525 -62.940 -7.235 ;
        RECT -82.055 -14.365 -81.720 -13.560 ;
        RECT -67.555 -12.425 -67.275 -11.725 ;
        RECT -32.435 -3.955 -32.150 -3.150 ;
        RECT -23.115 -0.670 -22.815 -0.075 ;
        RECT -22.085 -3.510 -21.585 -3.060 ;
        RECT -1.520 1.265 -0.965 2.060 ;
        RECT -13.185 -2.955 -12.905 -2.585 ;
        RECT -10.825 -2.725 -10.495 -2.310 ;
        RECT 0.560 -0.670 0.860 -0.075 ;
        RECT 1.590 -3.510 2.090 -3.060 ;
        RECT -16.100 -7.525 -15.590 -7.235 ;
        RECT -72.545 -14.415 -71.990 -13.620 ;
        RECT -58.380 -14.365 -58.045 -13.560 ;
        RECT -84.210 -18.635 -83.930 -18.265 ;
        RECT -81.850 -18.405 -81.520 -17.990 ;
        RECT -85.800 -19.615 -85.500 -19.245 ;
        RECT -79.785 -19.635 -79.500 -18.830 ;
        RECT -78.705 -19.620 -78.145 -19.155 ;
        RECT -70.465 -16.350 -70.165 -15.755 ;
        RECT -43.880 -12.425 -43.600 -11.725 ;
        RECT -48.870 -14.415 -48.315 -13.620 ;
        RECT -34.705 -14.365 -34.370 -13.560 ;
        RECT -69.435 -19.190 -68.935 -18.740 ;
        RECT -60.535 -18.635 -60.255 -18.265 ;
        RECT -58.175 -18.405 -57.845 -17.990 ;
        RECT -62.125 -19.615 -61.825 -19.245 ;
        RECT -56.110 -19.635 -55.825 -18.830 ;
        RECT -55.030 -19.620 -54.470 -19.155 ;
        RECT -46.790 -16.350 -46.490 -15.755 ;
        RECT -20.205 -12.425 -19.925 -11.725 ;
        RECT -25.195 -14.415 -24.640 -13.620 ;
        RECT -11.030 -14.365 -10.695 -13.560 ;
        RECT -45.760 -19.190 -45.260 -18.740 ;
        RECT -36.860 -18.635 -36.580 -18.265 ;
        RECT -34.500 -18.405 -34.170 -17.990 ;
        RECT -38.450 -19.615 -38.150 -19.245 ;
        RECT -32.435 -19.635 -32.150 -18.830 ;
        RECT -31.355 -19.620 -30.795 -19.155 ;
        RECT -23.115 -16.350 -22.815 -15.755 ;
        RECT 3.470 -12.425 3.750 -11.725 ;
        RECT -1.520 -14.415 -0.965 -13.620 ;
        RECT -22.085 -19.190 -21.585 -18.740 ;
        RECT -13.185 -18.635 -12.905 -18.265 ;
        RECT -10.825 -18.405 -10.495 -17.990 ;
        RECT -14.775 -19.615 -14.475 -19.245 ;
        RECT -8.760 -19.635 -8.475 -18.830 ;
        RECT -7.680 -19.620 -7.120 -19.155 ;
        RECT 0.560 -16.350 0.860 -15.755 ;
        RECT 1.590 -19.190 2.090 -18.740 ;
      LAYER Metal3 ;
        RECT -82.055 2.060 -81.720 2.170 ;
        RECT -58.380 2.060 -58.045 2.170 ;
        RECT -34.705 2.060 -34.370 2.170 ;
        RECT -11.030 2.060 -10.695 2.170 ;
        RECT -82.065 1.760 -71.940 2.060 ;
        RECT -58.390 1.760 -48.265 2.060 ;
        RECT -34.715 1.760 -24.590 2.060 ;
        RECT -11.040 1.760 -0.915 2.060 ;
        RECT -82.055 1.265 -81.720 1.760 ;
        RECT -72.595 1.265 -71.940 1.760 ;
        RECT -58.380 1.265 -58.045 1.760 ;
        RECT -48.920 1.265 -48.265 1.760 ;
        RECT -34.705 1.265 -34.370 1.760 ;
        RECT -25.245 1.265 -24.590 1.760 ;
        RECT -11.030 1.265 -10.695 1.760 ;
        RECT -1.570 1.265 -0.915 1.760 ;
        RECT -70.465 -0.345 -70.165 -0.025 ;
        RECT -46.790 -0.345 -46.490 -0.025 ;
        RECT -23.115 -0.345 -22.815 -0.025 ;
        RECT 0.560 -0.345 0.860 -0.025 ;
        RECT -84.210 -0.670 -70.165 -0.345 ;
        RECT -84.210 -3.015 -83.930 -0.670 ;
        RECT -70.465 -0.720 -70.165 -0.670 ;
        RECT -60.535 -0.670 -46.490 -0.345 ;
        RECT -81.850 -2.350 -81.520 -2.260 ;
        RECT -81.880 -2.675 -76.660 -2.350 ;
        RECT -81.850 -2.775 -81.520 -2.675 ;
        RECT -85.850 -3.630 -85.450 -3.565 ;
        RECT -79.835 -3.630 -79.450 -3.150 ;
        RECT -77.015 -3.185 -76.660 -2.675 ;
        RECT -60.535 -3.015 -60.255 -0.670 ;
        RECT -46.790 -0.720 -46.490 -0.670 ;
        RECT -36.860 -0.670 -22.815 -0.345 ;
        RECT -58.175 -2.350 -57.845 -2.260 ;
        RECT -58.205 -2.675 -52.985 -2.350 ;
        RECT -58.175 -2.775 -57.845 -2.675 ;
        RECT -69.495 -3.185 -68.865 -3.060 ;
        RECT -77.015 -3.510 -68.865 -3.185 ;
        RECT -53.340 -3.185 -52.985 -2.675 ;
        RECT -36.860 -3.015 -36.580 -0.670 ;
        RECT -23.115 -0.720 -22.815 -0.670 ;
        RECT -13.185 -0.670 0.860 -0.345 ;
        RECT -34.500 -2.350 -34.170 -2.260 ;
        RECT -34.530 -2.675 -29.310 -2.350 ;
        RECT -34.500 -2.775 -34.170 -2.675 ;
        RECT -45.820 -3.185 -45.190 -3.060 ;
        RECT -53.340 -3.510 -45.190 -3.185 ;
        RECT -38.500 -3.630 -38.100 -3.565 ;
        RECT -32.485 -3.630 -32.100 -3.150 ;
        RECT -29.665 -3.185 -29.310 -2.675 ;
        RECT -13.185 -3.015 -12.905 -0.670 ;
        RECT 0.560 -0.720 0.860 -0.670 ;
        RECT -10.825 -2.350 -10.495 -2.260 ;
        RECT -10.855 -2.675 -5.635 -2.350 ;
        RECT -10.825 -2.775 -10.495 -2.675 ;
        RECT -22.145 -3.185 -21.515 -3.060 ;
        RECT -29.665 -3.510 -21.515 -3.185 ;
        RECT -5.990 -3.185 -5.635 -2.675 ;
        RECT 1.530 -3.185 2.160 -3.060 ;
        RECT -5.990 -3.510 2.160 -3.185 ;
        RECT -86.000 -3.955 -79.450 -3.630 ;
        RECT -38.650 -3.955 -32.100 -3.630 ;
        RECT -79.750 -6.330 -79.450 -3.955 ;
        RECT -32.400 -6.330 -32.100 -3.955 ;
        RECT -79.750 -6.655 -63.905 -6.330 ;
        RECT -32.400 -6.655 -16.555 -6.330 ;
        RECT -64.225 -7.235 -63.905 -6.655 ;
        RECT -16.875 -7.235 -16.555 -6.655 ;
        RECT -64.225 -7.525 -62.890 -7.235 ;
        RECT -16.875 -7.525 -15.540 -7.235 ;
        RECT -67.565 -12.490 -67.130 -11.675 ;
        RECT -43.890 -12.490 -43.455 -11.675 ;
        RECT -20.215 -12.490 -19.780 -11.675 ;
        RECT 3.460 -12.490 3.895 -11.675 ;
        RECT -82.055 -13.620 -81.720 -13.510 ;
        RECT -82.065 -13.920 -71.940 -13.620 ;
        RECT -82.055 -14.415 -81.720 -13.920 ;
        RECT -72.595 -14.415 -71.940 -13.920 ;
        RECT -70.465 -16.025 -70.165 -15.705 ;
        RECT -84.210 -16.350 -70.165 -16.025 ;
        RECT -84.210 -18.695 -83.930 -16.350 ;
        RECT -70.465 -16.400 -70.165 -16.350 ;
        RECT -81.850 -18.030 -81.520 -17.940 ;
        RECT -81.880 -18.355 -76.660 -18.030 ;
        RECT -81.850 -18.455 -81.520 -18.355 ;
        RECT -85.850 -19.310 -85.450 -19.245 ;
        RECT -79.835 -19.310 -79.450 -18.830 ;
        RECT -77.015 -18.865 -76.660 -18.355 ;
        RECT -69.495 -18.865 -68.865 -18.740 ;
        RECT -86.000 -19.635 -79.450 -19.310 ;
        RECT -78.705 -19.960 -78.145 -19.105 ;
        RECT -77.015 -19.190 -68.865 -18.865 ;
        RECT -67.420 -19.425 -67.130 -12.490 ;
        RECT -58.380 -13.620 -58.045 -13.510 ;
        RECT -58.390 -13.920 -48.265 -13.620 ;
        RECT -58.380 -14.415 -58.045 -13.920 ;
        RECT -48.920 -14.415 -48.265 -13.920 ;
        RECT -46.790 -16.025 -46.490 -15.705 ;
        RECT -60.535 -16.350 -46.490 -16.025 ;
        RECT -60.535 -18.695 -60.255 -16.350 ;
        RECT -46.790 -16.400 -46.490 -16.350 ;
        RECT -58.175 -18.030 -57.845 -17.940 ;
        RECT -58.205 -18.355 -52.985 -18.030 ;
        RECT -58.175 -18.455 -57.845 -18.355 ;
        RECT -62.175 -19.310 -61.775 -19.245 ;
        RECT -56.160 -19.310 -55.775 -18.830 ;
        RECT -53.340 -18.865 -52.985 -18.355 ;
        RECT -45.820 -18.865 -45.190 -18.740 ;
        RECT -67.420 -19.960 -67.120 -19.425 ;
        RECT -62.325 -19.635 -55.775 -19.310 ;
        RECT -78.705 -20.250 -67.120 -19.960 ;
        RECT -55.030 -19.960 -54.470 -19.105 ;
        RECT -53.340 -19.190 -45.190 -18.865 ;
        RECT -43.745 -19.425 -43.455 -12.490 ;
        RECT -34.705 -13.620 -34.370 -13.510 ;
        RECT -34.715 -13.920 -24.590 -13.620 ;
        RECT -34.705 -14.415 -34.370 -13.920 ;
        RECT -25.245 -14.415 -24.590 -13.920 ;
        RECT -23.115 -16.025 -22.815 -15.705 ;
        RECT -36.860 -16.350 -22.815 -16.025 ;
        RECT -36.860 -18.695 -36.580 -16.350 ;
        RECT -23.115 -16.400 -22.815 -16.350 ;
        RECT -34.500 -18.030 -34.170 -17.940 ;
        RECT -34.530 -18.355 -29.310 -18.030 ;
        RECT -34.500 -18.455 -34.170 -18.355 ;
        RECT -38.500 -19.310 -38.100 -19.245 ;
        RECT -32.485 -19.310 -32.100 -18.830 ;
        RECT -29.665 -18.865 -29.310 -18.355 ;
        RECT -22.145 -18.865 -21.515 -18.740 ;
        RECT -43.745 -19.960 -43.445 -19.425 ;
        RECT -38.650 -19.635 -32.100 -19.310 ;
        RECT -55.030 -20.250 -43.445 -19.960 ;
        RECT -31.355 -19.960 -30.795 -19.105 ;
        RECT -29.665 -19.190 -21.515 -18.865 ;
        RECT -20.070 -19.425 -19.780 -12.490 ;
        RECT -11.030 -13.620 -10.695 -13.510 ;
        RECT -11.040 -13.920 -0.915 -13.620 ;
        RECT -11.030 -14.415 -10.695 -13.920 ;
        RECT -1.570 -14.415 -0.915 -13.920 ;
        RECT 0.560 -16.025 0.860 -15.705 ;
        RECT -13.185 -16.350 0.860 -16.025 ;
        RECT -13.185 -18.695 -12.905 -16.350 ;
        RECT 0.560 -16.400 0.860 -16.350 ;
        RECT -10.825 -18.030 -10.495 -17.940 ;
        RECT -10.855 -18.355 -5.635 -18.030 ;
        RECT -10.825 -18.455 -10.495 -18.355 ;
        RECT -14.825 -19.310 -14.425 -19.245 ;
        RECT -8.810 -19.310 -8.425 -18.830 ;
        RECT -5.990 -18.865 -5.635 -18.355 ;
        RECT 1.530 -18.865 2.160 -18.740 ;
        RECT -20.070 -19.960 -19.770 -19.425 ;
        RECT -14.975 -19.635 -8.425 -19.310 ;
        RECT -31.355 -20.250 -19.770 -19.960 ;
        RECT -7.680 -19.960 -7.120 -19.105 ;
        RECT -5.990 -19.190 2.160 -18.865 ;
        RECT 3.605 -19.425 3.895 -12.490 ;
        RECT 3.605 -19.960 3.905 -19.425 ;
        RECT -7.680 -20.250 3.905 -19.960 ;
  END
END 5v0_adder_4t_macro
END LIBRARY

